VERSION 5.8 ;
BUSBITCHARS "[]" ;
DIVIDERCHAR "/" ;
UNITS
    DATABASE MICRONS 1000 ;
END UNITS

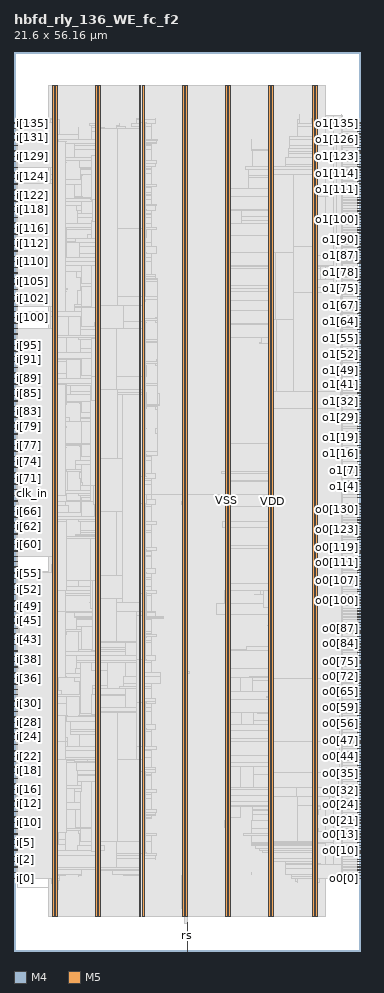
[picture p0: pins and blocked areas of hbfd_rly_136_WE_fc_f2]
MACRO hbfd_rly_136_WE_fc_f2
  FOREIGN hbfd_rly_136_WE_fc_f2 0 0 ;
  CLASS BLOCK ;
  SIZE 21.6 BY 56.16 ;
  PIN clk_in
    DIRECTION INPUT ;
    USE SIGNAL ;
    PORT
      LAYER M4 ;
        RECT  0 28.08 0.192 28.104 ;
    END
  END clk_in
  PIN clk_out0
    DIRECTION OUTPUT ;
    USE SIGNAL ;
    PORT
      LAYER M4 ;
        RECT  21.408 16.224 21.6 16.248 ;
    END
  END clk_out0
  PIN clk_out1
    DIRECTION OUTPUT ;
    USE SIGNAL ;
    PORT
      LAYER M4 ;
        RECT  21.408 39.984 21.6 40.008 ;
    END
  END clk_out1
  PIN i[0]
    DIRECTION INPUT ;
    USE SIGNAL ;
    PORT
      LAYER M4 ;
        RECT  0 4.512 0.192 4.536 ;
    END
  END i[0]
  PIN i[100]
    DIRECTION INPUT ;
    USE SIGNAL ;
    PORT
      LAYER M4 ;
        RECT  0 39.504 0.192 39.528 ;
    END
  END i[100]
  PIN i[101]
    DIRECTION INPUT ;
    USE SIGNAL ;
    PORT
      LAYER M4 ;
        RECT  0 39.888 0.192 39.912 ;
    END
  END i[101]
  PIN i[102]
    DIRECTION INPUT ;
    USE SIGNAL ;
    PORT
      LAYER M4 ;
        RECT  0 40.224 0.192 40.248 ;
    END
  END i[102]
  PIN i[103]
    DIRECTION INPUT ;
    USE SIGNAL ;
    PORT
      LAYER M4 ;
        RECT  0 40.56 0.192 40.584 ;
    END
  END i[103]
  PIN i[104]
    DIRECTION INPUT ;
    USE SIGNAL ;
    PORT
      LAYER M4 ;
        RECT  0 40.896 0.192 40.92 ;
    END
  END i[104]
  PIN i[105]
    DIRECTION INPUT ;
    USE SIGNAL ;
    PORT
      LAYER M4 ;
        RECT  0 41.28 0.192 41.304 ;
    END
  END i[105]
  PIN i[106]
    DIRECTION INPUT ;
    USE SIGNAL ;
    PORT
      LAYER M4 ;
        RECT  0 41.616 0.192 41.64 ;
    END
  END i[106]
  PIN i[107]
    DIRECTION INPUT ;
    USE SIGNAL ;
    PORT
      LAYER M4 ;
        RECT  0 41.952 0.192 41.976 ;
    END
  END i[107]
  PIN i[108]
    DIRECTION INPUT ;
    USE SIGNAL ;
    PORT
      LAYER M4 ;
        RECT  0 42.288 0.192 42.312 ;
    END
  END i[108]
  PIN i[109]
    DIRECTION INPUT ;
    USE SIGNAL ;
    PORT
      LAYER M4 ;
        RECT  0 42.624 0.192 42.648 ;
    END
  END i[109]
  PIN i[10]
    DIRECTION INPUT ;
    USE SIGNAL ;
    PORT
      LAYER M4 ;
        RECT  0 8.016 0.192 8.04 ;
    END
  END i[10]
  PIN i[110]
    DIRECTION INPUT ;
    USE SIGNAL ;
    PORT
      LAYER M4 ;
        RECT  0 43.008 0.192 43.032 ;
    END
  END i[110]
  PIN i[111]
    DIRECTION INPUT ;
    USE SIGNAL ;
    PORT
      LAYER M4 ;
        RECT  0 43.344 0.192 43.368 ;
    END
  END i[111]
  PIN i[112]
    DIRECTION INPUT ;
    USE SIGNAL ;
    PORT
      LAYER M4 ;
        RECT  0 43.68 0.192 43.704 ;
    END
  END i[112]
  PIN i[113]
    DIRECTION INPUT ;
    USE SIGNAL ;
    PORT
      LAYER M4 ;
        RECT  0 44.016 0.192 44.04 ;
    END
  END i[113]
  PIN i[114]
    DIRECTION INPUT ;
    USE SIGNAL ;
    PORT
      LAYER M4 ;
        RECT  0 44.4 0.192 44.424 ;
    END
  END i[114]
  PIN i[115]
    DIRECTION INPUT ;
    USE SIGNAL ;
    PORT
      LAYER M4 ;
        RECT  0 44.736 0.192 44.76 ;
    END
  END i[115]
  PIN i[116]
    DIRECTION INPUT ;
    USE SIGNAL ;
    PORT
      LAYER M4 ;
        RECT  0 45.072 0.192 45.096 ;
    END
  END i[116]
  PIN i[117]
    DIRECTION INPUT ;
    USE SIGNAL ;
    PORT
      LAYER M4 ;
        RECT  0 45.408 0.192 45.432 ;
    END
  END i[117]
  PIN i[118]
    DIRECTION INPUT ;
    USE SIGNAL ;
    PORT
      LAYER M4 ;
        RECT  0 45.744 0.192 45.768 ;
    END
  END i[118]
  PIN i[119]
    DIRECTION INPUT ;
    USE SIGNAL ;
    PORT
      LAYER M4 ;
        RECT  0 46.128 0.192 46.152 ;
    END
  END i[119]
  PIN i[11]
    DIRECTION INPUT ;
    USE SIGNAL ;
    PORT
      LAYER M4 ;
        RECT  0 8.352 0.192 8.376 ;
    END
  END i[11]
  PIN i[120]
    DIRECTION INPUT ;
    USE SIGNAL ;
    PORT
      LAYER M4 ;
        RECT  0 46.464 0.192 46.488 ;
    END
  END i[120]
  PIN i[121]
    DIRECTION INPUT ;
    USE SIGNAL ;
    PORT
      LAYER M4 ;
        RECT  0 46.8 0.192 46.824 ;
    END
  END i[121]
  PIN i[122]
    DIRECTION INPUT ;
    USE SIGNAL ;
    PORT
      LAYER M4 ;
        RECT  0 47.136 0.192 47.16 ;
    END
  END i[122]
  PIN i[123]
    DIRECTION INPUT ;
    USE SIGNAL ;
    PORT
      LAYER M4 ;
        RECT  0 47.472 0.192 47.496 ;
    END
  END i[123]
  PIN i[124]
    DIRECTION INPUT ;
    USE SIGNAL ;
    PORT
      LAYER M4 ;
        RECT  0 47.856 0.192 47.88 ;
    END
  END i[124]
  PIN i[125]
    DIRECTION INPUT ;
    USE SIGNAL ;
    PORT
      LAYER M4 ;
        RECT  0 48.192 0.192 48.216 ;
    END
  END i[125]
  PIN i[126]
    DIRECTION INPUT ;
    USE SIGNAL ;
    PORT
      LAYER M4 ;
        RECT  0 48.528 0.192 48.552 ;
    END
  END i[126]
  PIN i[127]
    DIRECTION INPUT ;
    USE SIGNAL ;
    PORT
      LAYER M4 ;
        RECT  0 48.864 0.192 48.888 ;
    END
  END i[127]
  PIN i[128]
    DIRECTION INPUT ;
    USE SIGNAL ;
    PORT
      LAYER M4 ;
        RECT  0 49.248 0.192 49.272 ;
    END
  END i[128]
  PIN i[129]
    DIRECTION INPUT ;
    USE SIGNAL ;
    PORT
      LAYER M4 ;
        RECT  0 49.584 0.192 49.608 ;
    END
  END i[129]
  PIN i[12]
    DIRECTION INPUT ;
    USE SIGNAL ;
    PORT
      LAYER M4 ;
        RECT  0 8.688 0.192 8.712 ;
    END
  END i[12]
  PIN i[130]
    DIRECTION INPUT ;
    USE SIGNAL ;
    PORT
      LAYER M4 ;
        RECT  0 49.92 0.192 49.944 ;
    END
  END i[130]
  PIN i[131]
    DIRECTION INPUT ;
    USE SIGNAL ;
    PORT
      LAYER M4 ;
        RECT  0 50.256 0.192 50.28 ;
    END
  END i[131]
  PIN i[132]
    DIRECTION INPUT ;
    USE SIGNAL ;
    PORT
      LAYER M4 ;
        RECT  0 50.592 0.192 50.616 ;
    END
  END i[132]
  PIN i[133]
    DIRECTION INPUT ;
    USE SIGNAL ;
    PORT
      LAYER M4 ;
        RECT  0 50.976 0.192 51 ;
    END
  END i[133]
  PIN i[134]
    DIRECTION INPUT ;
    USE SIGNAL ;
    PORT
      LAYER M4 ;
        RECT  0 51.312 0.192 51.336 ;
    END
  END i[134]
  PIN i[135]
    DIRECTION INPUT ;
    USE SIGNAL ;
    PORT
      LAYER M4 ;
        RECT  0 51.648 0.192 51.672 ;
    END
  END i[135]
  PIN i[13]
    DIRECTION INPUT ;
    USE SIGNAL ;
    PORT
      LAYER M4 ;
        RECT  0 9.024 0.192 9.048 ;
    END
  END i[13]
  PIN i[14]
    DIRECTION INPUT ;
    USE SIGNAL ;
    PORT
      LAYER M4 ;
        RECT  0 9.36 0.192 9.384 ;
    END
  END i[14]
  PIN i[15]
    DIRECTION INPUT ;
    USE SIGNAL ;
    PORT
      LAYER M4 ;
        RECT  0 9.744 0.192 9.768 ;
    END
  END i[15]
  PIN i[16]
    DIRECTION INPUT ;
    USE SIGNAL ;
    PORT
      LAYER M4 ;
        RECT  0 10.08 0.192 10.104 ;
    END
  END i[16]
  PIN i[17]
    DIRECTION INPUT ;
    USE SIGNAL ;
    PORT
      LAYER M4 ;
        RECT  0 10.416 0.192 10.44 ;
    END
  END i[17]
  PIN i[18]
    DIRECTION INPUT ;
    USE SIGNAL ;
    PORT
      LAYER M4 ;
        RECT  0 10.752 0.192 10.776 ;
    END
  END i[18]
  PIN i[19]
    DIRECTION INPUT ;
    USE SIGNAL ;
    PORT
      LAYER M4 ;
        RECT  0 11.136 0.192 11.16 ;
    END
  END i[19]
  PIN i[1]
    DIRECTION INPUT ;
    USE SIGNAL ;
    PORT
      LAYER M4 ;
        RECT  0 4.896 0.192 4.92 ;
    END
  END i[1]
  PIN i[20]
    DIRECTION INPUT ;
    USE SIGNAL ;
    PORT
      LAYER M4 ;
        RECT  0 11.472 0.192 11.496 ;
    END
  END i[20]
  PIN i[21]
    DIRECTION INPUT ;
    USE SIGNAL ;
    PORT
      LAYER M4 ;
        RECT  0 11.808 0.192 11.832 ;
    END
  END i[21]
  PIN i[22]
    DIRECTION INPUT ;
    USE SIGNAL ;
    PORT
      LAYER M4 ;
        RECT  0 12.144 0.192 12.168 ;
    END
  END i[22]
  PIN i[23]
    DIRECTION INPUT ;
    USE SIGNAL ;
    PORT
      LAYER M4 ;
        RECT  0 12.48 0.192 12.504 ;
    END
  END i[23]
  PIN i[24]
    DIRECTION INPUT ;
    USE SIGNAL ;
    PORT
      LAYER M4 ;
        RECT  0 12.864 0.192 12.888 ;
    END
  END i[24]
  PIN i[25]
    DIRECTION INPUT ;
    USE SIGNAL ;
    PORT
      LAYER M4 ;
        RECT  0 13.2 0.192 13.224 ;
    END
  END i[25]
  PIN i[26]
    DIRECTION INPUT ;
    USE SIGNAL ;
    PORT
      LAYER M4 ;
        RECT  0 13.536 0.192 13.56 ;
    END
  END i[26]
  PIN i[27]
    DIRECTION INPUT ;
    USE SIGNAL ;
    PORT
      LAYER M4 ;
        RECT  0 13.872 0.192 13.896 ;
    END
  END i[27]
  PIN i[28]
    DIRECTION INPUT ;
    USE SIGNAL ;
    PORT
      LAYER M4 ;
        RECT  0 14.256 0.192 14.28 ;
    END
  END i[28]
  PIN i[29]
    DIRECTION INPUT ;
    USE SIGNAL ;
    PORT
      LAYER M4 ;
        RECT  0 14.592 0.192 14.616 ;
    END
  END i[29]
  PIN i[2]
    DIRECTION INPUT ;
    USE SIGNAL ;
    PORT
      LAYER M4 ;
        RECT  0 5.232 0.192 5.256 ;
    END
  END i[2]
  PIN i[30]
    DIRECTION INPUT ;
    USE SIGNAL ;
    PORT
      LAYER M4 ;
        RECT  0 14.928 0.192 14.952 ;
    END
  END i[30]
  PIN i[31]
    DIRECTION INPUT ;
    USE SIGNAL ;
    PORT
      LAYER M4 ;
        RECT  0 15.264 0.192 15.288 ;
    END
  END i[31]
  PIN i[32]
    DIRECTION INPUT ;
    USE SIGNAL ;
    PORT
      LAYER M4 ;
        RECT  0 15.6 0.192 15.624 ;
    END
  END i[32]
  PIN i[33]
    DIRECTION INPUT ;
    USE SIGNAL ;
    PORT
      LAYER M4 ;
        RECT  0 15.984 0.192 16.008 ;
    END
  END i[33]
  PIN i[34]
    DIRECTION INPUT ;
    USE SIGNAL ;
    PORT
      LAYER M4 ;
        RECT  0 16.32 0.192 16.344 ;
    END
  END i[34]
  PIN i[35]
    DIRECTION INPUT ;
    USE SIGNAL ;
    PORT
      LAYER M4 ;
        RECT  0 16.656 0.192 16.68 ;
    END
  END i[35]
  PIN i[36]
    DIRECTION INPUT ;
    USE SIGNAL ;
    PORT
      LAYER M4 ;
        RECT  0 16.992 0.192 17.016 ;
    END
  END i[36]
  PIN i[37]
    DIRECTION INPUT ;
    USE SIGNAL ;
    PORT
      LAYER M4 ;
        RECT  0 17.328 0.192 17.352 ;
    END
  END i[37]
  PIN i[38]
    DIRECTION INPUT ;
    USE SIGNAL ;
    PORT
      LAYER M4 ;
        RECT  0 17.712 0.192 17.736 ;
    END
  END i[38]
  PIN i[39]
    DIRECTION INPUT ;
    USE SIGNAL ;
    PORT
      LAYER M4 ;
        RECT  0 18.048 0.192 18.072 ;
    END
  END i[39]
  PIN i[3]
    DIRECTION INPUT ;
    USE SIGNAL ;
    PORT
      LAYER M4 ;
        RECT  0 5.568 0.192 5.592 ;
    END
  END i[3]
  PIN i[40]
    DIRECTION INPUT ;
    USE SIGNAL ;
    PORT
      LAYER M4 ;
        RECT  0 18.384 0.192 18.408 ;
    END
  END i[40]
  PIN i[41]
    DIRECTION INPUT ;
    USE SIGNAL ;
    PORT
      LAYER M4 ;
        RECT  0 18.72 0.192 18.744 ;
    END
  END i[41]
  PIN i[42]
    DIRECTION INPUT ;
    USE SIGNAL ;
    PORT
      LAYER M4 ;
        RECT  0 19.104 0.192 19.128 ;
    END
  END i[42]
  PIN i[43]
    DIRECTION INPUT ;
    USE SIGNAL ;
    PORT
      LAYER M4 ;
        RECT  0 19.44 0.192 19.464 ;
    END
  END i[43]
  PIN i[44]
    DIRECTION INPUT ;
    USE SIGNAL ;
    PORT
      LAYER M4 ;
        RECT  0 19.776 0.192 19.8 ;
    END
  END i[44]
  PIN i[45]
    DIRECTION INPUT ;
    USE SIGNAL ;
    PORT
      LAYER M4 ;
        RECT  0 20.112 0.192 20.136 ;
    END
  END i[45]
  PIN i[46]
    DIRECTION INPUT ;
    USE SIGNAL ;
    PORT
      LAYER M4 ;
        RECT  0 20.448 0.192 20.472 ;
    END
  END i[46]
  PIN i[47]
    DIRECTION INPUT ;
    USE SIGNAL ;
    PORT
      LAYER M4 ;
        RECT  0 20.832 0.192 20.856 ;
    END
  END i[47]
  PIN i[48]
    DIRECTION INPUT ;
    USE SIGNAL ;
    PORT
      LAYER M4 ;
        RECT  0 21.168 0.192 21.192 ;
    END
  END i[48]
  PIN i[49]
    DIRECTION INPUT ;
    USE SIGNAL ;
    PORT
      LAYER M4 ;
        RECT  0 21.504 0.192 21.528 ;
    END
  END i[49]
  PIN i[4]
    DIRECTION INPUT ;
    USE SIGNAL ;
    PORT
      LAYER M4 ;
        RECT  0 5.904 0.192 5.928 ;
    END
  END i[4]
  PIN i[50]
    DIRECTION INPUT ;
    USE SIGNAL ;
    PORT
      LAYER M4 ;
        RECT  0 21.84 0.192 21.864 ;
    END
  END i[50]
  PIN i[51]
    DIRECTION INPUT ;
    USE SIGNAL ;
    PORT
      LAYER M4 ;
        RECT  0 22.224 0.192 22.248 ;
    END
  END i[51]
  PIN i[52]
    DIRECTION INPUT ;
    USE SIGNAL ;
    PORT
      LAYER M4 ;
        RECT  0 22.56 0.192 22.584 ;
    END
  END i[52]
  PIN i[53]
    DIRECTION INPUT ;
    USE SIGNAL ;
    PORT
      LAYER M4 ;
        RECT  0 22.896 0.192 22.92 ;
    END
  END i[53]
  PIN i[54]
    DIRECTION INPUT ;
    USE SIGNAL ;
    PORT
      LAYER M4 ;
        RECT  0 23.232 0.192 23.256 ;
    END
  END i[54]
  PIN i[55]
    DIRECTION INPUT ;
    USE SIGNAL ;
    PORT
      LAYER M4 ;
        RECT  0 23.568 0.192 23.592 ;
    END
  END i[55]
  PIN i[56]
    DIRECTION INPUT ;
    USE SIGNAL ;
    PORT
      LAYER M4 ;
        RECT  0 23.952 0.192 23.976 ;
    END
  END i[56]
  PIN i[57]
    DIRECTION INPUT ;
    USE SIGNAL ;
    PORT
      LAYER M4 ;
        RECT  0 24.288 0.192 24.312 ;
    END
  END i[57]
  PIN i[58]
    DIRECTION INPUT ;
    USE SIGNAL ;
    PORT
      LAYER M4 ;
        RECT  0 24.624 0.192 24.648 ;
    END
  END i[58]
  PIN i[59]
    DIRECTION INPUT ;
    USE SIGNAL ;
    PORT
      LAYER M4 ;
        RECT  0 24.96 0.192 24.984 ;
    END
  END i[59]
  PIN i[5]
    DIRECTION INPUT ;
    USE SIGNAL ;
    PORT
      LAYER M4 ;
        RECT  0 6.288 0.192 6.312 ;
    END
  END i[5]
  PIN i[60]
    DIRECTION INPUT ;
    USE SIGNAL ;
    PORT
      LAYER M4 ;
        RECT  0 25.344 0.192 25.368 ;
    END
  END i[60]
  PIN i[61]
    DIRECTION INPUT ;
    USE SIGNAL ;
    PORT
      LAYER M4 ;
        RECT  0 25.68 0.192 25.704 ;
    END
  END i[61]
  PIN i[62]
    DIRECTION INPUT ;
    USE SIGNAL ;
    PORT
      LAYER M4 ;
        RECT  0 26.016 0.192 26.04 ;
    END
  END i[62]
  PIN i[63]
    DIRECTION INPUT ;
    USE SIGNAL ;
    PORT
      LAYER M4 ;
        RECT  0 26.352 0.192 26.376 ;
    END
  END i[63]
  PIN i[64]
    DIRECTION INPUT ;
    USE SIGNAL ;
    PORT
      LAYER M4 ;
        RECT  0 26.688 0.192 26.712 ;
    END
  END i[64]
  PIN i[65]
    DIRECTION INPUT ;
    USE SIGNAL ;
    PORT
      LAYER M4 ;
        RECT  0 27.072 0.192 27.096 ;
    END
  END i[65]
  PIN i[66]
    DIRECTION INPUT ;
    USE SIGNAL ;
    PORT
      LAYER M4 ;
        RECT  0 27.408 0.192 27.432 ;
    END
  END i[66]
  PIN i[67]
    DIRECTION INPUT ;
    USE SIGNAL ;
    PORT
      LAYER M4 ;
        RECT  0 27.744 0.192 27.768 ;
    END
  END i[67]
  PIN i[68]
    DIRECTION INPUT ;
    USE SIGNAL ;
    PORT
      LAYER M4 ;
        RECT  0 28.416 0.192 28.44 ;
    END
  END i[68]
  PIN i[69]
    DIRECTION INPUT ;
    USE SIGNAL ;
    PORT
      LAYER M4 ;
        RECT  0 28.8 0.192 28.824 ;
    END
  END i[69]
  PIN i[6]
    DIRECTION INPUT ;
    USE SIGNAL ;
    PORT
      LAYER M4 ;
        RECT  0 6.624 0.192 6.648 ;
    END
  END i[6]
  PIN i[70]
    DIRECTION INPUT ;
    USE SIGNAL ;
    PORT
      LAYER M4 ;
        RECT  0 29.136 0.192 29.16 ;
    END
  END i[70]
  PIN i[71]
    DIRECTION INPUT ;
    USE SIGNAL ;
    PORT
      LAYER M4 ;
        RECT  0 29.472 0.192 29.496 ;
    END
  END i[71]
  PIN i[72]
    DIRECTION INPUT ;
    USE SIGNAL ;
    PORT
      LAYER M4 ;
        RECT  0 29.808 0.192 29.832 ;
    END
  END i[72]
  PIN i[73]
    DIRECTION INPUT ;
    USE SIGNAL ;
    PORT
      LAYER M4 ;
        RECT  0 30.192 0.192 30.216 ;
    END
  END i[73]
  PIN i[74]
    DIRECTION INPUT ;
    USE SIGNAL ;
    PORT
      LAYER M4 ;
        RECT  0 30.528 0.192 30.552 ;
    END
  END i[74]
  PIN i[75]
    DIRECTION INPUT ;
    USE SIGNAL ;
    PORT
      LAYER M4 ;
        RECT  0 30.864 0.192 30.888 ;
    END
  END i[75]
  PIN i[76]
    DIRECTION INPUT ;
    USE SIGNAL ;
    PORT
      LAYER M4 ;
        RECT  0 31.2 0.192 31.224 ;
    END
  END i[76]
  PIN i[77]
    DIRECTION INPUT ;
    USE SIGNAL ;
    PORT
      LAYER M4 ;
        RECT  0 31.536 0.192 31.56 ;
    END
  END i[77]
  PIN i[78]
    DIRECTION INPUT ;
    USE SIGNAL ;
    PORT
      LAYER M4 ;
        RECT  0 31.92 0.192 31.944 ;
    END
  END i[78]
  PIN i[79]
    DIRECTION INPUT ;
    USE SIGNAL ;
    PORT
      LAYER M4 ;
        RECT  0 32.256 0.192 32.28 ;
    END
  END i[79]
  PIN i[7]
    DIRECTION INPUT ;
    USE SIGNAL ;
    PORT
      LAYER M4 ;
        RECT  0 6.96 0.192 6.984 ;
    END
  END i[7]
  PIN i[80]
    DIRECTION INPUT ;
    USE SIGNAL ;
    PORT
      LAYER M4 ;
        RECT  0 32.592 0.192 32.616 ;
    END
  END i[80]
  PIN i[81]
    DIRECTION INPUT ;
    USE SIGNAL ;
    PORT
      LAYER M4 ;
        RECT  0 32.928 0.192 32.952 ;
    END
  END i[81]
  PIN i[82]
    DIRECTION INPUT ;
    USE SIGNAL ;
    PORT
      LAYER M4 ;
        RECT  0 33.312 0.192 33.336 ;
    END
  END i[82]
  PIN i[83]
    DIRECTION INPUT ;
    USE SIGNAL ;
    PORT
      LAYER M4 ;
        RECT  0 33.648 0.192 33.672 ;
    END
  END i[83]
  PIN i[84]
    DIRECTION INPUT ;
    USE SIGNAL ;
    PORT
      LAYER M4 ;
        RECT  0 33.984 0.192 34.008 ;
    END
  END i[84]
  PIN i[85]
    DIRECTION INPUT ;
    USE SIGNAL ;
    PORT
      LAYER M4 ;
        RECT  0 34.32 0.192 34.344 ;
    END
  END i[85]
  PIN i[86]
    DIRECTION INPUT ;
    USE SIGNAL ;
    PORT
      LAYER M4 ;
        RECT  0 34.656 0.192 34.68 ;
    END
  END i[86]
  PIN i[87]
    DIRECTION INPUT ;
    USE SIGNAL ;
    PORT
      LAYER M4 ;
        RECT  0 35.04 0.192 35.064 ;
    END
  END i[87]
  PIN i[88]
    DIRECTION INPUT ;
    USE SIGNAL ;
    PORT
      LAYER M4 ;
        RECT  0 35.376 0.192 35.4 ;
    END
  END i[88]
  PIN i[89]
    DIRECTION INPUT ;
    USE SIGNAL ;
    PORT
      LAYER M4 ;
        RECT  0 35.712 0.192 35.736 ;
    END
  END i[89]
  PIN i[8]
    DIRECTION INPUT ;
    USE SIGNAL ;
    PORT
      LAYER M4 ;
        RECT  0 7.296 0.192 7.32 ;
    END
  END i[8]
  PIN i[90]
    DIRECTION INPUT ;
    USE SIGNAL ;
    PORT
      LAYER M4 ;
        RECT  0 36.048 0.192 36.072 ;
    END
  END i[90]
  PIN i[91]
    DIRECTION INPUT ;
    USE SIGNAL ;
    PORT
      LAYER M4 ;
        RECT  0 36.384 0.192 36.408 ;
    END
  END i[91]
  PIN i[92]
    DIRECTION INPUT ;
    USE SIGNAL ;
    PORT
      LAYER M4 ;
        RECT  0 36.768 0.192 36.792 ;
    END
  END i[92]
  PIN i[93]
    DIRECTION INPUT ;
    USE SIGNAL ;
    PORT
      LAYER M4 ;
        RECT  0 37.104 0.192 37.128 ;
    END
  END i[93]
  PIN i[94]
    DIRECTION INPUT ;
    USE SIGNAL ;
    PORT
      LAYER M4 ;
        RECT  0 37.44 0.192 37.464 ;
    END
  END i[94]
  PIN i[95]
    DIRECTION INPUT ;
    USE SIGNAL ;
    PORT
      LAYER M4 ;
        RECT  0 37.776 0.192 37.8 ;
    END
  END i[95]
  PIN i[96]
    DIRECTION INPUT ;
    USE SIGNAL ;
    PORT
      LAYER M4 ;
        RECT  0 38.16 0.192 38.184 ;
    END
  END i[96]
  PIN i[97]
    DIRECTION INPUT ;
    USE SIGNAL ;
    PORT
      LAYER M4 ;
        RECT  0 38.496 0.192 38.52 ;
    END
  END i[97]
  PIN i[98]
    DIRECTION INPUT ;
    USE SIGNAL ;
    PORT
      LAYER M4 ;
        RECT  0 38.832 0.192 38.856 ;
    END
  END i[98]
  PIN i[99]
    DIRECTION INPUT ;
    USE SIGNAL ;
    PORT
      LAYER M4 ;
        RECT  0 39.168 0.192 39.192 ;
    END
  END i[99]
  PIN i[9]
    DIRECTION INPUT ;
    USE SIGNAL ;
    PORT
      LAYER M4 ;
        RECT  0 7.632 0.192 7.656 ;
    END
  END i[9]
  PIN o0[0]
    DIRECTION OUTPUT ;
    USE SIGNAL ;
    PORT
      LAYER M4 ;
        RECT  21.408 4.512 21.6 4.536 ;
    END
  END o0[0]
  PIN o0[100]
    DIRECTION OUTPUT ;
    USE SIGNAL ;
    PORT
      LAYER M4 ;
        RECT  21.408 21.888 21.6 21.912 ;
    END
  END o0[100]
  PIN o0[101]
    DIRECTION OUTPUT ;
    USE SIGNAL ;
    PORT
      LAYER M4 ;
        RECT  21.408 22.032 21.6 22.056 ;
    END
  END o0[101]
  PIN o0[102]
    DIRECTION OUTPUT ;
    USE SIGNAL ;
    PORT
      LAYER M4 ;
        RECT  21.408 22.224 21.6 22.248 ;
    END
  END o0[102]
  PIN o0[103]
    DIRECTION OUTPUT ;
    USE SIGNAL ;
    PORT
      LAYER M4 ;
        RECT  21.408 22.416 21.6 22.44 ;
    END
  END o0[103]
  PIN o0[104]
    DIRECTION OUTPUT ;
    USE SIGNAL ;
    PORT
      LAYER M4 ;
        RECT  21.408 22.56 21.6 22.584 ;
    END
  END o0[104]
  PIN o0[105]
    DIRECTION OUTPUT ;
    USE SIGNAL ;
    PORT
      LAYER M4 ;
        RECT  21.408 22.752 21.6 22.776 ;
    END
  END o0[105]
  PIN o0[106]
    DIRECTION OUTPUT ;
    USE SIGNAL ;
    PORT
      LAYER M4 ;
        RECT  21.408 22.896 21.6 22.92 ;
    END
  END o0[106]
  PIN o0[107]
    DIRECTION OUTPUT ;
    USE SIGNAL ;
    PORT
      LAYER M4 ;
        RECT  21.408 23.088 21.6 23.112 ;
    END
  END o0[107]
  PIN o0[108]
    DIRECTION OUTPUT ;
    USE SIGNAL ;
    PORT
      LAYER M4 ;
        RECT  21.408 23.232 21.6 23.256 ;
    END
  END o0[108]
  PIN o0[109]
    DIRECTION OUTPUT ;
    USE SIGNAL ;
    PORT
      LAYER M4 ;
        RECT  21.408 23.424 21.6 23.448 ;
    END
  END o0[109]
  PIN o0[10]
    DIRECTION OUTPUT ;
    USE SIGNAL ;
    PORT
      LAYER M4 ;
        RECT  21.408 6.24 21.6 6.264 ;
    END
  END o0[10]
  PIN o0[110]
    DIRECTION OUTPUT ;
    USE SIGNAL ;
    PORT
      LAYER M4 ;
        RECT  21.408 23.616 21.6 23.64 ;
    END
  END o0[110]
  PIN o0[111]
    DIRECTION OUTPUT ;
    USE SIGNAL ;
    PORT
      LAYER M4 ;
        RECT  21.408 23.76 21.6 23.784 ;
    END
  END o0[111]
  PIN o0[112]
    DIRECTION OUTPUT ;
    USE SIGNAL ;
    PORT
      LAYER M4 ;
        RECT  21.408 23.952 21.6 23.976 ;
    END
  END o0[112]
  PIN o0[113]
    DIRECTION OUTPUT ;
    USE SIGNAL ;
    PORT
      LAYER M4 ;
        RECT  21.408 24.096 21.6 24.12 ;
    END
  END o0[113]
  PIN o0[114]
    DIRECTION OUTPUT ;
    USE SIGNAL ;
    PORT
      LAYER M4 ;
        RECT  21.408 24.288 21.6 24.312 ;
    END
  END o0[114]
  PIN o0[115]
    DIRECTION OUTPUT ;
    USE SIGNAL ;
    PORT
      LAYER M4 ;
        RECT  21.408 24.48 21.6 24.504 ;
    END
  END o0[115]
  PIN o0[116]
    DIRECTION OUTPUT ;
    USE SIGNAL ;
    PORT
      LAYER M4 ;
        RECT  21.408 24.624 21.6 24.648 ;
    END
  END o0[116]
  PIN o0[117]
    DIRECTION OUTPUT ;
    USE SIGNAL ;
    PORT
      LAYER M4 ;
        RECT  21.408 24.816 21.6 24.84 ;
    END
  END o0[117]
  PIN o0[118]
    DIRECTION OUTPUT ;
    USE SIGNAL ;
    PORT
      LAYER M4 ;
        RECT  21.408 24.96 21.6 24.984 ;
    END
  END o0[118]
  PIN o0[119]
    DIRECTION OUTPUT ;
    USE SIGNAL ;
    PORT
      LAYER M4 ;
        RECT  21.408 25.152 21.6 25.176 ;
    END
  END o0[119]
  PIN o0[11]
    DIRECTION OUTPUT ;
    USE SIGNAL ;
    PORT
      LAYER M4 ;
        RECT  21.408 6.432 21.6 6.456 ;
    END
  END o0[11]
  PIN o0[120]
    DIRECTION OUTPUT ;
    USE SIGNAL ;
    PORT
      LAYER M4 ;
        RECT  21.408 25.296 21.6 25.32 ;
    END
  END o0[120]
  PIN o0[121]
    DIRECTION OUTPUT ;
    USE SIGNAL ;
    PORT
      LAYER M4 ;
        RECT  21.408 25.488 21.6 25.512 ;
    END
  END o0[121]
  PIN o0[122]
    DIRECTION OUTPUT ;
    USE SIGNAL ;
    PORT
      LAYER M4 ;
        RECT  21.408 25.68 21.6 25.704 ;
    END
  END o0[122]
  PIN o0[123]
    DIRECTION OUTPUT ;
    USE SIGNAL ;
    PORT
      LAYER M4 ;
        RECT  21.408 25.824 21.6 25.848 ;
    END
  END o0[123]
  PIN o0[124]
    DIRECTION OUTPUT ;
    USE SIGNAL ;
    PORT
      LAYER M4 ;
        RECT  21.408 26.016 21.6 26.04 ;
    END
  END o0[124]
  PIN o0[125]
    DIRECTION OUTPUT ;
    USE SIGNAL ;
    PORT
      LAYER M4 ;
        RECT  21.408 26.16 21.6 26.184 ;
    END
  END o0[125]
  PIN o0[126]
    DIRECTION OUTPUT ;
    USE SIGNAL ;
    PORT
      LAYER M4 ;
        RECT  21.408 26.352 21.6 26.376 ;
    END
  END o0[126]
  PIN o0[127]
    DIRECTION OUTPUT ;
    USE SIGNAL ;
    PORT
      LAYER M4 ;
        RECT  21.408 26.496 21.6 26.52 ;
    END
  END o0[127]
  PIN o0[128]
    DIRECTION OUTPUT ;
    USE SIGNAL ;
    PORT
      LAYER M4 ;
        RECT  21.408 26.688 21.6 26.712 ;
    END
  END o0[128]
  PIN o0[129]
    DIRECTION OUTPUT ;
    USE SIGNAL ;
    PORT
      LAYER M4 ;
        RECT  21.408 26.88 21.6 26.904 ;
    END
  END o0[129]
  PIN o0[12]
    DIRECTION OUTPUT ;
    USE SIGNAL ;
    PORT
      LAYER M4 ;
        RECT  21.408 6.576 21.6 6.6 ;
    END
  END o0[12]
  PIN o0[130]
    DIRECTION OUTPUT ;
    USE SIGNAL ;
    PORT
      LAYER M4 ;
        RECT  21.408 27.024 21.6 27.048 ;
    END
  END o0[130]
  PIN o0[131]
    DIRECTION OUTPUT ;
    USE SIGNAL ;
    PORT
      LAYER M4 ;
        RECT  21.408 27.216 21.6 27.24 ;
    END
  END o0[131]
  PIN o0[132]
    DIRECTION OUTPUT ;
    USE SIGNAL ;
    PORT
      LAYER M4 ;
        RECT  21.408 27.36 21.6 27.384 ;
    END
  END o0[132]
  PIN o0[133]
    DIRECTION OUTPUT ;
    USE SIGNAL ;
    PORT
      LAYER M4 ;
        RECT  21.408 27.552 21.6 27.576 ;
    END
  END o0[133]
  PIN o0[134]
    DIRECTION OUTPUT ;
    USE SIGNAL ;
    PORT
      LAYER M4 ;
        RECT  21.408 27.744 21.6 27.768 ;
    END
  END o0[134]
  PIN o0[135]
    DIRECTION OUTPUT ;
    USE SIGNAL ;
    PORT
      LAYER M4 ;
        RECT  21.408 27.888 21.6 27.912 ;
    END
  END o0[135]
  PIN o0[13]
    DIRECTION OUTPUT ;
    USE SIGNAL ;
    PORT
      LAYER M4 ;
        RECT  21.408 6.768 21.6 6.792 ;
    END
  END o0[13]
  PIN o0[14]
    DIRECTION OUTPUT ;
    USE SIGNAL ;
    PORT
      LAYER M4 ;
        RECT  21.408 6.96 21.6 6.984 ;
    END
  END o0[14]
  PIN o0[15]
    DIRECTION OUTPUT ;
    USE SIGNAL ;
    PORT
      LAYER M4 ;
        RECT  21.408 7.104 21.6 7.128 ;
    END
  END o0[15]
  PIN o0[16]
    DIRECTION OUTPUT ;
    USE SIGNAL ;
    PORT
      LAYER M4 ;
        RECT  21.408 7.296 21.6 7.32 ;
    END
  END o0[16]
  PIN o0[17]
    DIRECTION OUTPUT ;
    USE SIGNAL ;
    PORT
      LAYER M4 ;
        RECT  21.408 7.44 21.6 7.464 ;
    END
  END o0[17]
  PIN o0[18]
    DIRECTION OUTPUT ;
    USE SIGNAL ;
    PORT
      LAYER M4 ;
        RECT  21.408 7.632 21.6 7.656 ;
    END
  END o0[18]
  PIN o0[19]
    DIRECTION OUTPUT ;
    USE SIGNAL ;
    PORT
      LAYER M4 ;
        RECT  21.408 7.776 21.6 7.8 ;
    END
  END o0[19]
  PIN o0[1]
    DIRECTION OUTPUT ;
    USE SIGNAL ;
    PORT
      LAYER M4 ;
        RECT  21.408 4.704 21.6 4.728 ;
    END
  END o0[1]
  PIN o0[20]
    DIRECTION OUTPUT ;
    USE SIGNAL ;
    PORT
      LAYER M4 ;
        RECT  21.408 7.968 21.6 7.992 ;
    END
  END o0[20]
  PIN o0[21]
    DIRECTION OUTPUT ;
    USE SIGNAL ;
    PORT
      LAYER M4 ;
        RECT  21.408 8.16 21.6 8.184 ;
    END
  END o0[21]
  PIN o0[22]
    DIRECTION OUTPUT ;
    USE SIGNAL ;
    PORT
      LAYER M4 ;
        RECT  21.408 8.304 21.6 8.328 ;
    END
  END o0[22]
  PIN o0[23]
    DIRECTION OUTPUT ;
    USE SIGNAL ;
    PORT
      LAYER M4 ;
        RECT  21.408 8.496 21.6 8.52 ;
    END
  END o0[23]
  PIN o0[24]
    DIRECTION OUTPUT ;
    USE SIGNAL ;
    PORT
      LAYER M4 ;
        RECT  21.408 8.64 21.6 8.664 ;
    END
  END o0[24]
  PIN o0[25]
    DIRECTION OUTPUT ;
    USE SIGNAL ;
    PORT
      LAYER M4 ;
        RECT  21.408 8.832 21.6 8.856 ;
    END
  END o0[25]
  PIN o0[26]
    DIRECTION OUTPUT ;
    USE SIGNAL ;
    PORT
      LAYER M4 ;
        RECT  21.408 8.976 21.6 9 ;
    END
  END o0[26]
  PIN o0[27]
    DIRECTION OUTPUT ;
    USE SIGNAL ;
    PORT
      LAYER M4 ;
        RECT  21.408 9.168 21.6 9.192 ;
    END
  END o0[27]
  PIN o0[28]
    DIRECTION OUTPUT ;
    USE SIGNAL ;
    PORT
      LAYER M4 ;
        RECT  21.408 9.36 21.6 9.384 ;
    END
  END o0[28]
  PIN o0[29]
    DIRECTION OUTPUT ;
    USE SIGNAL ;
    PORT
      LAYER M4 ;
        RECT  21.408 9.504 21.6 9.528 ;
    END
  END o0[29]
  PIN o0[2]
    DIRECTION OUTPUT ;
    USE SIGNAL ;
    PORT
      LAYER M4 ;
        RECT  21.408 4.896 21.6 4.92 ;
    END
  END o0[2]
  PIN o0[30]
    DIRECTION OUTPUT ;
    USE SIGNAL ;
    PORT
      LAYER M4 ;
        RECT  21.408 9.696 21.6 9.72 ;
    END
  END o0[30]
  PIN o0[31]
    DIRECTION OUTPUT ;
    USE SIGNAL ;
    PORT
      LAYER M4 ;
        RECT  21.408 9.84 21.6 9.864 ;
    END
  END o0[31]
  PIN o0[32]
    DIRECTION OUTPUT ;
    USE SIGNAL ;
    PORT
      LAYER M4 ;
        RECT  21.408 10.032 21.6 10.056 ;
    END
  END o0[32]
  PIN o0[33]
    DIRECTION OUTPUT ;
    USE SIGNAL ;
    PORT
      LAYER M4 ;
        RECT  21.408 10.224 21.6 10.248 ;
    END
  END o0[33]
  PIN o0[34]
    DIRECTION OUTPUT ;
    USE SIGNAL ;
    PORT
      LAYER M4 ;
        RECT  21.408 10.368 21.6 10.392 ;
    END
  END o0[34]
  PIN o0[35]
    DIRECTION OUTPUT ;
    USE SIGNAL ;
    PORT
      LAYER M4 ;
        RECT  21.408 10.56 21.6 10.584 ;
    END
  END o0[35]
  PIN o0[36]
    DIRECTION OUTPUT ;
    USE SIGNAL ;
    PORT
      LAYER M4 ;
        RECT  21.408 10.704 21.6 10.728 ;
    END
  END o0[36]
  PIN o0[37]
    DIRECTION OUTPUT ;
    USE SIGNAL ;
    PORT
      LAYER M4 ;
        RECT  21.408 10.896 21.6 10.92 ;
    END
  END o0[37]
  PIN o0[38]
    DIRECTION OUTPUT ;
    USE SIGNAL ;
    PORT
      LAYER M4 ;
        RECT  21.408 11.04 21.6 11.064 ;
    END
  END o0[38]
  PIN o0[39]
    DIRECTION OUTPUT ;
    USE SIGNAL ;
    PORT
      LAYER M4 ;
        RECT  21.408 11.232 21.6 11.256 ;
    END
  END o0[39]
  PIN o0[3]
    DIRECTION OUTPUT ;
    USE SIGNAL ;
    PORT
      LAYER M4 ;
        RECT  21.408 5.04 21.6 5.064 ;
    END
  END o0[3]
  PIN o0[40]
    DIRECTION OUTPUT ;
    USE SIGNAL ;
    PORT
      LAYER M4 ;
        RECT  21.408 11.424 21.6 11.448 ;
    END
  END o0[40]
  PIN o0[41]
    DIRECTION OUTPUT ;
    USE SIGNAL ;
    PORT
      LAYER M4 ;
        RECT  21.408 11.568 21.6 11.592 ;
    END
  END o0[41]
  PIN o0[42]
    DIRECTION OUTPUT ;
    USE SIGNAL ;
    PORT
      LAYER M4 ;
        RECT  21.408 11.76 21.6 11.784 ;
    END
  END o0[42]
  PIN o0[43]
    DIRECTION OUTPUT ;
    USE SIGNAL ;
    PORT
      LAYER M4 ;
        RECT  21.408 11.904 21.6 11.928 ;
    END
  END o0[43]
  PIN o0[44]
    DIRECTION OUTPUT ;
    USE SIGNAL ;
    PORT
      LAYER M4 ;
        RECT  21.408 12.096 21.6 12.12 ;
    END
  END o0[44]
  PIN o0[45]
    DIRECTION OUTPUT ;
    USE SIGNAL ;
    PORT
      LAYER M4 ;
        RECT  21.408 12.24 21.6 12.264 ;
    END
  END o0[45]
  PIN o0[46]
    DIRECTION OUTPUT ;
    USE SIGNAL ;
    PORT
      LAYER M4 ;
        RECT  21.408 12.432 21.6 12.456 ;
    END
  END o0[46]
  PIN o0[47]
    DIRECTION OUTPUT ;
    USE SIGNAL ;
    PORT
      LAYER M4 ;
        RECT  21.408 12.624 21.6 12.648 ;
    END
  END o0[47]
  PIN o0[48]
    DIRECTION OUTPUT ;
    USE SIGNAL ;
    PORT
      LAYER M4 ;
        RECT  21.408 12.768 21.6 12.792 ;
    END
  END o0[48]
  PIN o0[49]
    DIRECTION OUTPUT ;
    USE SIGNAL ;
    PORT
      LAYER M4 ;
        RECT  21.408 12.96 21.6 12.984 ;
    END
  END o0[49]
  PIN o0[4]
    DIRECTION OUTPUT ;
    USE SIGNAL ;
    PORT
      LAYER M4 ;
        RECT  21.408 5.232 21.6 5.256 ;
    END
  END o0[4]
  PIN o0[50]
    DIRECTION OUTPUT ;
    USE SIGNAL ;
    PORT
      LAYER M4 ;
        RECT  21.408 13.104 21.6 13.128 ;
    END
  END o0[50]
  PIN o0[51]
    DIRECTION OUTPUT ;
    USE SIGNAL ;
    PORT
      LAYER M4 ;
        RECT  21.408 13.296 21.6 13.32 ;
    END
  END o0[51]
  PIN o0[52]
    DIRECTION OUTPUT ;
    USE SIGNAL ;
    PORT
      LAYER M4 ;
        RECT  21.408 13.44 21.6 13.464 ;
    END
  END o0[52]
  PIN o0[53]
    DIRECTION OUTPUT ;
    USE SIGNAL ;
    PORT
      LAYER M4 ;
        RECT  21.408 13.632 21.6 13.656 ;
    END
  END o0[53]
  PIN o0[54]
    DIRECTION OUTPUT ;
    USE SIGNAL ;
    PORT
      LAYER M4 ;
        RECT  21.408 13.824 21.6 13.848 ;
    END
  END o0[54]
  PIN o0[55]
    DIRECTION OUTPUT ;
    USE SIGNAL ;
    PORT
      LAYER M4 ;
        RECT  21.408 13.968 21.6 13.992 ;
    END
  END o0[55]
  PIN o0[56]
    DIRECTION OUTPUT ;
    USE SIGNAL ;
    PORT
      LAYER M4 ;
        RECT  21.408 14.16 21.6 14.184 ;
    END
  END o0[56]
  PIN o0[57]
    DIRECTION OUTPUT ;
    USE SIGNAL ;
    PORT
      LAYER M4 ;
        RECT  21.408 14.304 21.6 14.328 ;
    END
  END o0[57]
  PIN o0[58]
    DIRECTION OUTPUT ;
    USE SIGNAL ;
    PORT
      LAYER M4 ;
        RECT  21.408 14.496 21.6 14.52 ;
    END
  END o0[58]
  PIN o0[59]
    DIRECTION OUTPUT ;
    USE SIGNAL ;
    PORT
      LAYER M4 ;
        RECT  21.408 14.688 21.6 14.712 ;
    END
  END o0[59]
  PIN o0[5]
    DIRECTION OUTPUT ;
    USE SIGNAL ;
    PORT
      LAYER M4 ;
        RECT  21.408 5.376 21.6 5.4 ;
    END
  END o0[5]
  PIN o0[60]
    DIRECTION OUTPUT ;
    USE SIGNAL ;
    PORT
      LAYER M4 ;
        RECT  21.408 14.832 21.6 14.856 ;
    END
  END o0[60]
  PIN o0[61]
    DIRECTION OUTPUT ;
    USE SIGNAL ;
    PORT
      LAYER M4 ;
        RECT  21.408 15.024 21.6 15.048 ;
    END
  END o0[61]
  PIN o0[62]
    DIRECTION OUTPUT ;
    USE SIGNAL ;
    PORT
      LAYER M4 ;
        RECT  21.408 15.168 21.6 15.192 ;
    END
  END o0[62]
  PIN o0[63]
    DIRECTION OUTPUT ;
    USE SIGNAL ;
    PORT
      LAYER M4 ;
        RECT  21.408 15.36 21.6 15.384 ;
    END
  END o0[63]
  PIN o0[64]
    DIRECTION OUTPUT ;
    USE SIGNAL ;
    PORT
      LAYER M4 ;
        RECT  21.408 15.504 21.6 15.528 ;
    END
  END o0[64]
  PIN o0[65]
    DIRECTION OUTPUT ;
    USE SIGNAL ;
    PORT
      LAYER M4 ;
        RECT  21.408 15.696 21.6 15.72 ;
    END
  END o0[65]
  PIN o0[66]
    DIRECTION OUTPUT ;
    USE SIGNAL ;
    PORT
      LAYER M4 ;
        RECT  21.408 15.888 21.6 15.912 ;
    END
  END o0[66]
  PIN o0[67]
    DIRECTION OUTPUT ;
    USE SIGNAL ;
    PORT
      LAYER M4 ;
        RECT  21.408 16.032 21.6 16.056 ;
    END
  END o0[67]
  PIN o0[68]
    DIRECTION OUTPUT ;
    USE SIGNAL ;
    PORT
      LAYER M4 ;
        RECT  21.408 16.368 21.6 16.392 ;
    END
  END o0[68]
  PIN o0[69]
    DIRECTION OUTPUT ;
    USE SIGNAL ;
    PORT
      LAYER M4 ;
        RECT  21.408 16.56 21.6 16.584 ;
    END
  END o0[69]
  PIN o0[6]
    DIRECTION OUTPUT ;
    USE SIGNAL ;
    PORT
      LAYER M4 ;
        RECT  21.408 5.568 21.6 5.592 ;
    END
  END o0[6]
  PIN o0[70]
    DIRECTION OUTPUT ;
    USE SIGNAL ;
    PORT
      LAYER M4 ;
        RECT  21.408 16.704 21.6 16.728 ;
    END
  END o0[70]
  PIN o0[71]
    DIRECTION OUTPUT ;
    USE SIGNAL ;
    PORT
      LAYER M4 ;
        RECT  21.408 16.896 21.6 16.92 ;
    END
  END o0[71]
  PIN o0[72]
    DIRECTION OUTPUT ;
    USE SIGNAL ;
    PORT
      LAYER M4 ;
        RECT  21.408 17.088 21.6 17.112 ;
    END
  END o0[72]
  PIN o0[73]
    DIRECTION OUTPUT ;
    USE SIGNAL ;
    PORT
      LAYER M4 ;
        RECT  21.408 17.232 21.6 17.256 ;
    END
  END o0[73]
  PIN o0[74]
    DIRECTION OUTPUT ;
    USE SIGNAL ;
    PORT
      LAYER M4 ;
        RECT  21.408 17.424 21.6 17.448 ;
    END
  END o0[74]
  PIN o0[75]
    DIRECTION OUTPUT ;
    USE SIGNAL ;
    PORT
      LAYER M4 ;
        RECT  21.408 17.568 21.6 17.592 ;
    END
  END o0[75]
  PIN o0[76]
    DIRECTION OUTPUT ;
    USE SIGNAL ;
    PORT
      LAYER M4 ;
        RECT  21.408 17.76 21.6 17.784 ;
    END
  END o0[76]
  PIN o0[77]
    DIRECTION OUTPUT ;
    USE SIGNAL ;
    PORT
      LAYER M4 ;
        RECT  21.408 17.952 21.6 17.976 ;
    END
  END o0[77]
  PIN o0[78]
    DIRECTION OUTPUT ;
    USE SIGNAL ;
    PORT
      LAYER M4 ;
        RECT  21.408 18.096 21.6 18.12 ;
    END
  END o0[78]
  PIN o0[79]
    DIRECTION OUTPUT ;
    USE SIGNAL ;
    PORT
      LAYER M4 ;
        RECT  21.408 18.288 21.6 18.312 ;
    END
  END o0[79]
  PIN o0[7]
    DIRECTION OUTPUT ;
    USE SIGNAL ;
    PORT
      LAYER M4 ;
        RECT  21.408 5.712 21.6 5.736 ;
    END
  END o0[7]
  PIN o0[80]
    DIRECTION OUTPUT ;
    USE SIGNAL ;
    PORT
      LAYER M4 ;
        RECT  21.408 18.432 21.6 18.456 ;
    END
  END o0[80]
  PIN o0[81]
    DIRECTION OUTPUT ;
    USE SIGNAL ;
    PORT
      LAYER M4 ;
        RECT  21.408 18.624 21.6 18.648 ;
    END
  END o0[81]
  PIN o0[82]
    DIRECTION OUTPUT ;
    USE SIGNAL ;
    PORT
      LAYER M4 ;
        RECT  21.408 18.768 21.6 18.792 ;
    END
  END o0[82]
  PIN o0[83]
    DIRECTION OUTPUT ;
    USE SIGNAL ;
    PORT
      LAYER M4 ;
        RECT  21.408 18.96 21.6 18.984 ;
    END
  END o0[83]
  PIN o0[84]
    DIRECTION OUTPUT ;
    USE SIGNAL ;
    PORT
      LAYER M4 ;
        RECT  21.408 19.152 21.6 19.176 ;
    END
  END o0[84]
  PIN o0[85]
    DIRECTION OUTPUT ;
    USE SIGNAL ;
    PORT
      LAYER M4 ;
        RECT  21.408 19.296 21.6 19.32 ;
    END
  END o0[85]
  PIN o0[86]
    DIRECTION OUTPUT ;
    USE SIGNAL ;
    PORT
      LAYER M4 ;
        RECT  21.408 19.488 21.6 19.512 ;
    END
  END o0[86]
  PIN o0[87]
    DIRECTION OUTPUT ;
    USE SIGNAL ;
    PORT
      LAYER M4 ;
        RECT  21.408 19.632 21.6 19.656 ;
    END
  END o0[87]
  PIN o0[88]
    DIRECTION OUTPUT ;
    USE SIGNAL ;
    PORT
      LAYER M4 ;
        RECT  21.408 19.824 21.6 19.848 ;
    END
  END o0[88]
  PIN o0[89]
    DIRECTION OUTPUT ;
    USE SIGNAL ;
    PORT
      LAYER M4 ;
        RECT  21.408 19.968 21.6 19.992 ;
    END
  END o0[89]
  PIN o0[8]
    DIRECTION OUTPUT ;
    USE SIGNAL ;
    PORT
      LAYER M4 ;
        RECT  21.408 5.904 21.6 5.928 ;
    END
  END o0[8]
  PIN o0[90]
    DIRECTION OUTPUT ;
    USE SIGNAL ;
    PORT
      LAYER M4 ;
        RECT  21.408 20.16 21.6 20.184 ;
    END
  END o0[90]
  PIN o0[91]
    DIRECTION OUTPUT ;
    USE SIGNAL ;
    PORT
      LAYER M4 ;
        RECT  21.408 20.352 21.6 20.376 ;
    END
  END o0[91]
  PIN o0[92]
    DIRECTION OUTPUT ;
    USE SIGNAL ;
    PORT
      LAYER M4 ;
        RECT  21.408 20.496 21.6 20.52 ;
    END
  END o0[92]
  PIN o0[93]
    DIRECTION OUTPUT ;
    USE SIGNAL ;
    PORT
      LAYER M4 ;
        RECT  21.408 20.688 21.6 20.712 ;
    END
  END o0[93]
  PIN o0[94]
    DIRECTION OUTPUT ;
    USE SIGNAL ;
    PORT
      LAYER M4 ;
        RECT  21.408 20.832 21.6 20.856 ;
    END
  END o0[94]
  PIN o0[95]
    DIRECTION OUTPUT ;
    USE SIGNAL ;
    PORT
      LAYER M4 ;
        RECT  21.408 21.024 21.6 21.048 ;
    END
  END o0[95]
  PIN o0[96]
    DIRECTION OUTPUT ;
    USE SIGNAL ;
    PORT
      LAYER M4 ;
        RECT  21.408 21.216 21.6 21.24 ;
    END
  END o0[96]
  PIN o0[97]
    DIRECTION OUTPUT ;
    USE SIGNAL ;
    PORT
      LAYER M4 ;
        RECT  21.408 21.36 21.6 21.384 ;
    END
  END o0[97]
  PIN o0[98]
    DIRECTION OUTPUT ;
    USE SIGNAL ;
    PORT
      LAYER M4 ;
        RECT  21.408 21.552 21.6 21.576 ;
    END
  END o0[98]
  PIN o0[99]
    DIRECTION OUTPUT ;
    USE SIGNAL ;
    PORT
      LAYER M4 ;
        RECT  21.408 21.696 21.6 21.72 ;
    END
  END o0[99]
  PIN o0[9]
    DIRECTION OUTPUT ;
    USE SIGNAL ;
    PORT
      LAYER M4 ;
        RECT  21.408 6.096 21.6 6.12 ;
    END
  END o0[9]
  PIN o1[0]
    DIRECTION OUTPUT ;
    USE SIGNAL ;
    PORT
      LAYER M4 ;
        RECT  21.408 28.272 21.6 28.296 ;
    END
  END o1[0]
  PIN o1[100]
    DIRECTION OUTPUT ;
    USE SIGNAL ;
    PORT
      LAYER M4 ;
        RECT  21.408 45.648 21.6 45.672 ;
    END
  END o1[100]
  PIN o1[101]
    DIRECTION OUTPUT ;
    USE SIGNAL ;
    PORT
      LAYER M4 ;
        RECT  21.408 45.792 21.6 45.816 ;
    END
  END o1[101]
  PIN o1[102]
    DIRECTION OUTPUT ;
    USE SIGNAL ;
    PORT
      LAYER M4 ;
        RECT  21.408 45.984 21.6 46.008 ;
    END
  END o1[102]
  PIN o1[103]
    DIRECTION OUTPUT ;
    USE SIGNAL ;
    PORT
      LAYER M4 ;
        RECT  21.408 46.176 21.6 46.2 ;
    END
  END o1[103]
  PIN o1[104]
    DIRECTION OUTPUT ;
    USE SIGNAL ;
    PORT
      LAYER M4 ;
        RECT  21.408 46.32 21.6 46.344 ;
    END
  END o1[104]
  PIN o1[105]
    DIRECTION OUTPUT ;
    USE SIGNAL ;
    PORT
      LAYER M4 ;
        RECT  21.408 46.512 21.6 46.536 ;
    END
  END o1[105]
  PIN o1[106]
    DIRECTION OUTPUT ;
    USE SIGNAL ;
    PORT
      LAYER M4 ;
        RECT  21.408 46.656 21.6 46.68 ;
    END
  END o1[106]
  PIN o1[107]
    DIRECTION OUTPUT ;
    USE SIGNAL ;
    PORT
      LAYER M4 ;
        RECT  21.408 46.848 21.6 46.872 ;
    END
  END o1[107]
  PIN o1[108]
    DIRECTION OUTPUT ;
    USE SIGNAL ;
    PORT
      LAYER M4 ;
        RECT  21.408 46.992 21.6 47.016 ;
    END
  END o1[108]
  PIN o1[109]
    DIRECTION OUTPUT ;
    USE SIGNAL ;
    PORT
      LAYER M4 ;
        RECT  21.408 47.184 21.6 47.208 ;
    END
  END o1[109]
  PIN o1[10]
    DIRECTION OUTPUT ;
    USE SIGNAL ;
    PORT
      LAYER M4 ;
        RECT  21.408 30 21.6 30.024 ;
    END
  END o1[10]
  PIN o1[110]
    DIRECTION OUTPUT ;
    USE SIGNAL ;
    PORT
      LAYER M4 ;
        RECT  21.408 47.376 21.6 47.4 ;
    END
  END o1[110]
  PIN o1[111]
    DIRECTION OUTPUT ;
    USE SIGNAL ;
    PORT
      LAYER M4 ;
        RECT  21.408 47.52 21.6 47.544 ;
    END
  END o1[111]
  PIN o1[112]
    DIRECTION OUTPUT ;
    USE SIGNAL ;
    PORT
      LAYER M4 ;
        RECT  21.408 47.712 21.6 47.736 ;
    END
  END o1[112]
  PIN o1[113]
    DIRECTION OUTPUT ;
    USE SIGNAL ;
    PORT
      LAYER M4 ;
        RECT  21.408 47.856 21.6 47.88 ;
    END
  END o1[113]
  PIN o1[114]
    DIRECTION OUTPUT ;
    USE SIGNAL ;
    PORT
      LAYER M4 ;
        RECT  21.408 48.048 21.6 48.072 ;
    END
  END o1[114]
  PIN o1[115]
    DIRECTION OUTPUT ;
    USE SIGNAL ;
    PORT
      LAYER M4 ;
        RECT  21.408 48.24 21.6 48.264 ;
    END
  END o1[115]
  PIN o1[116]
    DIRECTION OUTPUT ;
    USE SIGNAL ;
    PORT
      LAYER M4 ;
        RECT  21.408 48.384 21.6 48.408 ;
    END
  END o1[116]
  PIN o1[117]
    DIRECTION OUTPUT ;
    USE SIGNAL ;
    PORT
      LAYER M4 ;
        RECT  21.408 48.576 21.6 48.6 ;
    END
  END o1[117]
  PIN o1[118]
    DIRECTION OUTPUT ;
    USE SIGNAL ;
    PORT
      LAYER M4 ;
        RECT  21.408 48.72 21.6 48.744 ;
    END
  END o1[118]
  PIN o1[119]
    DIRECTION OUTPUT ;
    USE SIGNAL ;
    PORT
      LAYER M4 ;
        RECT  21.408 48.912 21.6 48.936 ;
    END
  END o1[119]
  PIN o1[11]
    DIRECTION OUTPUT ;
    USE SIGNAL ;
    PORT
      LAYER M4 ;
        RECT  21.408 30.192 21.6 30.216 ;
    END
  END o1[11]
  PIN o1[120]
    DIRECTION OUTPUT ;
    USE SIGNAL ;
    PORT
      LAYER M4 ;
        RECT  21.408 49.056 21.6 49.08 ;
    END
  END o1[120]
  PIN o1[121]
    DIRECTION OUTPUT ;
    USE SIGNAL ;
    PORT
      LAYER M4 ;
        RECT  21.408 49.248 21.6 49.272 ;
    END
  END o1[121]
  PIN o1[122]
    DIRECTION OUTPUT ;
    USE SIGNAL ;
    PORT
      LAYER M4 ;
        RECT  21.408 49.44 21.6 49.464 ;
    END
  END o1[122]
  PIN o1[123]
    DIRECTION OUTPUT ;
    USE SIGNAL ;
    PORT
      LAYER M4 ;
        RECT  21.408 49.584 21.6 49.608 ;
    END
  END o1[123]
  PIN o1[124]
    DIRECTION OUTPUT ;
    USE SIGNAL ;
    PORT
      LAYER M4 ;
        RECT  21.408 49.776 21.6 49.8 ;
    END
  END o1[124]
  PIN o1[125]
    DIRECTION OUTPUT ;
    USE SIGNAL ;
    PORT
      LAYER M4 ;
        RECT  21.408 49.92 21.6 49.944 ;
    END
  END o1[125]
  PIN o1[126]
    DIRECTION OUTPUT ;
    USE SIGNAL ;
    PORT
      LAYER M4 ;
        RECT  21.408 50.112 21.6 50.136 ;
    END
  END o1[126]
  PIN o1[127]
    DIRECTION OUTPUT ;
    USE SIGNAL ;
    PORT
      LAYER M4 ;
        RECT  21.408 50.256 21.6 50.28 ;
    END
  END o1[127]
  PIN o1[128]
    DIRECTION OUTPUT ;
    USE SIGNAL ;
    PORT
      LAYER M4 ;
        RECT  21.408 50.448 21.6 50.472 ;
    END
  END o1[128]
  PIN o1[129]
    DIRECTION OUTPUT ;
    USE SIGNAL ;
    PORT
      LAYER M4 ;
        RECT  21.408 50.64 21.6 50.664 ;
    END
  END o1[129]
  PIN o1[12]
    DIRECTION OUTPUT ;
    USE SIGNAL ;
    PORT
      LAYER M4 ;
        RECT  21.408 30.336 21.6 30.36 ;
    END
  END o1[12]
  PIN o1[130]
    DIRECTION OUTPUT ;
    USE SIGNAL ;
    PORT
      LAYER M4 ;
        RECT  21.408 50.784 21.6 50.808 ;
    END
  END o1[130]
  PIN o1[131]
    DIRECTION OUTPUT ;
    USE SIGNAL ;
    PORT
      LAYER M4 ;
        RECT  21.408 50.976 21.6 51 ;
    END
  END o1[131]
  PIN o1[132]
    DIRECTION OUTPUT ;
    USE SIGNAL ;
    PORT
      LAYER M4 ;
        RECT  21.408 51.12 21.6 51.144 ;
    END
  END o1[132]
  PIN o1[133]
    DIRECTION OUTPUT ;
    USE SIGNAL ;
    PORT
      LAYER M4 ;
        RECT  21.408 51.312 21.6 51.336 ;
    END
  END o1[133]
  PIN o1[134]
    DIRECTION OUTPUT ;
    USE SIGNAL ;
    PORT
      LAYER M4 ;
        RECT  21.408 51.504 21.6 51.528 ;
    END
  END o1[134]
  PIN o1[135]
    DIRECTION OUTPUT ;
    USE SIGNAL ;
    PORT
      LAYER M4 ;
        RECT  21.408 51.648 21.6 51.672 ;
    END
  END o1[135]
  PIN o1[13]
    DIRECTION OUTPUT ;
    USE SIGNAL ;
    PORT
      LAYER M4 ;
        RECT  21.408 30.528 21.6 30.552 ;
    END
  END o1[13]
  PIN o1[14]
    DIRECTION OUTPUT ;
    USE SIGNAL ;
    PORT
      LAYER M4 ;
        RECT  21.408 30.72 21.6 30.744 ;
    END
  END o1[14]
  PIN o1[15]
    DIRECTION OUTPUT ;
    USE SIGNAL ;
    PORT
      LAYER M4 ;
        RECT  21.408 30.864 21.6 30.888 ;
    END
  END o1[15]
  PIN o1[16]
    DIRECTION OUTPUT ;
    USE SIGNAL ;
    PORT
      LAYER M4 ;
        RECT  21.408 31.056 21.6 31.08 ;
    END
  END o1[16]
  PIN o1[17]
    DIRECTION OUTPUT ;
    USE SIGNAL ;
    PORT
      LAYER M4 ;
        RECT  21.408 31.2 21.6 31.224 ;
    END
  END o1[17]
  PIN o1[18]
    DIRECTION OUTPUT ;
    USE SIGNAL ;
    PORT
      LAYER M4 ;
        RECT  21.408 31.392 21.6 31.416 ;
    END
  END o1[18]
  PIN o1[19]
    DIRECTION OUTPUT ;
    USE SIGNAL ;
    PORT
      LAYER M4 ;
        RECT  21.408 31.536 21.6 31.56 ;
    END
  END o1[19]
  PIN o1[1]
    DIRECTION OUTPUT ;
    USE SIGNAL ;
    PORT
      LAYER M4 ;
        RECT  21.408 28.464 21.6 28.488 ;
    END
  END o1[1]
  PIN o1[20]
    DIRECTION OUTPUT ;
    USE SIGNAL ;
    PORT
      LAYER M4 ;
        RECT  21.408 31.728 21.6 31.752 ;
    END
  END o1[20]
  PIN o1[21]
    DIRECTION OUTPUT ;
    USE SIGNAL ;
    PORT
      LAYER M4 ;
        RECT  21.408 31.92 21.6 31.944 ;
    END
  END o1[21]
  PIN o1[22]
    DIRECTION OUTPUT ;
    USE SIGNAL ;
    PORT
      LAYER M4 ;
        RECT  21.408 32.064 21.6 32.088 ;
    END
  END o1[22]
  PIN o1[23]
    DIRECTION OUTPUT ;
    USE SIGNAL ;
    PORT
      LAYER M4 ;
        RECT  21.408 32.256 21.6 32.28 ;
    END
  END o1[23]
  PIN o1[24]
    DIRECTION OUTPUT ;
    USE SIGNAL ;
    PORT
      LAYER M4 ;
        RECT  21.408 32.4 21.6 32.424 ;
    END
  END o1[24]
  PIN o1[25]
    DIRECTION OUTPUT ;
    USE SIGNAL ;
    PORT
      LAYER M4 ;
        RECT  21.408 32.592 21.6 32.616 ;
    END
  END o1[25]
  PIN o1[26]
    DIRECTION OUTPUT ;
    USE SIGNAL ;
    PORT
      LAYER M4 ;
        RECT  21.408 32.736 21.6 32.76 ;
    END
  END o1[26]
  PIN o1[27]
    DIRECTION OUTPUT ;
    USE SIGNAL ;
    PORT
      LAYER M4 ;
        RECT  21.408 32.928 21.6 32.952 ;
    END
  END o1[27]
  PIN o1[28]
    DIRECTION OUTPUT ;
    USE SIGNAL ;
    PORT
      LAYER M4 ;
        RECT  21.408 33.12 21.6 33.144 ;
    END
  END o1[28]
  PIN o1[29]
    DIRECTION OUTPUT ;
    USE SIGNAL ;
    PORT
      LAYER M4 ;
        RECT  21.408 33.264 21.6 33.288 ;
    END
  END o1[29]
  PIN o1[2]
    DIRECTION OUTPUT ;
    USE SIGNAL ;
    PORT
      LAYER M4 ;
        RECT  21.408 28.656 21.6 28.68 ;
    END
  END o1[2]
  PIN o1[30]
    DIRECTION OUTPUT ;
    USE SIGNAL ;
    PORT
      LAYER M4 ;
        RECT  21.408 33.456 21.6 33.48 ;
    END
  END o1[30]
  PIN o1[31]
    DIRECTION OUTPUT ;
    USE SIGNAL ;
    PORT
      LAYER M4 ;
        RECT  21.408 33.6 21.6 33.624 ;
    END
  END o1[31]
  PIN o1[32]
    DIRECTION OUTPUT ;
    USE SIGNAL ;
    PORT
      LAYER M4 ;
        RECT  21.408 33.792 21.6 33.816 ;
    END
  END o1[32]
  PIN o1[33]
    DIRECTION OUTPUT ;
    USE SIGNAL ;
    PORT
      LAYER M4 ;
        RECT  21.408 33.984 21.6 34.008 ;
    END
  END o1[33]
  PIN o1[34]
    DIRECTION OUTPUT ;
    USE SIGNAL ;
    PORT
      LAYER M4 ;
        RECT  21.408 34.128 21.6 34.152 ;
    END
  END o1[34]
  PIN o1[35]
    DIRECTION OUTPUT ;
    USE SIGNAL ;
    PORT
      LAYER M4 ;
        RECT  21.408 34.32 21.6 34.344 ;
    END
  END o1[35]
  PIN o1[36]
    DIRECTION OUTPUT ;
    USE SIGNAL ;
    PORT
      LAYER M4 ;
        RECT  21.408 34.464 21.6 34.488 ;
    END
  END o1[36]
  PIN o1[37]
    DIRECTION OUTPUT ;
    USE SIGNAL ;
    PORT
      LAYER M4 ;
        RECT  21.408 34.656 21.6 34.68 ;
    END
  END o1[37]
  PIN o1[38]
    DIRECTION OUTPUT ;
    USE SIGNAL ;
    PORT
      LAYER M4 ;
        RECT  21.408 34.8 21.6 34.824 ;
    END
  END o1[38]
  PIN o1[39]
    DIRECTION OUTPUT ;
    USE SIGNAL ;
    PORT
      LAYER M4 ;
        RECT  21.408 34.992 21.6 35.016 ;
    END
  END o1[39]
  PIN o1[3]
    DIRECTION OUTPUT ;
    USE SIGNAL ;
    PORT
      LAYER M4 ;
        RECT  21.408 28.8 21.6 28.824 ;
    END
  END o1[3]
  PIN o1[40]
    DIRECTION OUTPUT ;
    USE SIGNAL ;
    PORT
      LAYER M4 ;
        RECT  21.408 35.184 21.6 35.208 ;
    END
  END o1[40]
  PIN o1[41]
    DIRECTION OUTPUT ;
    USE SIGNAL ;
    PORT
      LAYER M4 ;
        RECT  21.408 35.328 21.6 35.352 ;
    END
  END o1[41]
  PIN o1[42]
    DIRECTION OUTPUT ;
    USE SIGNAL ;
    PORT
      LAYER M4 ;
        RECT  21.408 35.52 21.6 35.544 ;
    END
  END o1[42]
  PIN o1[43]
    DIRECTION OUTPUT ;
    USE SIGNAL ;
    PORT
      LAYER M4 ;
        RECT  21.408 35.664 21.6 35.688 ;
    END
  END o1[43]
  PIN o1[44]
    DIRECTION OUTPUT ;
    USE SIGNAL ;
    PORT
      LAYER M4 ;
        RECT  21.408 35.856 21.6 35.88 ;
    END
  END o1[44]
  PIN o1[45]
    DIRECTION OUTPUT ;
    USE SIGNAL ;
    PORT
      LAYER M4 ;
        RECT  21.408 36 21.6 36.024 ;
    END
  END o1[45]
  PIN o1[46]
    DIRECTION OUTPUT ;
    USE SIGNAL ;
    PORT
      LAYER M4 ;
        RECT  21.408 36.192 21.6 36.216 ;
    END
  END o1[46]
  PIN o1[47]
    DIRECTION OUTPUT ;
    USE SIGNAL ;
    PORT
      LAYER M4 ;
        RECT  21.408 36.384 21.6 36.408 ;
    END
  END o1[47]
  PIN o1[48]
    DIRECTION OUTPUT ;
    USE SIGNAL ;
    PORT
      LAYER M4 ;
        RECT  21.408 36.528 21.6 36.552 ;
    END
  END o1[48]
  PIN o1[49]
    DIRECTION OUTPUT ;
    USE SIGNAL ;
    PORT
      LAYER M4 ;
        RECT  21.408 36.72 21.6 36.744 ;
    END
  END o1[49]
  PIN o1[4]
    DIRECTION OUTPUT ;
    USE SIGNAL ;
    PORT
      LAYER M4 ;
        RECT  21.408 28.992 21.6 29.016 ;
    END
  END o1[4]
  PIN o1[50]
    DIRECTION OUTPUT ;
    USE SIGNAL ;
    PORT
      LAYER M4 ;
        RECT  21.408 36.864 21.6 36.888 ;
    END
  END o1[50]
  PIN o1[51]
    DIRECTION OUTPUT ;
    USE SIGNAL ;
    PORT
      LAYER M4 ;
        RECT  21.408 37.056 21.6 37.08 ;
    END
  END o1[51]
  PIN o1[52]
    DIRECTION OUTPUT ;
    USE SIGNAL ;
    PORT
      LAYER M4 ;
        RECT  21.408 37.2 21.6 37.224 ;
    END
  END o1[52]
  PIN o1[53]
    DIRECTION OUTPUT ;
    USE SIGNAL ;
    PORT
      LAYER M4 ;
        RECT  21.408 37.392 21.6 37.416 ;
    END
  END o1[53]
  PIN o1[54]
    DIRECTION OUTPUT ;
    USE SIGNAL ;
    PORT
      LAYER M4 ;
        RECT  21.408 37.584 21.6 37.608 ;
    END
  END o1[54]
  PIN o1[55]
    DIRECTION OUTPUT ;
    USE SIGNAL ;
    PORT
      LAYER M4 ;
        RECT  21.408 37.728 21.6 37.752 ;
    END
  END o1[55]
  PIN o1[56]
    DIRECTION OUTPUT ;
    USE SIGNAL ;
    PORT
      LAYER M4 ;
        RECT  21.408 37.92 21.6 37.944 ;
    END
  END o1[56]
  PIN o1[57]
    DIRECTION OUTPUT ;
    USE SIGNAL ;
    PORT
      LAYER M4 ;
        RECT  21.408 38.064 21.6 38.088 ;
    END
  END o1[57]
  PIN o1[58]
    DIRECTION OUTPUT ;
    USE SIGNAL ;
    PORT
      LAYER M4 ;
        RECT  21.408 38.256 21.6 38.28 ;
    END
  END o1[58]
  PIN o1[59]
    DIRECTION OUTPUT ;
    USE SIGNAL ;
    PORT
      LAYER M4 ;
        RECT  21.408 38.448 21.6 38.472 ;
    END
  END o1[59]
  PIN o1[5]
    DIRECTION OUTPUT ;
    USE SIGNAL ;
    PORT
      LAYER M4 ;
        RECT  21.408 29.136 21.6 29.16 ;
    END
  END o1[5]
  PIN o1[60]
    DIRECTION OUTPUT ;
    USE SIGNAL ;
    PORT
      LAYER M4 ;
        RECT  21.408 38.592 21.6 38.616 ;
    END
  END o1[60]
  PIN o1[61]
    DIRECTION OUTPUT ;
    USE SIGNAL ;
    PORT
      LAYER M4 ;
        RECT  21.408 38.784 21.6 38.808 ;
    END
  END o1[61]
  PIN o1[62]
    DIRECTION OUTPUT ;
    USE SIGNAL ;
    PORT
      LAYER M4 ;
        RECT  21.408 38.928 21.6 38.952 ;
    END
  END o1[62]
  PIN o1[63]
    DIRECTION OUTPUT ;
    USE SIGNAL ;
    PORT
      LAYER M4 ;
        RECT  21.408 39.12 21.6 39.144 ;
    END
  END o1[63]
  PIN o1[64]
    DIRECTION OUTPUT ;
    USE SIGNAL ;
    PORT
      LAYER M4 ;
        RECT  21.408 39.264 21.6 39.288 ;
    END
  END o1[64]
  PIN o1[65]
    DIRECTION OUTPUT ;
    USE SIGNAL ;
    PORT
      LAYER M4 ;
        RECT  21.408 39.456 21.6 39.48 ;
    END
  END o1[65]
  PIN o1[66]
    DIRECTION OUTPUT ;
    USE SIGNAL ;
    PORT
      LAYER M4 ;
        RECT  21.408 39.648 21.6 39.672 ;
    END
  END o1[66]
  PIN o1[67]
    DIRECTION OUTPUT ;
    USE SIGNAL ;
    PORT
      LAYER M4 ;
        RECT  21.408 39.792 21.6 39.816 ;
    END
  END o1[67]
  PIN o1[68]
    DIRECTION OUTPUT ;
    USE SIGNAL ;
    PORT
      LAYER M4 ;
        RECT  21.408 40.128 21.6 40.152 ;
    END
  END o1[68]
  PIN o1[69]
    DIRECTION OUTPUT ;
    USE SIGNAL ;
    PORT
      LAYER M4 ;
        RECT  21.408 40.32 21.6 40.344 ;
    END
  END o1[69]
  PIN o1[6]
    DIRECTION OUTPUT ;
    USE SIGNAL ;
    PORT
      LAYER M4 ;
        RECT  21.408 29.328 21.6 29.352 ;
    END
  END o1[6]
  PIN o1[70]
    DIRECTION OUTPUT ;
    USE SIGNAL ;
    PORT
      LAYER M4 ;
        RECT  21.408 40.464 21.6 40.488 ;
    END
  END o1[70]
  PIN o1[71]
    DIRECTION OUTPUT ;
    USE SIGNAL ;
    PORT
      LAYER M4 ;
        RECT  21.408 40.656 21.6 40.68 ;
    END
  END o1[71]
  PIN o1[72]
    DIRECTION OUTPUT ;
    USE SIGNAL ;
    PORT
      LAYER M4 ;
        RECT  21.408 40.848 21.6 40.872 ;
    END
  END o1[72]
  PIN o1[73]
    DIRECTION OUTPUT ;
    USE SIGNAL ;
    PORT
      LAYER M4 ;
        RECT  21.408 40.992 21.6 41.016 ;
    END
  END o1[73]
  PIN o1[74]
    DIRECTION OUTPUT ;
    USE SIGNAL ;
    PORT
      LAYER M4 ;
        RECT  21.408 41.184 21.6 41.208 ;
    END
  END o1[74]
  PIN o1[75]
    DIRECTION OUTPUT ;
    USE SIGNAL ;
    PORT
      LAYER M4 ;
        RECT  21.408 41.328 21.6 41.352 ;
    END
  END o1[75]
  PIN o1[76]
    DIRECTION OUTPUT ;
    USE SIGNAL ;
    PORT
      LAYER M4 ;
        RECT  21.408 41.52 21.6 41.544 ;
    END
  END o1[76]
  PIN o1[77]
    DIRECTION OUTPUT ;
    USE SIGNAL ;
    PORT
      LAYER M4 ;
        RECT  21.408 41.712 21.6 41.736 ;
    END
  END o1[77]
  PIN o1[78]
    DIRECTION OUTPUT ;
    USE SIGNAL ;
    PORT
      LAYER M4 ;
        RECT  21.408 41.856 21.6 41.88 ;
    END
  END o1[78]
  PIN o1[79]
    DIRECTION OUTPUT ;
    USE SIGNAL ;
    PORT
      LAYER M4 ;
        RECT  21.408 42.048 21.6 42.072 ;
    END
  END o1[79]
  PIN o1[7]
    DIRECTION OUTPUT ;
    USE SIGNAL ;
    PORT
      LAYER M4 ;
        RECT  21.408 29.472 21.6 29.496 ;
    END
  END o1[7]
  PIN o1[80]
    DIRECTION OUTPUT ;
    USE SIGNAL ;
    PORT
      LAYER M4 ;
        RECT  21.408 42.192 21.6 42.216 ;
    END
  END o1[80]
  PIN o1[81]
    DIRECTION OUTPUT ;
    USE SIGNAL ;
    PORT
      LAYER M4 ;
        RECT  21.408 42.384 21.6 42.408 ;
    END
  END o1[81]
  PIN o1[82]
    DIRECTION OUTPUT ;
    USE SIGNAL ;
    PORT
      LAYER M4 ;
        RECT  21.408 42.528 21.6 42.552 ;
    END
  END o1[82]
  PIN o1[83]
    DIRECTION OUTPUT ;
    USE SIGNAL ;
    PORT
      LAYER M4 ;
        RECT  21.408 42.72 21.6 42.744 ;
    END
  END o1[83]
  PIN o1[84]
    DIRECTION OUTPUT ;
    USE SIGNAL ;
    PORT
      LAYER M4 ;
        RECT  21.408 42.912 21.6 42.936 ;
    END
  END o1[84]
  PIN o1[85]
    DIRECTION OUTPUT ;
    USE SIGNAL ;
    PORT
      LAYER M4 ;
        RECT  21.408 43.056 21.6 43.08 ;
    END
  END o1[85]
  PIN o1[86]
    DIRECTION OUTPUT ;
    USE SIGNAL ;
    PORT
      LAYER M4 ;
        RECT  21.408 43.248 21.6 43.272 ;
    END
  END o1[86]
  PIN o1[87]
    DIRECTION OUTPUT ;
    USE SIGNAL ;
    PORT
      LAYER M4 ;
        RECT  21.408 43.392 21.6 43.416 ;
    END
  END o1[87]
  PIN o1[88]
    DIRECTION OUTPUT ;
    USE SIGNAL ;
    PORT
      LAYER M4 ;
        RECT  21.408 43.584 21.6 43.608 ;
    END
  END o1[88]
  PIN o1[89]
    DIRECTION OUTPUT ;
    USE SIGNAL ;
    PORT
      LAYER M4 ;
        RECT  21.408 43.728 21.6 43.752 ;
    END
  END o1[89]
  PIN o1[8]
    DIRECTION OUTPUT ;
    USE SIGNAL ;
    PORT
      LAYER M4 ;
        RECT  21.408 29.664 21.6 29.688 ;
    END
  END o1[8]
  PIN o1[90]
    DIRECTION OUTPUT ;
    USE SIGNAL ;
    PORT
      LAYER M4 ;
        RECT  21.408 43.92 21.6 43.944 ;
    END
  END o1[90]
  PIN o1[91]
    DIRECTION OUTPUT ;
    USE SIGNAL ;
    PORT
      LAYER M4 ;
        RECT  21.408 44.112 21.6 44.136 ;
    END
  END o1[91]
  PIN o1[92]
    DIRECTION OUTPUT ;
    USE SIGNAL ;
    PORT
      LAYER M4 ;
        RECT  21.408 44.256 21.6 44.28 ;
    END
  END o1[92]
  PIN o1[93]
    DIRECTION OUTPUT ;
    USE SIGNAL ;
    PORT
      LAYER M4 ;
        RECT  21.408 44.448 21.6 44.472 ;
    END
  END o1[93]
  PIN o1[94]
    DIRECTION OUTPUT ;
    USE SIGNAL ;
    PORT
      LAYER M4 ;
        RECT  21.408 44.592 21.6 44.616 ;
    END
  END o1[94]
  PIN o1[95]
    DIRECTION OUTPUT ;
    USE SIGNAL ;
    PORT
      LAYER M4 ;
        RECT  21.408 44.784 21.6 44.808 ;
    END
  END o1[95]
  PIN o1[96]
    DIRECTION OUTPUT ;
    USE SIGNAL ;
    PORT
      LAYER M4 ;
        RECT  21.408 44.976 21.6 45 ;
    END
  END o1[96]
  PIN o1[97]
    DIRECTION OUTPUT ;
    USE SIGNAL ;
    PORT
      LAYER M4 ;
        RECT  21.408 45.12 21.6 45.144 ;
    END
  END o1[97]
  PIN o1[98]
    DIRECTION OUTPUT ;
    USE SIGNAL ;
    PORT
      LAYER M4 ;
        RECT  21.408 45.312 21.6 45.336 ;
    END
  END o1[98]
  PIN o1[99]
    DIRECTION OUTPUT ;
    USE SIGNAL ;
    PORT
      LAYER M4 ;
        RECT  21.408 45.456 21.6 45.48 ;
    END
  END o1[99]
  PIN o1[9]
    DIRECTION OUTPUT ;
    USE SIGNAL ;
    PORT
      LAYER M4 ;
        RECT  21.408 29.856 21.6 29.88 ;
    END
  END o1[9]
  PIN rs
    DIRECTION INPUT ;
    USE SIGNAL ;
    PORT
      LAYER M5 ;
        RECT  10.8 0 10.824 0.192 ;
    END
    PORT
      LAYER M5 ;
        RECT  10.8 0.144 10.824 1.763 ;
    END
  END rs
  PIN VDD
    DIRECTION INOUT ;
    USE POWER ;
    PORT
      LAYER M5 ;
        RECT  18.792 2.151 18.912 54.009 ;
        RECT  16.092 2.151 16.212 54.009 ;
        RECT  13.392 2.151 13.512 54.009 ;
        RECT  10.692 2.151 10.812 54.009 ;
        RECT  7.992 2.151 8.112 54.009 ;
        RECT  5.292 2.151 5.412 54.009 ;
        RECT  2.592 2.151 2.712 54.009 ;
    END
  END VDD
  PIN VSS
    DIRECTION INOUT ;
    USE GROUND ;
    PORT
      LAYER M5 ;
        RECT  18.6 2.137 18.72 54.023 ;
        RECT  15.9 2.137 16.02 54.023 ;
        RECT  13.2 2.137 13.32 54.023 ;
        RECT  10.5 2.137 10.62 54.023 ;
        RECT  7.8 2.137 7.92 54.023 ;
        RECT  5.1 2.137 5.22 54.023 ;
        RECT  2.4 2.137 2.52 54.023 ;
    END
  END VSS
  # OT_OBS_CLOSED layer=M5 d_um=1.536 added=28
  OBS
    LAYER RVTN ;
     RECT  2.16 2.16 19.44 2.295 ;
     RECT  2.16 2.565 19.44 2.835 ;
     RECT  2.16 3.105 19.44 3.375 ;
     RECT  2.16 3.645 19.44 3.915 ;
     RECT  2.16 4.185 19.44 4.455 ;
     RECT  2.16 4.725 19.44 4.995 ;
     RECT  2.16 5.265 19.44 5.535 ;
     RECT  2.16 5.805 19.44 6.075 ;
     RECT  2.16 6.345 19.44 6.615 ;
     RECT  2.16 6.885 19.44 7.155 ;
     RECT  2.16 7.425 19.44 7.695 ;
     RECT  2.16 7.965 19.44 8.235 ;
     RECT  2.16 8.505 19.44 8.775 ;
     RECT  2.16 9.045 19.44 9.315 ;
     RECT  2.16 9.585 19.44 9.855 ;
     RECT  2.16 10.125 19.44 10.395 ;
     RECT  2.16 10.665 19.44 10.935 ;
     RECT  2.16 11.205 19.44 11.475 ;
     RECT  2.16 11.745 19.44 12.015 ;
     RECT  2.16 12.285 19.44 12.555 ;
     RECT  2.16 12.825 19.44 13.095 ;
     RECT  2.16 13.365 19.44 13.635 ;
     RECT  2.16 13.905 19.44 14.175 ;
     RECT  2.16 14.445 19.44 14.715 ;
     RECT  2.16 14.985 19.44 15.255 ;
     RECT  2.16 15.525 19.44 15.795 ;
     RECT  2.16 16.065 19.44 16.335 ;
     RECT  2.16 16.605 19.44 16.875 ;
     RECT  2.16 17.145 19.44 17.415 ;
     RECT  2.16 17.685 19.44 17.955 ;
     RECT  2.16 18.225 19.44 18.495 ;
     RECT  2.16 18.765 19.44 19.035 ;
     RECT  2.16 19.305 19.44 19.575 ;
     RECT  2.16 19.845 19.44 20.115 ;
     RECT  2.16 20.385 19.44 20.655 ;
     RECT  2.16 20.925 19.44 21.195 ;
     RECT  2.16 21.465 19.44 21.735 ;
     RECT  2.16 22.005 19.44 22.275 ;
     RECT  2.16 22.545 19.44 22.815 ;
     RECT  2.16 23.085 19.44 23.355 ;
     RECT  2.16 23.625 19.44 23.895 ;
     RECT  2.16 24.165 19.44 24.435 ;
     RECT  2.16 24.705 19.44 24.975 ;
     RECT  2.16 25.245 19.44 25.515 ;
     RECT  2.16 25.785 19.44 26.055 ;
     RECT  2.16 26.325 19.44 26.595 ;
     RECT  2.16 26.865 19.44 27.135 ;
     RECT  2.16 27.405 19.44 27.675 ;
     RECT  2.16 27.945 19.44 28.215 ;
     RECT  2.16 28.485 19.44 28.755 ;
     RECT  2.16 29.025 19.44 29.295 ;
     RECT  2.16 29.565 19.44 29.835 ;
     RECT  2.16 30.105 19.44 30.375 ;
     RECT  2.16 30.645 19.44 30.915 ;
     RECT  2.16 31.185 19.44 31.455 ;
     RECT  2.16 31.725 19.44 31.995 ;
     RECT  2.16 32.265 19.44 32.535 ;
     RECT  2.16 32.805 19.44 33.075 ;
     RECT  2.16 33.345 19.44 33.615 ;
     RECT  2.16 33.885 19.44 34.155 ;
     RECT  2.16 34.425 19.44 34.695 ;
     RECT  2.16 34.965 19.44 35.235 ;
     RECT  2.16 35.505 19.44 35.775 ;
     RECT  2.16 36.045 19.44 36.315 ;
     RECT  2.16 36.585 19.44 36.855 ;
     RECT  2.16 37.125 19.44 37.395 ;
     RECT  2.16 37.665 19.44 37.935 ;
     RECT  2.16 38.205 19.44 38.475 ;
     RECT  2.16 38.745 19.44 39.015 ;
     RECT  2.16 39.285 19.44 39.555 ;
     RECT  2.16 39.825 19.44 40.095 ;
     RECT  2.16 40.365 19.44 40.635 ;
     RECT  2.16 40.905 19.44 41.175 ;
     RECT  2.16 41.445 19.44 41.715 ;
     RECT  2.16 41.985 19.44 42.255 ;
     RECT  2.16 42.525 19.44 42.795 ;
     RECT  2.16 43.065 19.44 43.335 ;
     RECT  2.16 43.605 19.44 43.875 ;
     RECT  2.16 44.145 19.44 44.415 ;
     RECT  2.16 44.685 19.44 44.955 ;
     RECT  2.16 45.225 19.44 45.495 ;
     RECT  2.16 45.765 19.44 46.035 ;
     RECT  2.16 46.305 19.44 46.575 ;
     RECT  2.16 46.845 19.44 47.115 ;
     RECT  2.16 47.385 19.44 47.655 ;
     RECT  2.16 47.925 19.44 48.195 ;
     RECT  2.16 48.465 19.44 48.735 ;
     RECT  2.16 49.005 19.44 49.275 ;
     RECT  2.16 49.545 19.44 49.815 ;
     RECT  2.16 50.085 19.44 50.355 ;
     RECT  2.16 50.625 19.44 50.895 ;
     RECT  2.16 51.165 19.44 51.435 ;
     RECT  2.16 51.705 19.44 51.975 ;
     RECT  2.16 52.245 19.44 52.515 ;
     RECT  2.16 52.785 19.44 53.055 ;
     RECT  2.16 53.325 19.44 53.595 ;
     RECT  2.16 53.865 19.44 54 ;
    LAYER RVTP ;
     RECT  2.16 2.295 19.44 2.565 ;
     RECT  2.16 2.835 19.44 3.105 ;
     RECT  2.16 3.375 19.44 3.645 ;
     RECT  2.16 3.915 19.44 4.185 ;
     RECT  2.16 4.455 19.44 4.725 ;
     RECT  2.16 4.995 19.44 5.265 ;
     RECT  2.16 5.535 19.44 5.805 ;
     RECT  2.16 6.075 19.44 6.345 ;
     RECT  2.16 6.615 19.44 6.885 ;
     RECT  2.16 7.155 19.44 7.425 ;
     RECT  2.16 7.695 19.44 7.965 ;
     RECT  2.16 8.235 19.44 8.505 ;
     RECT  2.16 8.775 19.44 9.045 ;
     RECT  2.16 9.315 19.44 9.585 ;
     RECT  2.16 9.855 19.44 10.125 ;
     RECT  2.16 10.395 19.44 10.665 ;
     RECT  2.16 10.935 19.44 11.205 ;
     RECT  2.16 11.475 19.44 11.745 ;
     RECT  2.16 12.015 19.44 12.285 ;
     RECT  2.16 12.555 19.44 12.825 ;
     RECT  2.16 13.095 19.44 13.365 ;
     RECT  2.16 13.635 19.44 13.905 ;
     RECT  2.16 14.175 19.44 14.445 ;
     RECT  2.16 14.715 19.44 14.985 ;
     RECT  2.16 15.255 19.44 15.525 ;
     RECT  2.16 15.795 19.44 16.065 ;
     RECT  2.16 16.335 19.44 16.605 ;
     RECT  2.16 16.875 19.44 17.145 ;
     RECT  2.16 17.415 19.44 17.685 ;
     RECT  2.16 17.955 19.44 18.225 ;
     RECT  2.16 18.495 19.44 18.765 ;
     RECT  2.16 19.035 19.44 19.305 ;
     RECT  2.16 19.575 19.44 19.845 ;
     RECT  2.16 20.115 19.44 20.385 ;
     RECT  2.16 20.655 19.44 20.925 ;
     RECT  2.16 21.195 19.44 21.465 ;
     RECT  2.16 21.735 19.44 22.005 ;
     RECT  2.16 22.275 19.44 22.545 ;
     RECT  2.16 22.815 19.44 23.085 ;
     RECT  2.16 23.355 19.44 23.625 ;
     RECT  2.16 23.895 19.44 24.165 ;
     RECT  2.16 24.435 19.44 24.705 ;
     RECT  2.16 24.975 19.44 25.245 ;
     RECT  2.16 25.515 19.44 25.785 ;
     RECT  2.16 26.055 19.44 26.325 ;
     RECT  2.16 26.595 19.44 26.865 ;
     RECT  2.16 27.135 19.44 27.405 ;
     RECT  2.16 27.675 19.44 27.945 ;
     RECT  2.16 28.215 19.44 28.485 ;
     RECT  2.16 28.755 19.44 29.025 ;
     RECT  2.16 29.295 19.44 29.565 ;
     RECT  2.16 29.835 19.44 30.105 ;
     RECT  2.16 30.375 19.44 30.645 ;
     RECT  2.16 30.915 19.44 31.185 ;
     RECT  2.16 31.455 19.44 31.725 ;
     RECT  2.16 31.995 19.44 32.265 ;
     RECT  2.16 32.535 19.44 32.805 ;
     RECT  2.16 33.075 19.44 33.345 ;
     RECT  2.16 33.615 19.44 33.885 ;
     RECT  2.16 34.155 19.44 34.425 ;
     RECT  2.16 34.695 19.44 34.965 ;
     RECT  2.16 35.235 19.44 35.505 ;
     RECT  2.16 35.775 19.44 36.045 ;
     RECT  2.16 36.315 19.44 36.585 ;
     RECT  2.16 36.855 19.44 37.125 ;
     RECT  2.16 37.395 19.44 37.665 ;
     RECT  2.16 37.935 19.44 38.205 ;
     RECT  2.16 38.475 19.44 38.745 ;
     RECT  2.16 39.015 19.44 39.285 ;
     RECT  2.16 39.555 19.44 39.825 ;
     RECT  2.16 40.095 19.44 40.365 ;
     RECT  2.16 40.635 19.44 40.905 ;
     RECT  2.16 41.175 19.44 41.445 ;
     RECT  2.16 41.715 19.44 41.985 ;
     RECT  2.16 42.255 19.44 42.525 ;
     RECT  2.16 42.795 19.44 43.065 ;
     RECT  2.16 43.335 19.44 43.605 ;
     RECT  2.16 43.875 19.44 44.145 ;
     RECT  2.16 44.415 19.44 44.685 ;
     RECT  2.16 44.955 19.44 45.225 ;
     RECT  2.16 45.495 19.44 45.765 ;
     RECT  2.16 46.035 19.44 46.305 ;
     RECT  2.16 46.575 19.44 46.845 ;
     RECT  2.16 47.115 19.44 47.385 ;
     RECT  2.16 47.655 19.44 47.925 ;
     RECT  2.16 48.195 19.44 48.465 ;
     RECT  2.16 48.735 19.44 49.005 ;
     RECT  2.16 49.275 19.44 49.545 ;
     RECT  2.16 49.815 19.44 50.085 ;
     RECT  2.16 50.355 19.44 50.625 ;
     RECT  2.16 50.895 19.44 51.165 ;
     RECT  2.16 51.435 19.44 51.705 ;
     RECT  2.16 51.975 19.44 52.245 ;
     RECT  2.16 52.515 19.44 52.785 ;
     RECT  2.16 53.055 19.44 53.325 ;
     RECT  2.16 53.595 19.44 53.865 ;
    LAYER M1 ;
     RECT  2.16 2.151 19.44 54.009 ;
    LAYER M2 ;
     RECT  0.211 3.96 2.16 3.978 ;
     RECT  0.211 23.67 2.16 23.688 ;
     RECT  0.211 39.294 2.16 39.888 ;
     RECT  0.211 47.862 2.16 48.456 ;
     RECT  0.211 49.554 2.16 49.572 ;
     RECT  0.211 50.4 2.16 50.418 ;
     RECT  2.16 2.151 19.44 54.009 ;
     RECT  19.44 39.186 19.463 52.164 ;
     RECT  19.44 37.602 19.607 38.394 ;
     RECT  19.44 17.586 19.643 18.216 ;
     RECT  19.44 29.34 19.715 34.074 ;
     RECT  19.44 20.466 19.751 21.654 ;
     RECT  19.44 24.372 19.751 27.864 ;
     RECT  19.44 19.656 19.823 19.674 ;
     RECT  19.44 35.136 19.895 35.424 ;
     RECT  19.751 21.276 19.931 21.654 ;
     RECT  19.44 4.536 19.967 11.736 ;
     RECT  19.44 12.492 19.967 16.434 ;
     RECT  19.715 29.34 19.967 30.834 ;
     RECT  19.463 39.186 19.967 39.474 ;
     RECT  19.463 40.536 19.967 52.164 ;
     RECT  19.967 12.762 20.003 16.434 ;
     RECT  19.967 41.994 20.003 44.442 ;
     RECT  19.751 25.101 20.147 27.864 ;
     RECT  19.715 31.662 20.147 34.074 ;
     RECT  19.967 29.34 20.183 30.474 ;
     RECT  19.607 38.376 20.219 38.394 ;
     RECT  19.967 40.536 20.255 41.238 ;
     RECT  19.967 39.186 20.291 39.204 ;
     RECT  20.003 13.266 20.327 16.434 ;
     RECT  20.147 31.662 20.327 32.292 ;
     RECT  20.147 33.588 20.363 34.074 ;
     RECT  19.895 35.136 20.399 35.154 ;
     RECT  19.931 21.276 20.435 21.294 ;
     RECT  19.751 20.466 20.471 20.484 ;
     RECT  20.363 33.588 20.471 33.606 ;
     RECT  19.967 50.634 20.471 52.164 ;
     RECT  19.967 4.536 20.507 10.584 ;
     RECT  20.327 13.266 20.507 15.624 ;
     RECT  19.643 17.586 20.507 17.604 ;
     RECT  20.407 18.774 20.507 18.792 ;
     RECT  20.407 22.896 20.507 22.914 ;
     RECT  20.327 31.662 20.507 31.68 ;
     RECT  20.471 50.634 20.507 51.894 ;
     RECT  20.507 4.536 20.543 4.554 ;
     RECT  20.507 6.156 20.543 6.174 ;
     RECT  20.507 6.966 20.543 6.984 ;
     RECT  20.507 7.776 20.543 10.044 ;
     RECT  19.967 11.448 20.543 11.736 ;
     RECT  20.507 13.338 20.543 15.624 ;
     RECT  20.147 25.326 20.543 27.864 ;
     RECT  20.183 29.34 20.543 29.898 ;
     RECT  20.255 40.608 20.543 41.238 ;
     RECT  20.003 41.994 20.543 42.984 ;
     RECT  20.003 43.956 20.543 44.442 ;
     RECT  19.967 45.576 20.543 49.572 ;
     RECT  20.507 50.634 20.543 50.652 ;
     RECT  20.543 8.316 20.579 8.334 ;
     RECT  20.543 9.666 20.579 9.684 ;
     RECT  20.543 14.796 20.579 15.516 ;
     RECT  20.543 25.326 20.579 26.694 ;
     RECT  20.543 41.148 20.579 41.166 ;
     RECT  20.543 42.066 20.579 42.984 ;
     RECT  20.543 44.226 20.579 44.244 ;
     RECT  20.543 46.584 20.579 46.872 ;
     RECT  20.543 47.664 20.579 48.024 ;
     RECT  20.327 16.416 20.615 16.434 ;
     RECT  20.543 29.376 20.615 29.754 ;
     RECT  20.579 42.066 20.615 42.174 ;
     RECT  20.579 42.966 20.615 42.984 ;
     RECT  20.579 46.854 20.615 46.872 ;
     RECT  20.579 48.006 20.615 48.024 ;
     RECT  20.615 42.156 20.651 42.174 ;
     RECT  20.615 29.574 21.263 29.754 ;
     RECT  19.44 36.828 21.263 36.846 ;
     RECT  20.543 27.756 21.299 27.864 ;
     RECT  21.235 34.128 21.307 34.146 ;
     RECT  20.579 25.686 21.335 26.694 ;
     RECT  21.307 34.056 21.335 34.146 ;
     RECT  21.263 29.736 21.371 29.754 ;
     RECT  21.271 31.806 21.371 31.824 ;
     RECT  21.335 34.056 21.379 34.074 ;
     RECT  21.335 25.686 21.407 26.514 ;
     RECT  21.299 27.846 21.407 27.864 ;
     RECT  21.379 32.931 21.407 34.074 ;
     RECT  20.543 13.338 21.443 13.356 ;
     RECT  19.607 37.602 21.443 37.62 ;
     RECT  21.379 19.971 21.479 21.024 ;
     RECT  21.379 22.446 21.479 22.464 ;
     RECT  21.379 23.796 21.479 23.814 ;
     RECT  21.407 32.931 21.479 33.984 ;
    LAYER M3 ;
     RECT  10.656 1.723 10.674 2.143 ;
     RECT  10.515 2.143 10.674 2.371 ;
     RECT  2.415 2.143 2.505 2.413 ;
     RECT  5.115 2.143 5.205 2.413 ;
     RECT  7.815 2.143 7.905 2.413 ;
     RECT  13.215 2.143 13.305 2.413 ;
     RECT  15.915 2.143 16.005 2.413 ;
     RECT  18.615 2.143 18.705 2.413 ;
     RECT  10.515 2.371 10.854 2.525 ;
     RECT  10.515 2.525 10.797 2.641 ;
     RECT  2.415 2.413 2.697 3.811 ;
     RECT  2.415 3.811 2.754 4.225 ;
     RECT  18.615 2.413 18.897 4.261 ;
     RECT  17.676 4.261 17.694 4.351 ;
     RECT  2.34 4.225 2.754 4.387 ;
     RECT  17.568 4.351 17.694 4.495 ;
     RECT  2.34 4.387 2.826 4.507 ;
     RECT  17.316 4.495 17.694 4.531 ;
     RECT  18.615 4.261 19.062 4.531 ;
     RECT  17.316 4.531 19.062 4.621 ;
     RECT  10.476 2.641 10.797 4.685 ;
     RECT  4.032 4.657 4.05 4.693 ;
     RECT  2.304 4.507 2.826 4.729 ;
     RECT  7.815 2.413 8.097 4.729 ;
     RECT  20.52 4.531 20.538 4.733 ;
     RECT  2.304 4.729 3.222 4.801 ;
     RECT  4.032 4.693 4.194 4.801 ;
     RECT  6.84 4.729 8.097 4.801 ;
     RECT  17.316 4.621 19.098 4.801 ;
     RECT  14.832 4.801 14.85 4.919 ;
     RECT  0.216 3.955 0.234 4.925 ;
     RECT  5.115 2.413 5.397 5.035 ;
     RECT  6.12 4.801 8.097 5.035 ;
     RECT  19.944 4.801 20.502 5.069 ;
     RECT  2.304 4.801 4.194 5.071 ;
     RECT  5.115 5.035 8.097 5.071 ;
     RECT  16.956 4.801 19.098 5.161 ;
     RECT  2.304 5.071 8.097 5.189 ;
     RECT  16.956 5.161 19.422 5.405 ;
     RECT  16.956 5.405 19.098 5.459 ;
     RECT  15.915 2.413 16.197 5.611 ;
     RECT  16.956 5.459 18.954 5.611 ;
     RECT  15.915 5.611 18.954 5.765 ;
     RECT  6.408 5.189 8.097 5.773 ;
     RECT  8.82 5.737 8.838 5.773 ;
     RECT  20.448 5.069 20.502 5.899 ;
     RECT  2.304 5.189 5.397 5.933 ;
     RECT  6.408 5.773 8.838 5.971 ;
     RECT  6.408 5.971 8.91 6.107 ;
     RECT  15.915 5.765 18.897 6.151 ;
     RECT  20.448 5.899 20.538 6.179 ;
     RECT  15.516 6.151 18.897 6.241 ;
     RECT  2.415 5.933 5.397 6.269 ;
     RECT  3.96 6.269 5.397 6.277 ;
     RECT  15.3 6.241 18.897 6.385 ;
     RECT  20.448 6.179 20.502 6.421 ;
     RECT  10.515 4.685 10.797 6.511 ;
     RECT  3.96 6.277 5.67 6.575 ;
     RECT  15.048 6.385 18.897 6.583 ;
     RECT  19.944 6.421 20.502 6.605 ;
     RECT  2.415 6.269 3.222 6.655 ;
     RECT  14.832 6.583 18.897 6.655 ;
     RECT  14.832 6.655 18.954 6.691 ;
     RECT  14.832 6.691 19.422 6.797 ;
     RECT  6.408 6.107 8.586 6.809 ;
     RECT  4.104 6.575 5.397 6.845 ;
     RECT  6.408 6.809 6.426 6.845 ;
     RECT  2.412 6.655 3.222 6.955 ;
     RECT  20.484 6.605 20.502 6.955 ;
     RECT  20.484 6.955 20.538 6.995 ;
     RECT  10.515 6.511 10.818 7.087 ;
     RECT  10.515 7.087 10.854 7.187 ;
     RECT  7.164 6.809 8.586 7.195 ;
     RECT  14.832 6.797 19.134 7.231 ;
     RECT  7.164 7.195 8.874 7.349 ;
     RECT  14.328 7.231 19.134 7.349 ;
     RECT  4.104 6.845 4.122 7.357 ;
     RECT  2.304 6.955 3.222 7.501 ;
     RECT  4.032 7.357 4.122 7.501 ;
     RECT  2.304 7.501 4.122 7.619 ;
     RECT  14.832 7.349 18.99 7.619 ;
     RECT  3.852 7.619 4.122 7.627 ;
     RECT  5.115 6.845 5.397 7.627 ;
     RECT  2.304 7.619 3.114 7.655 ;
     RECT  3.852 7.627 5.397 7.691 ;
     RECT  5.004 7.691 5.397 7.699 ;
     RECT  13.215 2.413 13.497 7.735 ;
     RECT  20.484 6.995 20.502 7.765 ;
     RECT  5.004 7.699 5.742 7.889 ;
     RECT  2.304 7.655 3.042 7.925 ;
     RECT  13.104 7.735 13.497 8.159 ;
     RECT  14.832 7.619 18.954 8.159 ;
     RECT  7.164 7.349 8.097 8.239 ;
     RECT  5.04 7.889 5.742 8.251 ;
     RECT  6.948 8.239 8.097 8.251 ;
     RECT  5.04 8.251 8.097 8.275 ;
     RECT  20.484 7.765 20.538 8.299 ;
     RECT  5.04 8.275 8.586 8.303 ;
     RECT  13.215 8.159 13.497 8.311 ;
     RECT  20.448 8.299 20.538 8.311 ;
     RECT  6.84 8.303 8.586 8.437 ;
     RECT  14.868 8.159 18.954 8.509 ;
     RECT  20.448 8.311 20.574 8.525 ;
     RECT  6.84 8.437 8.838 8.537 ;
     RECT  7.815 8.537 8.838 8.671 ;
     RECT  2.304 7.925 2.862 8.779 ;
     RECT  14.868 8.509 18.99 8.779 ;
     RECT  7.815 8.671 8.91 8.807 ;
     RECT  2.304 8.779 2.898 8.851 ;
     RECT  3.852 7.691 4.122 8.851 ;
     RECT  14.868 8.779 19.026 8.851 ;
     RECT  5.04 8.303 5.742 8.923 ;
     RECT  4.86 8.923 5.742 8.969 ;
     RECT  20.448 8.525 20.538 8.971 ;
     RECT  13.215 8.311 14.13 9.013 ;
     RECT  14.868 8.851 19.098 9.013 ;
     RECT  13.215 9.013 19.098 9.067 ;
     RECT  19.908 8.971 20.538 9.067 ;
     RECT  5.004 8.969 5.742 9.239 ;
     RECT  2.304 8.851 4.122 9.275 ;
     RECT  13.215 9.067 20.538 9.355 ;
     RECT  5.115 9.239 5.742 9.499 ;
     RECT  6.84 8.537 6.966 9.499 ;
     RECT  5.115 9.499 6.966 9.517 ;
     RECT  7.815 8.807 8.586 9.517 ;
     RECT  13.215 9.355 20.574 9.689 ;
     RECT  5.115 9.517 8.586 9.779 ;
     RECT  2.304 9.275 2.754 9.815 ;
     RECT  6.948 9.779 8.586 9.895 ;
     RECT  3.744 9.275 4.122 9.931 ;
     RECT  6.948 9.895 8.874 10.049 ;
     RECT  13.215 9.689 20.538 10.049 ;
     RECT  6.948 10.049 8.586 10.085 ;
     RECT  2.415 9.815 2.754 10.129 ;
     RECT  3.744 9.931 4.194 10.129 ;
     RECT  13.215 10.049 20.502 10.193 ;
     RECT  2.415 10.129 4.194 10.319 ;
     RECT  2.415 10.319 3.114 10.355 ;
     RECT  3.96 10.319 4.194 10.555 ;
     RECT  5.115 9.779 5.814 10.555 ;
     RECT  2.415 10.355 2.697 10.747 ;
     RECT  10.515 7.187 10.797 10.867 ;
     RECT  10.515 10.867 10.854 10.967 ;
     RECT  3.96 10.555 5.814 10.975 ;
     RECT  6.948 10.085 6.966 10.975 ;
     RECT  7.815 10.085 8.586 10.975 ;
     RECT  3.96 10.975 8.586 11.021 ;
     RECT  14.94 10.193 20.502 11.035 ;
     RECT  6.552 11.021 8.586 11.129 ;
     RECT  7.704 11.129 8.586 11.137 ;
     RECT  3.96 11.021 5.814 11.245 ;
     RECT  7.704 11.137 8.838 11.309 ;
     RECT  7.776 11.309 8.838 11.435 ;
     RECT  13.215 10.193 14.13 11.515 ;
     RECT  14.94 11.035 20.538 11.515 ;
     RECT  2.304 10.747 2.697 11.749 ;
     RECT  3.924 11.245 5.814 11.749 ;
     RECT  2.304 11.749 5.814 11.785 ;
     RECT  13.215 11.515 20.538 11.789 ;
     RECT  2.304 11.785 6.138 11.941 ;
     RECT  6.912 11.129 6.966 11.941 ;
     RECT  2.304 11.941 6.966 12.091 ;
     RECT  7.776 11.435 8.586 12.091 ;
     RECT  13.215 11.789 20.502 12.209 ;
     RECT  2.304 12.091 8.586 12.515 ;
     RECT  7.815 12.515 8.586 12.595 ;
     RECT  2.304 12.515 6.966 12.749 ;
     RECT  7.815 12.595 8.874 12.749 ;
     RECT  2.304 12.749 5.814 12.785 ;
     RECT  13.215 12.209 19.098 13.051 ;
     RECT  19.908 12.209 20.502 13.051 ;
     RECT  13.215 13.051 20.502 13.288 ;
     RECT  2.304 12.785 3.33 13.325 ;
     RECT  2.304 13.325 2.697 13.531 ;
     RECT  4.068 12.785 5.814 13.531 ;
     RECT  6.948 12.749 6.966 13.531 ;
     RECT  3.528 13.531 6.966 13.675 ;
     RECT  7.815 12.749 8.586 13.675 ;
     RECT  13.215 13.288 20.538 13.739 ;
     RECT  3.528 13.675 8.586 13.829 ;
     RECT  19.908 13.739 20.538 13.829 ;
     RECT  6.948 13.829 8.586 13.837 ;
     RECT  2.268 13.531 2.697 13.865 ;
     RECT  6.948 13.837 8.838 14.135 ;
     RECT  13.215 13.739 19.098 14.135 ;
     RECT  2.304 13.865 2.697 14.299 ;
     RECT  3.528 13.829 6.138 14.299 ;
     RECT  14.94 14.135 19.098 14.369 ;
     RECT  2.304 14.299 6.138 14.639 ;
     RECT  4.032 14.639 6.138 14.675 ;
     RECT  19.944 13.829 20.538 14.683 ;
     RECT  4.104 14.675 6.138 14.813 ;
     RECT  4.104 14.813 4.194 14.819 ;
     RECT  5.004 14.813 6.138 14.827 ;
     RECT  6.948 14.135 6.966 14.827 ;
     RECT  13.215 14.135 14.202 14.881 ;
     RECT  14.94 14.369 18.99 14.881 ;
     RECT  5.004 14.827 6.966 14.909 ;
     RECT  5.115 14.909 6.966 14.917 ;
     RECT  7.815 14.135 8.586 14.917 ;
     RECT  5.115 14.917 8.586 15.215 ;
     RECT  7.704 15.215 8.586 15.457 ;
     RECT  19.944 14.683 20.574 15.499 ;
     RECT  7.704 15.457 8.838 15.593 ;
     RECT  19.944 15.499 20.61 15.593 ;
     RECT  13.215 14.881 18.99 15.691 ;
     RECT  7.776 15.593 8.838 15.755 ;
     RECT  4.104 14.819 4.122 15.835 ;
     RECT  2.304 14.639 3.258 15.871 ;
     RECT  4.068 15.835 4.122 15.871 ;
     RECT  5.115 15.215 6.966 15.961 ;
     RECT  2.304 15.871 4.122 15.989 ;
     RECT  4.86 15.961 6.966 16.013 ;
     RECT  2.304 15.989 3.222 16.025 ;
     RECT  13.215 15.691 19.206 16.169 ;
     RECT  14.904 16.169 19.206 16.219 ;
     RECT  2.304 16.025 2.934 16.259 ;
     RECT  4.896 16.013 6.966 16.375 ;
     RECT  7.776 15.755 8.586 16.375 ;
     RECT  4.896 16.375 8.586 16.403 ;
     RECT  20.304 15.593 20.61 16.439 ;
     RECT  6.552 16.403 8.586 16.529 ;
     RECT  4.896 16.403 5.814 16.565 ;
     RECT  6.84 16.529 8.586 16.681 ;
     RECT  4.068 15.989 4.122 16.807 ;
     RECT  14.904 16.219 19.314 16.891 ;
     RECT  20.304 16.439 20.502 16.891 ;
     RECT  2.304 16.259 2.79 17.077 ;
     RECT  3.78 16.807 4.122 17.077 ;
     RECT  13.215 16.169 14.13 17.083 ;
     RECT  14.904 16.891 20.502 17.083 ;
     RECT  6.84 16.681 9.162 17.105 ;
     RECT  2.304 17.077 4.122 17.323 ;
     RECT  2.268 17.323 4.122 17.339 ;
     RECT  10.515 10.967 10.797 17.347 ;
     RECT  2.268 17.339 2.97 17.375 ;
     RECT  7.815 17.105 9.162 17.375 ;
     RECT  10.515 17.347 10.926 17.447 ;
     RECT  5.115 16.565 5.814 17.491 ;
     RECT  13.215 17.083 20.502 17.609 ;
     RECT  3.852 17.339 4.122 17.645 ;
     RECT  4.86 17.491 5.814 17.995 ;
     RECT  6.948 17.105 6.966 17.995 ;
     RECT  7.815 17.375 8.586 17.995 ;
     RECT  3.888 17.645 4.122 18.031 ;
     RECT  4.86 17.995 8.586 18.031 ;
     RECT  3.888 18.031 8.586 18.157 ;
     RECT  2.304 17.375 2.862 18.427 ;
     RECT  3.888 18.157 8.838 18.427 ;
     RECT  2.304 18.427 8.838 18.455 ;
     RECT  2.304 18.455 6.966 18.689 ;
     RECT  2.304 18.689 3.114 18.725 ;
     RECT  13.215 17.609 20.43 18.769 ;
     RECT  3.996 18.689 6.966 18.797 ;
     RECT  5.004 18.797 6.966 18.959 ;
     RECT  5.115 18.959 6.966 19.237 ;
     RECT  7.815 18.455 8.586 19.237 ;
     RECT  5.115 19.237 8.586 19.373 ;
     RECT  10.515 17.447 10.797 19.507 ;
     RECT  2.304 18.725 2.697 19.615 ;
     RECT  6.948 19.373 8.586 19.615 ;
     RECT  2.304 19.615 2.754 19.723 ;
     RECT  6.948 19.615 8.874 19.769 ;
     RECT  6.948 19.769 8.586 19.805 ;
     RECT  7.704 19.805 8.586 19.913 ;
     RECT  2.304 19.723 3.258 19.921 ;
     RECT  3.996 18.797 4.194 19.921 ;
     RECT  21.42 13.333 21.438 19.96 ;
     RECT  21.384 19.96 21.438 19.966 ;
     RECT  2.304 19.921 4.194 20.039 ;
     RECT  2.304 20.039 3.114 20.075 ;
     RECT  3.888 20.039 4.194 20.251 ;
     RECT  5.115 19.373 5.814 20.251 ;
     RECT  10.515 19.507 10.854 20.417 ;
     RECT  3.888 20.251 5.814 20.683 ;
     RECT  6.948 19.805 6.966 20.683 ;
     RECT  3.888 20.683 6.966 20.695 ;
     RECT  7.815 19.913 8.586 20.695 ;
     RECT  3.888 20.695 8.586 20.731 ;
     RECT  3.888 20.731 9.306 20.821 ;
     RECT  2.415 20.075 2.79 20.827 ;
     RECT  3.744 20.821 9.306 20.849 ;
     RECT  13.215 18.769 20.502 21.001 ;
     RECT  21.384 19.966 21.474 21.029 ;
     RECT  21.384 21.029 21.438 21.053 ;
     RECT  2.304 20.827 2.79 21.115 ;
     RECT  3.744 20.849 8.838 21.115 ;
     RECT  2.304 21.115 8.838 21.155 ;
     RECT  12.636 21.001 20.502 21.659 ;
     RECT  2.304 21.155 6.966 22.207 ;
     RECT  7.704 21.155 8.586 22.207 ;
     RECT  2.304 22.207 8.586 22.315 ;
     RECT  21.42 21.053 21.438 22.411 ;
     RECT  21.384 22.411 21.438 22.441 ;
     RECT  2.304 22.315 8.874 22.469 ;
     RECT  13.104 21.659 20.502 22.469 ;
     RECT  21.384 22.441 21.474 22.469 ;
     RECT  21.42 22.469 21.474 22.493 ;
     RECT  2.304 22.469 8.586 22.739 ;
     RECT  13.215 22.469 20.502 22.919 ;
     RECT  10.515 20.417 10.797 23.017 ;
     RECT  10.515 23.017 10.854 23.117 ;
     RECT  4.032 22.739 8.586 23.165 ;
     RECT  2.304 22.739 3.294 23.189 ;
     RECT  5.004 23.165 8.586 23.279 ;
     RECT  4.032 23.165 4.266 23.315 ;
     RECT  2.304 23.189 2.718 23.351 ;
     RECT  5.115 23.279 8.586 23.549 ;
     RECT  6.948 23.549 8.586 23.557 ;
     RECT  21.42 22.493 21.438 23.755 ;
     RECT  21.384 23.755 21.438 23.791 ;
     RECT  21.384 23.791 21.474 23.819 ;
     RECT  21.42 23.819 21.474 23.837 ;
     RECT  6.948 23.557 8.838 23.855 ;
     RECT  0.216 23.665 0.234 23.981 ;
     RECT  2.34 23.351 2.718 24.043 ;
     RECT  2.34 24.043 3.258 24.125 ;
     RECT  2.376 24.125 3.258 24.241 ;
     RECT  4.032 23.315 4.194 24.241 ;
     RECT  2.376 24.241 4.194 24.331 ;
     RECT  5.115 23.549 5.814 24.331 ;
     RECT  2.376 24.331 5.814 24.637 ;
     RECT  6.948 23.855 6.966 24.637 ;
     RECT  7.815 23.855 8.586 24.637 ;
     RECT  2.376 24.637 8.586 24.701 ;
     RECT  6.552 24.701 8.586 24.899 ;
     RECT  6.948 24.899 8.586 25.015 ;
     RECT  13.215 22.919 20.466 25.147 ;
     RECT  6.948 25.015 8.874 25.169 ;
     RECT  6.948 25.169 8.586 25.205 ;
     RECT  13.215 25.147 20.502 25.321 ;
     RECT  2.376 24.701 5.814 25.339 ;
     RECT  2.304 25.339 5.814 25.475 ;
     RECT  21.42 23.837 21.438 25.672 ;
     RECT  2.412 25.475 5.814 25.889 ;
     RECT  3.852 25.889 5.814 25.951 ;
     RECT  6.948 25.205 6.966 25.951 ;
     RECT  10.515 23.117 10.797 25.987 ;
     RECT  3.852 25.951 6.966 26.015 ;
     RECT  10.515 25.987 10.854 26.087 ;
     RECT  4.176 26.015 6.966 26.095 ;
     RECT  7.815 25.205 8.586 26.095 ;
     RECT  2.412 25.889 3.114 26.203 ;
     RECT  4.176 26.095 8.586 26.249 ;
     RECT  13.215 25.321 20.574 26.401 ;
     RECT  6.948 26.249 8.586 26.635 ;
     RECT  21.384 25.672 21.438 26.671 ;
     RECT  2.304 26.203 3.114 26.731 ;
     RECT  6.948 26.635 8.874 26.789 ;
     RECT  13.032 26.401 20.574 26.789 ;
     RECT  4.176 26.249 6.138 26.797 ;
     RECT  6.948 26.789 8.586 26.825 ;
     RECT  2.304 26.731 3.258 26.941 ;
     RECT  4.032 26.797 6.138 26.941 ;
     RECT  2.304 26.941 6.138 27.131 ;
     RECT  5.004 27.131 6.138 27.355 ;
     RECT  6.948 26.825 6.966 27.355 ;
     RECT  2.304 27.131 4.194 27.365 ;
     RECT  5.004 27.355 6.966 27.715 ;
     RECT  7.815 26.825 8.586 27.715 ;
     RECT  5.004 27.715 8.586 27.743 ;
     RECT  13.215 26.789 20.574 27.751 ;
     RECT  21.312 26.671 21.438 27.751 ;
     RECT  2.304 27.365 3.402 27.779 ;
     RECT  6.552 27.743 8.586 27.869 ;
     RECT  5.004 27.743 5.814 27.877 ;
     RECT  6.768 27.869 8.586 27.877 ;
     RECT  10.515 26.087 10.797 27.877 ;
     RECT  10.476 27.877 10.797 28.049 ;
     RECT  6.768 27.877 8.838 28.175 ;
     RECT  0.216 28.075 0.234 28.205 ;
     RECT  4.176 27.365 4.194 28.291 ;
     RECT  4.968 27.877 5.814 28.291 ;
     RECT  4.176 28.291 5.814 28.417 ;
     RECT  6.768 28.175 6.966 28.481 ;
     RECT  13.215 27.751 21.438 28.493 ;
     RECT  2.304 27.779 3.222 28.561 ;
     RECT  4.032 28.417 5.814 28.561 ;
     RECT  2.304 28.561 5.814 28.715 ;
     RECT  4.176 28.715 5.814 29.069 ;
     RECT  6.948 28.481 6.966 29.101 ;
     RECT  7.815 28.175 8.586 29.101 ;
     RECT  5.004 29.069 5.814 29.219 ;
     RECT  4.176 29.069 4.266 29.255 ;
     RECT  13.215 28.493 20.502 29.323 ;
     RECT  5.115 29.219 5.814 29.335 ;
     RECT  6.948 29.101 8.586 29.335 ;
     RECT  13.215 29.323 20.538 29.371 ;
     RECT  21.276 28.493 21.438 29.371 ;
     RECT  4.176 29.255 4.194 29.461 ;
     RECT  5.115 29.335 8.586 29.489 ;
     RECT  7.815 29.489 8.586 29.497 ;
     RECT  13.215 29.371 21.438 29.767 ;
     RECT  7.815 29.497 8.838 29.795 ;
     RECT  4.104 29.461 4.194 29.875 ;
     RECT  12.96 29.767 21.438 29.903 ;
     RECT  2.304 28.715 3.33 29.911 ;
     RECT  4.068 29.875 4.194 29.911 ;
     RECT  12.96 29.903 20.466 29.939 ;
     RECT  2.304 29.911 4.194 30.029 ;
     RECT  10.515 28.049 10.797 30.307 ;
     RECT  3.816 30.029 4.194 30.331 ;
     RECT  5.115 29.489 6.966 30.331 ;
     RECT  10.515 30.307 10.854 30.407 ;
     RECT  3.816 30.331 6.966 30.577 ;
     RECT  7.815 29.795 8.586 30.577 ;
     RECT  3.816 30.577 8.586 30.605 ;
     RECT  4.176 30.605 8.586 30.875 ;
     RECT  7.815 30.875 8.586 30.919 ;
     RECT  5.115 30.875 6.966 31.019 ;
     RECT  6.588 31.019 6.966 31.145 ;
     RECT  7.815 30.919 8.982 31.181 ;
     RECT  2.304 30.029 3.006 31.387 ;
     RECT  4.176 30.875 4.194 31.495 ;
     RECT  2.304 31.387 3.222 31.531 ;
     RECT  4.068 31.495 4.194 31.531 ;
     RECT  2.304 31.531 4.194 31.627 ;
     RECT  5.115 31.019 5.814 31.627 ;
     RECT  13.215 29.939 20.466 31.657 ;
     RECT  21.24 29.903 21.438 31.661 ;
     RECT  2.304 31.627 5.814 31.685 ;
     RECT  6.948 31.145 6.966 31.801 ;
     RECT  7.815 31.181 8.097 31.801 ;
     RECT  5.004 31.685 5.814 31.891 ;
     RECT  6.948 31.801 8.097 31.891 ;
     RECT  5.004 31.891 8.097 31.919 ;
     RECT  5.115 31.919 8.097 32.189 ;
     RECT  8.964 31.181 8.982 32.305 ;
     RECT  8.82 32.305 8.982 32.603 ;
     RECT  6.948 32.189 8.097 32.611 ;
     RECT  6.948 32.611 8.19 32.729 ;
     RECT  21.24 31.661 21.366 32.875 ;
     RECT  2.304 31.685 4.194 33.019 ;
     RECT  5.115 32.189 5.814 33.019 ;
     RECT  2.304 33.019 5.814 33.035 ;
     RECT  4.176 33.035 5.814 33.259 ;
     RECT  6.948 32.729 8.097 33.259 ;
     RECT  2.304 33.035 3.438 33.305 ;
     RECT  4.176 33.259 8.097 33.305 ;
     RECT  4.176 33.305 5.814 33.575 ;
     RECT  6.552 33.305 8.097 33.575 ;
     RECT  8.964 32.603 8.982 33.817 ;
     RECT  7.815 33.575 8.097 33.961 ;
     RECT  8.82 33.817 8.982 33.961 ;
     RECT  21.24 32.875 21.474 33.989 ;
     RECT  7.815 33.961 8.982 34.051 ;
     RECT  2.304 33.305 2.898 34.075 ;
     RECT  7.815 34.051 9.054 34.115 ;
     RECT  21.24 33.989 21.402 34.151 ;
     RECT  4.176 33.575 4.194 34.195 ;
     RECT  2.304 34.075 3.222 34.231 ;
     RECT  4.068 34.195 4.194 34.231 ;
     RECT  5.115 33.575 5.814 34.231 ;
     RECT  6.552 33.575 6.966 34.231 ;
     RECT  2.304 34.231 4.194 34.315 ;
     RECT  5.115 34.231 6.966 34.315 ;
     RECT  2.304 34.315 6.966 34.735 ;
     RECT  7.815 34.115 8.19 34.735 ;
     RECT  8.964 34.115 9.054 34.799 ;
     RECT  2.304 34.735 8.19 34.889 ;
     RECT  10.515 30.407 10.797 35.167 ;
     RECT  7.815 34.889 8.19 35.275 ;
     RECT  8.964 34.799 8.982 35.275 ;
     RECT  10.515 35.167 10.854 35.339 ;
     RECT  2.304 34.889 6.966 35.429 ;
     RECT  7.815 35.275 8.982 35.429 ;
     RECT  2.304 35.429 5.814 35.699 ;
     RECT  7.815 35.429 8.226 35.707 ;
     RECT  4.032 35.699 5.814 35.735 ;
     RECT  4.176 35.735 5.814 35.885 ;
     RECT  7.74 35.707 8.226 35.888 ;
     RECT  2.304 35.699 3.258 36.005 ;
     RECT  6.948 35.429 6.966 36.121 ;
     RECT  7.74 35.888 8.097 36.121 ;
     RECT  4.932 35.885 5.814 36.211 ;
     RECT  6.948 36.121 8.097 36.211 ;
     RECT  8.964 35.429 8.982 36.517 ;
     RECT  10.515 35.339 10.797 36.517 ;
     RECT  10.515 36.517 10.854 36.617 ;
     RECT  4.932 36.211 8.097 36.661 ;
     RECT  8.82 36.517 8.982 36.661 ;
     RECT  2.34 36.005 3.258 36.763 ;
     RECT  4.932 36.661 8.982 36.779 ;
     RECT  4.932 36.779 8.097 36.815 ;
     RECT  8.82 36.779 8.982 36.815 ;
     RECT  21.312 34.151 21.402 36.823 ;
     RECT  8.892 36.815 8.982 36.887 ;
     RECT  4.176 35.885 4.194 36.895 ;
     RECT  2.304 36.763 3.258 36.931 ;
     RECT  4.068 36.895 4.194 36.931 ;
     RECT  2.304 36.931 4.194 37.003 ;
     RECT  4.932 36.815 6.966 37.003 ;
     RECT  2.304 37.003 6.966 37.355 ;
     RECT  10.515 36.617 10.797 37.471 ;
     RECT  10.515 37.471 10.854 37.589 ;
     RECT  4.176 37.355 6.966 37.597 ;
     RECT  7.815 36.815 8.097 37.597 ;
     RECT  21.24 36.823 21.402 37.597 ;
     RECT  4.176 37.597 8.097 37.625 ;
     RECT  6.948 37.625 8.097 37.831 ;
     RECT  6.948 37.831 8.19 37.895 ;
     RECT  7.704 37.895 8.19 37.975 ;
     RECT  8.964 36.887 8.982 37.975 ;
     RECT  7.704 37.975 8.982 38.039 ;
     RECT  7.815 38.039 8.982 38.129 ;
     RECT  4.176 37.625 5.814 38.137 ;
     RECT  7.815 38.129 8.154 38.189 ;
     RECT  2.304 37.355 3.258 38.281 ;
     RECT  4.032 38.137 5.814 38.281 ;
     RECT  13.215 31.657 20.502 38.309 ;
     RECT  20.196 38.309 20.502 38.399 ;
     RECT  2.304 38.281 5.814 38.435 ;
     RECT  20.232 38.399 20.502 38.477 ;
     RECT  4.176 38.435 5.814 38.779 ;
     RECT  6.948 37.895 6.966 38.779 ;
     RECT  4.176 38.779 6.966 38.975 ;
     RECT  5.004 38.975 6.966 39.055 ;
     RECT  7.815 38.189 8.097 39.055 ;
     RECT  5.004 39.055 8.097 39.083 ;
     RECT  13.215 38.309 19.17 39.091 ;
     RECT  13.215 39.091 19.422 39.149 ;
     RECT  6.552 39.083 8.097 39.209 ;
     RECT  8.964 38.129 8.982 39.217 ;
     RECT  5.004 39.083 5.814 39.245 ;
     RECT  6.948 39.209 8.097 39.361 ;
     RECT  8.82 39.217 8.982 39.361 ;
     RECT  20.232 38.477 20.466 39.451 ;
     RECT  6.948 39.361 8.982 39.479 ;
     RECT  19.944 39.451 20.466 39.485 ;
     RECT  6.948 39.479 8.097 39.515 ;
     RECT  8.82 39.479 8.982 39.515 ;
     RECT  2.304 38.435 3.402 39.595 ;
     RECT  4.176 38.975 4.194 39.595 ;
     RECT  0.216 39.289 0.234 39.917 ;
     RECT  2.304 39.595 4.194 39.917 ;
     RECT  13.215 39.149 19.17 39.979 ;
     RECT  19.944 39.485 20.25 39.979 ;
     RECT  3.78 39.917 4.194 40.165 ;
     RECT  5.115 39.245 5.814 40.165 ;
     RECT  3.78 40.165 5.814 40.205 ;
     RECT  4.932 40.205 5.814 40.297 ;
     RECT  6.948 39.515 6.966 40.297 ;
     RECT  7.815 39.515 8.097 40.297 ;
     RECT  3.78 40.205 4.194 40.325 ;
     RECT  21.24 37.597 21.438 40.349 ;
     RECT  4.932 40.297 8.097 40.531 ;
     RECT  4.932 40.531 8.19 40.559 ;
     RECT  21.348 40.349 21.438 40.589 ;
     RECT  4.932 40.559 5.814 40.595 ;
     RECT  13.215 39.979 20.25 40.603 ;
     RECT  6.948 40.559 8.19 40.675 ;
     RECT  8.964 39.515 8.982 40.675 ;
     RECT  21.348 40.589 21.366 40.685 ;
     RECT  6.948 40.675 8.982 40.829 ;
     RECT  6.948 40.829 8.154 40.865 ;
     RECT  7.815 40.865 8.154 40.877 ;
     RECT  2.304 39.917 2.754 41.131 ;
     RECT  13.215 40.603 20.538 41.143 ;
     RECT  3.96 40.325 4.194 41.243 ;
     RECT  2.304 41.131 3.222 41.251 ;
     RECT  2.304 41.251 3.33 41.369 ;
     RECT  13.215 41.143 20.574 41.369 ;
     RECT  4.176 41.243 4.194 41.449 ;
     RECT  5.115 40.595 5.814 41.449 ;
     RECT  13.215 41.369 19.17 41.549 ;
     RECT  2.304 41.369 2.934 41.611 ;
     RECT  4.176 41.449 5.814 41.675 ;
     RECT  4.932 41.675 5.814 41.749 ;
     RECT  6.948 40.865 6.966 41.749 ;
     RECT  4.932 41.749 6.966 41.755 ;
     RECT  7.815 40.877 8.097 41.755 ;
     RECT  4.932 41.755 8.097 41.789 ;
     RECT  6.552 41.789 8.097 41.791 ;
     RECT  8.964 40.829 8.982 41.791 ;
     RECT  6.552 41.791 8.982 41.909 ;
     RECT  2.268 41.611 2.934 41.945 ;
     RECT  4.932 41.789 5.814 41.945 ;
     RECT  7.704 41.909 8.982 41.981 ;
     RECT  4.176 41.675 4.194 42.025 ;
     RECT  19.944 41.369 20.574 42.061 ;
     RECT  7.704 41.981 8.838 42.089 ;
     RECT  19.944 42.061 20.61 42.151 ;
     RECT  7.815 42.089 8.838 42.215 ;
     RECT  2.304 41.945 2.934 42.379 ;
     RECT  3.924 42.025 4.194 42.379 ;
     RECT  13.215 41.549 19.098 42.601 ;
     RECT  13.215 42.601 19.134 42.727 ;
     RECT  19.944 42.151 20.646 42.727 ;
     RECT  13.215 42.727 20.646 42.749 ;
     RECT  2.304 42.379 4.194 42.763 ;
     RECT  5.115 41.945 5.814 42.763 ;
     RECT  2.304 42.763 5.814 42.997 ;
     RECT  6.948 41.909 6.966 42.997 ;
     RECT  7.815 42.215 8.586 42.997 ;
     RECT  2.304 42.997 8.586 43.295 ;
     RECT  4.068 43.295 8.586 43.537 ;
     RECT  10.515 37.589 10.797 43.537 ;
     RECT  13.215 42.749 20.61 43.613 ;
     RECT  20.52 43.613 20.61 43.757 ;
     RECT  4.068 43.537 8.874 43.979 ;
     RECT  2.304 43.295 3.258 44.221 ;
     RECT  4.068 43.979 8.586 44.221 ;
     RECT  20.52 43.757 20.574 44.477 ;
     RECT  20.52 44.477 20.538 44.621 ;
     RECT  13.215 43.613 19.422 44.653 ;
     RECT  2.304 44.221 8.586 44.995 ;
     RECT  2.304 44.995 8.874 45.149 ;
     RECT  2.304 45.149 8.586 45.403 ;
     RECT  2.268 45.403 8.586 45.419 ;
     RECT  13.215 44.653 19.962 45.419 ;
     RECT  2.268 45.419 3.006 45.455 ;
     RECT  14.22 45.419 19.962 45.571 ;
     RECT  2.268 45.455 2.862 45.725 ;
     RECT  3.96 45.419 8.586 45.773 ;
     RECT  14.22 45.571 20.538 45.821 ;
     RECT  10.515 43.537 10.854 45.869 ;
     RECT  6.552 45.773 8.586 45.959 ;
     RECT  3.96 45.773 5.814 45.995 ;
     RECT  6.84 45.959 8.586 45.995 ;
     RECT  3.96 45.995 4.194 46.237 ;
     RECT  7.776 45.995 8.586 46.237 ;
     RECT  13.215 45.419 13.497 46.237 ;
     RECT  14.22 45.821 18.954 46.237 ;
     RECT  13.215 46.237 18.954 46.265 ;
     RECT  2.304 45.725 2.862 46.507 ;
     RECT  3.924 46.237 4.194 46.507 ;
     RECT  7.776 46.237 8.838 46.507 ;
     RECT  19.944 45.821 20.538 46.579 ;
     RECT  7.776 46.507 8.91 46.607 ;
     RECT  2.304 46.507 4.194 46.747 ;
     RECT  5.115 45.995 5.814 46.747 ;
     RECT  19.944 46.579 20.574 46.849 ;
     RECT  6.84 45.995 6.966 46.921 ;
     RECT  7.776 46.607 8.586 46.921 ;
     RECT  2.304 46.747 5.814 46.949 ;
     RECT  3.744 46.949 5.814 47.039 ;
     RECT  3.744 47.039 4.302 47.075 ;
     RECT  13.215 46.265 18.897 47.083 ;
     RECT  19.944 46.849 20.61 47.083 ;
     RECT  5.115 47.039 5.814 47.155 ;
     RECT  6.84 46.921 8.586 47.155 ;
     RECT  5.115 47.155 8.586 47.213 ;
     RECT  6.552 47.213 8.586 47.309 ;
     RECT  13.215 47.083 20.61 47.549 ;
     RECT  13.215 47.549 18.954 47.579 ;
     RECT  10.515 45.869 10.797 47.587 ;
     RECT  6.948 47.309 8.586 47.651 ;
     RECT  10.515 47.587 10.854 47.687 ;
     RECT  7.815 47.651 8.586 47.695 ;
     RECT  2.304 46.949 2.862 47.803 ;
     RECT  3.744 47.075 4.194 47.803 ;
     RECT  7.815 47.695 8.874 47.849 ;
     RECT  2.304 47.803 4.194 48.119 ;
     RECT  2.304 48.119 3.114 48.155 ;
     RECT  4.032 48.119 4.194 48.155 ;
     RECT  14.652 47.579 18.954 48.271 ;
     RECT  19.944 47.549 20.61 48.271 ;
     RECT  4.176 48.155 4.194 48.361 ;
     RECT  14.652 48.271 20.61 48.413 ;
     RECT  4.176 48.361 4.302 48.427 ;
     RECT  5.115 47.213 5.814 48.427 ;
     RECT  2.304 48.155 2.934 48.461 ;
     RECT  6.948 47.651 6.966 48.541 ;
     RECT  7.815 47.849 8.586 48.541 ;
     RECT  0.216 47.857 0.234 48.557 ;
     RECT  14.652 48.413 20.538 48.739 ;
     RECT  4.176 48.427 5.814 48.775 ;
     RECT  6.948 48.541 8.586 48.775 ;
     RECT  4.176 48.775 8.586 48.845 ;
     RECT  4.176 48.845 5.814 48.901 ;
     RECT  6.552 48.845 8.586 48.929 ;
     RECT  14.472 48.739 20.538 48.929 ;
     RECT  7.815 48.929 8.586 48.937 ;
     RECT  2.304 48.461 2.697 48.965 ;
     RECT  14.868 48.929 16.197 48.965 ;
     RECT  16.956 48.929 20.538 49.085 ;
     RECT  7.815 48.937 8.838 49.171 ;
     RECT  2.415 48.965 2.697 49.195 ;
     RECT  7.815 49.171 8.91 49.307 ;
     RECT  4.104 48.901 5.814 49.315 ;
     RECT  2.415 49.195 3.222 49.351 ;
     RECT  4.068 49.315 5.814 49.351 ;
     RECT  2.415 49.351 5.814 49.505 ;
     RECT  16.956 49.085 19.242 49.541 ;
     RECT  0.216 49.549 0.234 49.613 ;
     RECT  19.98 49.085 20.538 49.613 ;
     RECT  17.1 49.541 19.242 49.739 ;
     RECT  17.136 49.739 19.242 49.891 ;
     RECT  2.415 49.505 2.718 49.915 ;
     RECT  14.904 48.965 16.197 49.981 ;
     RECT  14.832 49.981 16.197 50.009 ;
     RECT  3.78 49.505 5.814 50.017 ;
     RECT  6.84 48.929 6.966 50.017 ;
     RECT  7.815 49.307 8.586 50.017 ;
     RECT  17.136 49.891 19.962 50.045 ;
     RECT  2.376 49.915 2.718 50.251 ;
     RECT  3.78 50.017 8.586 50.279 ;
     RECT  17.172 50.045 19.962 50.285 ;
     RECT  6.84 50.279 8.586 50.315 ;
     RECT  2.304 50.251 2.718 50.395 ;
     RECT  3.78 50.279 5.814 50.395 ;
     RECT  7.704 50.315 8.586 50.395 ;
     RECT  7.704 50.395 8.874 50.459 ;
     RECT  7.815 50.459 8.874 50.557 ;
     RECT  2.304 50.395 5.814 50.621 ;
     RECT  17.172 50.285 19.098 50.621 ;
     RECT  19.944 50.285 19.962 50.629 ;
     RECT  7.815 50.557 8.946 50.657 ;
     RECT  14.832 50.009 14.85 50.657 ;
     RECT  19.944 50.629 20.538 50.813 ;
     RECT  17.172 50.621 18.897 50.819 ;
     RECT  2.304 50.621 4.05 50.927 ;
     RECT  0.216 50.395 0.234 51.005 ;
     RECT  19.944 50.813 20.502 51.005 ;
     RECT  4.86 50.621 5.814 51.161 ;
     RECT  6.84 50.315 6.966 51.307 ;
     RECT  3.996 50.927 4.05 51.359 ;
     RECT  4.86 51.161 5.67 51.395 ;
     RECT  6.408 51.307 6.966 51.467 ;
     RECT  7.815 50.657 8.586 51.475 ;
     RECT  17.676 50.819 18.897 51.475 ;
     RECT  6.408 51.467 6.57 51.503 ;
     RECT  4.86 51.395 5.397 51.511 ;
     RECT  6.552 51.503 6.57 51.629 ;
     RECT  7.308 51.475 8.586 51.629 ;
     RECT  17.676 51.475 18.954 51.629 ;
     RECT  7.632 51.629 8.586 51.637 ;
     RECT  4.68 51.511 5.397 51.665 ;
     RECT  2.304 50.927 2.862 51.899 ;
     RECT  7.632 51.637 8.838 51.899 ;
     RECT  17.676 51.629 17.802 51.899 ;
     RECT  20.448 51.005 20.502 51.899 ;
     RECT  2.304 51.899 2.697 51.935 ;
     RECT  7.632 51.899 8.097 51.935 ;
     RECT  8.82 51.899 8.838 51.935 ;
     RECT  18.576 51.629 18.897 51.971 ;
     RECT  17.784 51.899 17.802 52.169 ;
     RECT  20.448 51.899 20.466 52.169 ;
     RECT  2.376 51.935 2.697 52.205 ;
     RECT  2.415 52.205 2.697 53.747 ;
     RECT  5.115 51.665 5.397 53.747 ;
     RECT  7.815 51.935 8.097 53.747 ;
     RECT  10.515 47.687 10.797 53.747 ;
     RECT  13.215 47.579 13.497 53.747 ;
     RECT  15.915 50.009 16.197 53.747 ;
     RECT  18.615 51.971 18.897 53.747 ;
     RECT  2.415 53.747 2.505 54.017 ;
     RECT  5.115 53.747 5.205 54.017 ;
     RECT  7.815 53.747 7.905 54.017 ;
     RECT  10.515 53.747 10.605 54.017 ;
     RECT  13.215 53.747 13.305 54.017 ;
     RECT  15.915 53.747 16.005 54.017 ;
     RECT  18.615 53.747 18.705 54.017 ;
    LAYER M4 ;
     RECT  0.192 4.512 0.245 4.536 ;
     RECT  0.156 4.536 0.245 4.896 ;
     RECT  0.192 4.896 0.245 4.92 ;
     RECT  0.156 4.92 0.245 5.232 ;
     RECT  0.192 5.232 0.245 5.256 ;
     RECT  0.156 5.256 0.245 5.568 ;
     RECT  0.192 5.568 0.245 5.592 ;
     RECT  0.156 5.592 0.245 5.904 ;
     RECT  0.192 5.904 0.245 5.928 ;
     RECT  0.156 5.928 0.245 6.288 ;
     RECT  0.192 6.288 0.245 6.312 ;
     RECT  0.156 6.312 0.245 6.624 ;
     RECT  0.192 6.624 0.245 6.648 ;
     RECT  0.156 6.648 0.245 6.96 ;
     RECT  0.192 6.96 0.245 6.984 ;
     RECT  0.156 6.984 0.245 7.296 ;
     RECT  0.192 7.296 0.245 7.32 ;
     RECT  0.156 7.32 0.245 7.632 ;
     RECT  0.192 7.632 0.245 7.656 ;
     RECT  0.156 7.656 0.245 8.016 ;
     RECT  0.192 8.016 0.245 8.04 ;
     RECT  0.156 8.04 0.245 8.352 ;
     RECT  0.192 8.352 0.245 8.376 ;
     RECT  0.156 8.376 0.245 8.688 ;
     RECT  0.192 8.688 0.245 8.712 ;
     RECT  0.156 8.712 0.245 9.024 ;
     RECT  0.192 9.024 0.245 9.048 ;
     RECT  0.156 9.048 0.245 9.36 ;
     RECT  0.192 9.36 0.245 9.384 ;
     RECT  0.156 9.384 0.245 9.744 ;
     RECT  0.192 9.744 0.245 9.768 ;
     RECT  0.156 9.768 0.245 10.08 ;
     RECT  0.192 10.08 0.245 10.104 ;
     RECT  0.156 10.104 0.245 10.416 ;
     RECT  0.192 10.416 0.245 10.44 ;
     RECT  0.156 10.44 0.245 10.752 ;
     RECT  0.192 10.752 0.245 10.776 ;
     RECT  0.156 10.776 0.245 11.136 ;
     RECT  0.192 11.136 0.245 11.16 ;
     RECT  0.156 11.16 0.245 11.472 ;
     RECT  0.192 11.472 0.245 11.496 ;
     RECT  0.156 11.496 0.245 11.808 ;
     RECT  0.192 11.808 0.245 11.832 ;
     RECT  0.156 11.832 0.245 12.144 ;
     RECT  0.192 12.144 0.245 12.168 ;
     RECT  0.156 12.168 0.245 12.48 ;
     RECT  0.192 12.48 0.245 12.504 ;
     RECT  0.156 12.504 0.245 12.864 ;
     RECT  0.192 12.864 0.245 12.888 ;
     RECT  0.156 12.888 0.245 13.2 ;
     RECT  0.192 13.2 0.245 13.224 ;
     RECT  0.156 13.224 0.245 13.536 ;
     RECT  0.192 13.536 0.245 13.56 ;
     RECT  0.156 13.56 0.245 13.872 ;
     RECT  0.192 13.872 0.245 13.896 ;
     RECT  0.156 13.896 0.245 14.256 ;
     RECT  0.192 14.256 0.245 14.28 ;
     RECT  0.156 14.28 0.245 14.592 ;
     RECT  0.192 14.592 0.245 14.616 ;
     RECT  0.156 14.616 0.245 14.928 ;
     RECT  0.192 14.928 0.245 14.952 ;
     RECT  0.156 14.952 0.245 15.264 ;
     RECT  0.192 15.264 0.245 15.288 ;
     RECT  0.156 15.288 0.245 15.6 ;
     RECT  0.192 15.6 0.245 15.624 ;
     RECT  0.156 15.624 0.245 15.984 ;
     RECT  0.192 15.984 0.245 16.008 ;
     RECT  0.156 16.008 0.245 16.32 ;
     RECT  0.192 16.32 0.245 16.344 ;
     RECT  0.156 16.344 0.245 16.656 ;
     RECT  0.192 16.656 0.245 16.68 ;
     RECT  0.156 16.68 0.245 16.992 ;
     RECT  0.192 16.992 0.245 17.016 ;
     RECT  0.156 17.016 0.245 17.328 ;
     RECT  0.192 17.328 0.245 17.352 ;
     RECT  0.156 17.352 0.245 17.712 ;
     RECT  0.192 17.712 0.245 17.736 ;
     RECT  0.156 17.736 0.245 18.048 ;
     RECT  0.192 18.048 0.245 18.072 ;
     RECT  0.156 18.072 0.245 18.384 ;
     RECT  0.192 18.384 0.245 18.408 ;
     RECT  0.156 18.408 0.245 18.72 ;
     RECT  0.192 18.72 0.245 18.744 ;
     RECT  0.156 18.744 0.245 19.104 ;
     RECT  0.192 19.104 0.245 19.128 ;
     RECT  0.156 19.128 0.245 19.44 ;
     RECT  0.192 19.44 0.245 19.464 ;
     RECT  0.156 19.464 0.245 19.776 ;
     RECT  0.192 19.776 0.245 19.8 ;
     RECT  0.156 19.8 0.245 20.112 ;
     RECT  0.192 20.112 0.245 20.136 ;
     RECT  0.156 20.136 0.245 20.448 ;
     RECT  0.192 20.448 0.245 20.472 ;
     RECT  0.156 20.472 0.245 20.832 ;
     RECT  0.192 20.832 0.245 20.856 ;
     RECT  0.156 20.856 0.245 21.168 ;
     RECT  0.192 21.168 0.245 21.192 ;
     RECT  0.156 21.192 0.245 21.504 ;
     RECT  0.192 21.504 0.245 21.528 ;
     RECT  0.156 21.528 0.245 21.84 ;
     RECT  0.192 21.84 0.245 21.864 ;
     RECT  0.156 21.864 0.245 22.224 ;
     RECT  0.192 22.224 0.245 22.248 ;
     RECT  0.156 22.248 0.245 22.56 ;
     RECT  0.192 22.56 0.245 22.584 ;
     RECT  0.156 22.584 0.245 22.896 ;
     RECT  0.192 22.896 0.245 22.92 ;
     RECT  0.156 22.92 0.245 23.232 ;
     RECT  0.192 23.232 0.245 23.256 ;
     RECT  0.156 23.256 0.245 23.568 ;
     RECT  0.192 23.568 0.245 23.592 ;
     RECT  0.156 23.592 0.245 23.952 ;
     RECT  0.192 23.952 0.245 23.976 ;
     RECT  0.156 23.976 0.245 24.288 ;
     RECT  0.192 24.288 0.245 24.312 ;
     RECT  0.156 24.312 0.245 24.624 ;
     RECT  0.192 24.624 0.245 24.648 ;
     RECT  0.156 24.648 0.245 24.96 ;
     RECT  0.192 24.96 0.245 24.984 ;
     RECT  0.156 24.984 0.245 25.344 ;
     RECT  0.192 25.344 0.245 25.368 ;
     RECT  0.156 25.368 0.245 25.68 ;
     RECT  0.192 25.68 0.245 25.704 ;
     RECT  0.156 25.704 0.245 26.016 ;
     RECT  0.192 26.016 0.245 26.04 ;
     RECT  0.156 26.04 0.245 26.352 ;
     RECT  0.192 26.352 0.245 26.376 ;
     RECT  0.156 26.376 0.245 26.688 ;
     RECT  0.192 26.688 0.245 26.712 ;
     RECT  0.156 26.712 0.245 27.072 ;
     RECT  0.192 27.072 0.245 27.096 ;
     RECT  0.156 27.096 0.245 27.408 ;
     RECT  0.192 27.408 0.245 27.432 ;
     RECT  0.156 27.432 0.245 27.744 ;
     RECT  0.192 27.744 0.245 27.768 ;
     RECT  0.156 27.768 0.245 28.08 ;
     RECT  0.192 28.08 0.245 28.104 ;
     RECT  0.156 28.104 0.245 28.416 ;
     RECT  0.192 28.416 0.245 28.44 ;
     RECT  0.156 28.44 0.245 28.8 ;
     RECT  0.192 28.8 0.245 28.824 ;
     RECT  0.156 28.824 0.245 29.136 ;
     RECT  0.192 29.136 0.245 29.16 ;
     RECT  0.156 29.16 0.245 29.472 ;
     RECT  0.192 29.472 0.245 29.496 ;
     RECT  0.156 29.496 0.245 29.808 ;
     RECT  0.192 29.808 0.245 29.832 ;
     RECT  0.156 29.832 0.245 30.192 ;
     RECT  0.192 30.192 0.245 30.216 ;
     RECT  0.156 30.216 0.245 30.528 ;
     RECT  0.192 30.528 0.245 30.552 ;
     RECT  0.156 30.552 0.245 30.864 ;
     RECT  0.192 30.864 0.245 30.888 ;
     RECT  0.156 30.888 0.245 31.2 ;
     RECT  0.192 31.2 0.245 31.224 ;
     RECT  0.156 31.224 0.245 31.536 ;
     RECT  0.192 31.536 0.245 31.56 ;
     RECT  0.156 31.56 0.245 31.92 ;
     RECT  0.192 31.92 0.245 31.944 ;
     RECT  0.156 31.944 0.245 32.256 ;
     RECT  0.192 32.256 0.245 32.28 ;
     RECT  0.156 32.28 0.245 32.592 ;
     RECT  0.192 32.592 0.245 32.616 ;
     RECT  0.156 32.616 0.245 32.928 ;
     RECT  0.192 32.928 0.245 32.952 ;
     RECT  0.156 32.952 0.245 33.312 ;
     RECT  0.192 33.312 0.245 33.336 ;
     RECT  0.156 33.336 0.245 33.648 ;
     RECT  0.192 33.648 0.245 33.672 ;
     RECT  0.156 33.672 0.245 33.984 ;
     RECT  0.192 33.984 0.245 34.008 ;
     RECT  0.156 34.008 0.245 34.32 ;
     RECT  0.192 34.32 0.245 34.344 ;
     RECT  0.156 34.344 0.245 34.656 ;
     RECT  0.192 34.656 0.245 34.68 ;
     RECT  0.156 34.68 0.245 35.04 ;
     RECT  0.192 35.04 0.245 35.064 ;
     RECT  0.156 35.064 0.245 35.376 ;
     RECT  0.192 35.376 0.245 35.4 ;
     RECT  0.156 35.4 0.245 35.712 ;
     RECT  0.192 35.712 0.245 35.736 ;
     RECT  0.156 35.736 0.245 36.048 ;
     RECT  0.192 36.048 0.245 36.072 ;
     RECT  0.156 36.072 0.245 36.384 ;
     RECT  0.192 36.384 0.245 36.408 ;
     RECT  0.156 36.408 0.245 36.768 ;
     RECT  0.192 36.768 0.245 36.792 ;
     RECT  0.156 36.792 0.245 37.104 ;
     RECT  0.192 37.104 0.245 37.128 ;
     RECT  0.156 37.128 0.245 37.44 ;
     RECT  0.192 37.44 0.245 37.464 ;
     RECT  0.156 37.464 0.245 37.776 ;
     RECT  0.192 37.776 0.245 37.8 ;
     RECT  0.156 37.8 0.245 38.16 ;
     RECT  0.192 38.16 0.245 38.184 ;
     RECT  0.156 38.184 0.245 38.496 ;
     RECT  0.192 38.496 0.245 38.52 ;
     RECT  0.156 38.52 0.245 38.832 ;
     RECT  0.192 38.832 0.245 38.856 ;
     RECT  0.156 38.856 0.245 39.168 ;
     RECT  0.192 39.168 0.245 39.192 ;
     RECT  0.156 39.192 0.245 39.504 ;
     RECT  0.192 39.504 0.245 39.528 ;
     RECT  0.156 39.528 0.245 39.888 ;
     RECT  0.192 39.888 0.245 39.912 ;
     RECT  0.156 39.912 0.245 40.224 ;
     RECT  0.192 40.224 0.245 40.248 ;
     RECT  0.156 40.248 0.245 40.56 ;
     RECT  0.192 40.56 0.245 40.584 ;
     RECT  0.156 40.584 0.245 40.896 ;
     RECT  0.192 40.896 0.245 40.92 ;
     RECT  0.156 40.92 0.245 41.28 ;
     RECT  0.192 41.28 0.245 41.304 ;
     RECT  0.156 41.304 0.245 41.616 ;
     RECT  0.192 41.616 0.245 41.64 ;
     RECT  0.156 41.64 0.245 41.952 ;
     RECT  0.192 41.952 0.245 41.976 ;
     RECT  0.156 41.976 0.245 42.288 ;
     RECT  0.192 42.288 0.245 42.312 ;
     RECT  0.156 42.312 0.245 42.624 ;
     RECT  0.192 42.624 0.245 42.648 ;
     RECT  0.156 42.648 0.245 43.008 ;
     RECT  0.192 43.008 0.245 43.032 ;
     RECT  0.156 43.032 0.245 43.344 ;
     RECT  0.192 43.344 0.245 43.368 ;
     RECT  0.156 43.368 0.245 43.68 ;
     RECT  0.192 43.68 0.245 43.704 ;
     RECT  0.156 43.704 0.245 44.016 ;
     RECT  0.192 44.016 0.245 44.04 ;
     RECT  0.156 44.04 0.245 44.4 ;
     RECT  0.192 44.4 0.245 44.424 ;
     RECT  0.156 44.424 0.245 44.736 ;
     RECT  0.192 44.736 0.245 44.76 ;
     RECT  0.156 44.76 0.245 45.072 ;
     RECT  0.192 45.072 0.245 45.096 ;
     RECT  0.156 45.096 0.245 45.408 ;
     RECT  0.192 45.408 0.245 45.432 ;
     RECT  0.156 45.432 0.245 45.744 ;
     RECT  0.192 45.744 0.245 45.768 ;
     RECT  0.156 45.768 0.245 46.128 ;
     RECT  0.192 46.128 0.245 46.152 ;
     RECT  0.156 46.152 0.245 46.464 ;
     RECT  0.192 46.464 0.245 46.488 ;
     RECT  0.156 46.488 0.245 46.8 ;
     RECT  0.192 46.8 0.245 46.824 ;
     RECT  0.156 46.824 0.245 47.136 ;
     RECT  0.192 47.136 0.245 47.16 ;
     RECT  0.156 47.16 0.245 47.472 ;
     RECT  0.192 47.472 0.245 47.496 ;
     RECT  0.156 47.496 0.245 47.856 ;
     RECT  0.192 47.856 0.245 47.88 ;
     RECT  0.156 47.88 0.245 48.192 ;
     RECT  0.192 48.192 0.245 48.216 ;
     RECT  0.156 48.216 0.245 48.528 ;
     RECT  0.192 48.528 0.245 48.552 ;
     RECT  0.156 48.552 0.245 48.864 ;
     RECT  0.192 48.864 0.245 48.888 ;
     RECT  0.156 48.888 0.245 49.248 ;
     RECT  0.192 49.248 0.245 49.272 ;
     RECT  0.156 49.272 0.245 49.584 ;
     RECT  0.192 49.584 0.245 49.608 ;
     RECT  0.156 49.608 0.245 49.92 ;
     RECT  0.192 49.92 0.245 49.944 ;
     RECT  0.156 49.944 0.245 50.256 ;
     RECT  0.192 50.256 0.245 50.28 ;
     RECT  0.156 50.28 0.245 50.592 ;
     RECT  0.192 50.592 0.245 50.616 ;
     RECT  0.156 50.616 0.245 50.976 ;
     RECT  0.192 50.976 0.245 51 ;
     RECT  0.156 51 0.245 51.312 ;
     RECT  0.192 51.312 0.245 51.336 ;
     RECT  0.156 51.336 0.245 51.648 ;
     RECT  0.192 51.648 0.245 51.672 ;
     RECT  0.245 4.512 2.408 23.592 ;
     RECT  0.245 24.624 2.408 38.856 ;
     RECT  0.245 40.224 2.408 47.88 ;
     RECT  0.245 48.864 2.408 51.672 ;
     RECT  2.408 2.148 2.512 54.012 ;
     RECT  2.512 2.418 2.704 53.742 ;
     RECT  2.704 6.624 2.765 7.416 ;
     RECT  2.704 8.88 2.765 10.2 ;
     RECT  2.704 46.512 2.765 47.832 ;
     RECT  2.704 50.496 2.765 50.616 ;
     RECT  2.704 11.904 2.945 11.976 ;
     RECT  2.704 18.432 3.251 18.456 ;
     RECT  2.704 21.12 3.251 21.144 ;
     RECT  2.704 28.08 3.251 28.488 ;
     RECT  2.704 31.392 3.251 31.416 ;
     RECT  2.704 34.08 3.251 35.352 ;
     RECT  2.704 41.136 3.251 41.16 ;
     RECT  2.704 43.824 3.251 45.144 ;
     RECT  2.765 46.512 3.251 46.536 ;
     RECT  2.704 49.2 3.251 49.224 ;
     RECT  3.251 34.752 3.269 35.352 ;
     RECT  2.704 39.888 3.269 39.912 ;
     RECT  2.704 13.056 3.277 13.08 ;
     RECT  2.704 17.088 3.277 17.112 ;
     RECT  2.704 14.304 3.292 15.432 ;
     RECT  2.704 19.728 3.292 19.752 ;
     RECT  2.704 29.952 3.292 29.976 ;
     RECT  2.704 32.688 3.292 32.712 ;
     RECT  2.704 42.384 3.292 42.408 ;
     RECT  3.251 44.304 3.292 45.144 ;
     RECT  2.765 47.808 3.292 47.832 ;
     RECT  2.765 50.496 3.292 50.52 ;
     RECT  2.765 7.392 3.299 7.416 ;
     RECT  2.765 8.88 3.299 8.904 ;
     RECT  2.765 10.176 3.299 10.2 ;
     RECT  3.292 14.688 3.299 15.432 ;
     RECT  2.704 22.512 3.299 22.536 ;
     RECT  2.704 24.048 3.299 24.072 ;
     RECT  2.704 25.44 3.299 25.464 ;
     RECT  2.704 26.736 3.299 26.76 ;
     RECT  3.299 14.688 3.313 14.712 ;
     RECT  3.269 34.752 3.521 35.304 ;
     RECT  2.945 11.904 3.805 11.928 ;
     RECT  3.292 44.304 3.809 44.472 ;
     RECT  3.805 11.808 4.597 11.928 ;
     RECT  3.809 44.448 4.597 44.472 ;
     RECT  3.251 28.08 4.769 28.104 ;
     RECT  4.705 21.744 4.777 21.768 ;
     RECT  4.777 21.36 4.789 22.2 ;
     RECT  3.521 35.28 4.789 35.304 ;
     RECT  4.796 46.896 4.813 46.92 ;
     RECT  4.789 34.32 4.837 35.304 ;
     RECT  4.597 44.448 4.844 44.712 ;
     RECT  4.769 28.08 4.957 29.064 ;
     RECT  4.805 6.24 5.108 6.264 ;
     RECT  4.796 7.632 5.108 7.656 ;
     RECT  4.837 8.928 5.108 8.952 ;
     RECT  4.837 10.56 5.108 10.584 ;
     RECT  4.597 11.808 5.108 11.976 ;
     RECT  4.813 14.784 5.108 14.808 ;
     RECT  4.805 15.984 5.108 16.008 ;
     RECT  4.849 18.768 5.108 18.792 ;
     RECT  4.844 20.256 5.108 20.28 ;
     RECT  4.789 21.36 5.108 23.16 ;
     RECT  4.789 24.48 5.108 24.504 ;
     RECT  4.769 25.68 5.108 25.704 ;
     RECT  4.957 27.888 5.108 29.064 ;
     RECT  4.789 30.336 5.108 30.36 ;
     RECT  4.789 31.632 5.108 31.656 ;
     RECT  4.789 33.024 5.108 33.048 ;
     RECT  4.837 34.32 5.108 35.88 ;
     RECT  4.837 37.008 5.108 37.032 ;
     RECT  4.805 38.208 5.108 38.232 ;
     RECT  4.837 40.176 5.108 40.2 ;
     RECT  4.796 41.472 5.108 41.496 ;
     RECT  4.805 42.768 5.108 42.792 ;
     RECT  4.844 44.448 5.108 45.576 ;
     RECT  4.813 46.752 5.108 46.92 ;
     RECT  4.796 48.432 5.108 48.456 ;
     RECT  4.805 49.584 5.108 49.608 ;
     RECT  5.108 2.148 5.212 54.012 ;
     RECT  5.212 2.418 5.404 53.742 ;
     RECT  5.404 27.36 5.645 28.488 ;
     RECT  5.404 35.28 6.373 35.304 ;
     RECT  5.404 11.952 6.38 11.976 ;
     RECT  6.373 35.04 6.38 35.304 ;
     RECT  5.404 44.688 6.38 44.712 ;
     RECT  6.38 44.496 6.421 44.712 ;
     RECT  6.38 45.744 6.421 45.768 ;
     RECT  5.404 19.344 6.437 19.368 ;
     RECT  5.645 27.36 6.437 27.384 ;
     RECT  5.404 38.784 6.437 38.808 ;
     RECT  6.373 20.688 6.46 20.712 ;
     RECT  6.373 23.424 6.46 23.448 ;
     RECT  6.373 24.672 6.46 24.696 ;
     RECT  6.373 26.112 6.46 26.136 ;
     RECT  6.373 36.384 6.46 36.408 ;
     RECT  6.373 37.584 6.46 37.608 ;
     RECT  6.38 8.256 6.467 8.28 ;
     RECT  6.38 9.504 6.467 9.528 ;
     RECT  6.38 10.992 6.467 12.264 ;
     RECT  6.38 13.68 6.467 13.704 ;
     RECT  6.38 32.016 6.467 32.04 ;
     RECT  6.38 33.264 6.467 33.288 ;
     RECT  6.38 40.32 6.467 40.344 ;
     RECT  6.38 41.76 6.467 41.784 ;
     RECT  6.38 43.008 6.467 43.032 ;
     RECT  6.421 44.496 6.467 45.768 ;
     RECT  6.38 47.184 6.467 47.208 ;
     RECT  6.38 48.816 6.467 48.84 ;
     RECT  6.38 50.064 6.467 50.088 ;
     RECT  5.404 21.744 6.469 21.96 ;
     RECT  6.397 6.816 6.481 6.84 ;
     RECT  6.397 14.832 6.481 14.856 ;
     RECT  6.397 30.72 6.481 30.744 ;
     RECT  6.397 51.312 6.481 51.336 ;
     RECT  6.38 34.704 6.505 35.304 ;
     RECT  6.469 21.36 6.545 21.96 ;
     RECT  5.645 28.464 6.716 28.488 ;
     RECT  6.545 21.36 6.803 21.768 ;
     RECT  6.716 28.368 6.803 28.488 ;
     RECT  6.505 34.368 6.805 35.304 ;
     RECT  6.805 34.368 6.833 35.736 ;
     RECT  6.803 21.36 7.58 21.72 ;
     RECT  6.467 11.76 7.621 11.976 ;
     RECT  7.621 11.76 7.808 12.36 ;
     RECT  7.58 21.12 7.808 21.72 ;
     RECT  6.803 28.464 7.808 28.488 ;
     RECT  6.833 34.752 7.808 35.736 ;
     RECT  6.467 44.688 7.808 45.192 ;
     RECT  7.808 2.148 7.912 54.012 ;
     RECT  7.912 2.418 8.104 53.742 ;
     RECT  8.104 47.664 8.129 47.88 ;
     RECT  8.104 20.88 8.237 22.344 ;
     RECT  8.104 6.096 8.243 6.12 ;
     RECT  8.104 7.2 8.243 7.224 ;
     RECT  8.104 8.448 8.243 8.472 ;
     RECT  8.104 10.08 8.243 10.104 ;
     RECT  8.104 11.136 8.243 11.16 ;
     RECT  8.104 12.768 8.243 12.792 ;
     RECT  8.104 13.872 8.243 13.896 ;
     RECT  8.104 15.456 8.243 15.48 ;
     RECT  8.104 18.192 8.243 18.216 ;
     RECT  8.104 19.584 8.243 19.608 ;
     RECT  8.237 20.88 8.243 20.904 ;
     RECT  8.237 22.32 8.243 22.344 ;
     RECT  8.104 23.568 8.243 23.592 ;
     RECT  8.104 25.008 8.243 25.032 ;
     RECT  8.104 26.592 8.243 26.616 ;
     RECT  8.104 27.888 8.243 28.488 ;
     RECT  8.104 29.616 8.243 29.64 ;
     RECT  8.104 30.96 8.243 30.984 ;
     RECT  8.104 32.592 8.243 32.616 ;
     RECT  8.104 33.84 8.243 34.824 ;
     RECT  8.104 35.856 8.243 36.552 ;
     RECT  8.104 38.16 8.243 38.184 ;
     RECT  8.104 39.216 8.243 39.24 ;
     RECT  8.104 40.848 8.243 40.872 ;
     RECT  8.104 41.952 8.243 41.976 ;
     RECT  8.104 43.536 8.243 43.56 ;
     RECT  8.104 46.224 8.243 46.248 ;
     RECT  8.129 47.664 8.243 47.688 ;
     RECT  8.104 48.96 8.243 48.984 ;
     RECT  8.104 50.352 8.243 50.376 ;
     RECT  8.104 51.648 8.243 51.672 ;
     RECT  8.243 34.8 8.245 34.824 ;
     RECT  8.243 35.856 8.281 35.88 ;
     RECT  8.104 44.544 8.281 45 ;
     RECT  8.243 28.464 10.508 28.488 ;
     RECT  10.508 2.148 10.612 54.012 ;
     RECT  10.612 2.148 10.645 53.742 ;
     RECT  10.645 1.728 10.804 53.742 ;
     RECT  10.804 1.728 10.835 1.752 ;
     RECT  10.804 28.464 13.208 28.488 ;
     RECT  13.208 2.148 13.312 54.012 ;
     RECT  13.312 2.418 13.504 53.742 ;
     RECT  13.504 18.768 14.533 18.792 ;
     RECT  15.001 22.224 15.361 22.248 ;
     RECT  15.325 37.92 15.433 37.944 ;
     RECT  15.361 22.224 15.577 22.488 ;
     RECT  15.217 14.832 15.908 14.856 ;
     RECT  15.757 15.84 15.908 15.864 ;
     RECT  14.677 17.088 15.908 17.112 ;
     RECT  14.533 18.768 15.908 18.984 ;
     RECT  15.793 20.304 15.908 20.328 ;
     RECT  15.577 21.408 15.908 22.488 ;
     RECT  13.504 28.464 15.908 28.488 ;
     RECT  15.433 37.92 15.908 38.28 ;
     RECT  15.908 2.148 16.012 54.012 ;
     RECT  16.012 2.418 16.204 53.742 ;
     RECT  16.204 43.536 16.355 43.56 ;
     RECT  16.204 10.224 16.777 10.248 ;
     RECT  16.204 15.792 16.835 20.328 ;
     RECT  16.835 15.84 17.341 20.328 ;
     RECT  16.204 21.408 17.341 22.584 ;
     RECT  16.204 37.632 17.413 38.28 ;
     RECT  16.204 39.264 17.413 39.816 ;
     RECT  16.204 24.624 17.449 24.648 ;
     RECT  17.372 26.736 17.459 26.76 ;
     RECT  17.305 48.432 17.459 48.456 ;
     RECT  17.413 37.632 17.593 39.816 ;
     RECT  16.204 30.432 17.605 36.312 ;
     RECT  17.605 30.336 17.665 36.312 ;
     RECT  16.204 28.464 17.693 28.488 ;
     RECT  17.449 24.624 17.701 25.128 ;
     RECT  16.204 41.376 17.737 41.4 ;
     RECT  16.204 23.616 17.749 23.64 ;
     RECT  17.701 24.624 17.749 25.32 ;
     RECT  17.341 15.84 17.881 22.584 ;
     RECT  17.749 23.616 17.881 25.32 ;
     RECT  17.701 10.704 17.917 10.728 ;
     RECT  17.593 37.392 18.053 39.816 ;
     RECT  17.665 29.568 18.205 36.312 ;
     RECT  18.053 37.392 18.205 39.912 ;
     RECT  17.485 26.88 18.241 26.904 ;
     RECT  17.693 27.936 18.241 28.488 ;
     RECT  17.917 10.704 18.457 11.16 ;
     RECT  18.241 26.88 18.457 28.488 ;
     RECT  18.205 29.568 18.457 39.912 ;
     RECT  17.701 6.816 18.608 6.84 ;
     RECT  17.585 9.648 18.608 9.672 ;
     RECT  18.457 10.704 18.608 11.256 ;
     RECT  17.737 14.832 18.608 14.856 ;
     RECT  17.881 15.84 18.608 25.32 ;
     RECT  18.457 26.88 18.608 39.912 ;
     RECT  17.737 41.376 18.608 41.64 ;
     RECT  18.169 43.92 18.608 43.944 ;
     RECT  18.608 2.148 18.712 54.012 ;
     RECT  18.712 2.418 18.904 53.742 ;
     RECT  18.904 9.072 19.897 11.928 ;
     RECT  18.904 13.056 19.897 13.128 ;
     RECT  18.904 6.768 19.933 7.464 ;
     RECT  19.897 8.976 19.933 13.128 ;
     RECT  18.904 14.304 19.933 14.328 ;
     RECT  18.904 15.696 19.933 25.32 ;
     RECT  18.904 26.88 19.933 41.88 ;
     RECT  18.904 43.392 19.933 45.816 ;
     RECT  18.904 47.52 19.933 47.544 ;
     RECT  18.904 48.72 19.933 50.28 ;
     RECT  19.933 26.88 20.113 51 ;
     RECT  18.904 4.512 20.437 5.4 ;
     RECT  19.933 6.576 20.437 7.464 ;
     RECT  19.933 8.976 20.437 25.512 ;
     RECT  20.113 26.496 20.437 51 ;
     RECT  20.437 4.512 20.473 25.512 ;
     RECT  20.437 26.496 20.473 51.672 ;
     RECT  20.473 4.512 21.408 4.536 ;
     RECT  20.473 4.536 21.42 4.704 ;
     RECT  20.473 4.704 21.408 4.728 ;
     RECT  20.473 4.728 21.42 4.896 ;
     RECT  20.473 4.896 21.408 4.92 ;
     RECT  20.473 4.92 21.42 5.04 ;
     RECT  20.473 5.04 21.408 5.064 ;
     RECT  20.473 5.064 21.42 5.232 ;
     RECT  20.473 5.232 21.408 5.256 ;
     RECT  20.473 5.256 21.42 5.376 ;
     RECT  20.473 5.376 21.408 5.4 ;
     RECT  20.473 5.4 21.42 5.568 ;
     RECT  20.473 5.568 21.408 5.592 ;
     RECT  20.473 5.592 21.42 5.712 ;
     RECT  20.473 5.712 21.408 5.736 ;
     RECT  20.473 5.736 21.42 5.904 ;
     RECT  20.473 5.904 21.408 5.928 ;
     RECT  20.473 5.928 21.42 6.096 ;
     RECT  20.473 6.096 21.408 6.12 ;
     RECT  20.473 6.12 21.42 6.24 ;
     RECT  20.473 6.24 21.408 6.264 ;
     RECT  20.473 6.264 21.42 6.432 ;
     RECT  20.473 6.432 21.408 6.456 ;
     RECT  20.473 6.456 21.42 6.576 ;
     RECT  20.473 6.576 21.408 6.6 ;
     RECT  20.473 6.6 21.42 6.768 ;
     RECT  20.473 6.768 21.408 6.792 ;
     RECT  20.473 6.792 21.42 6.96 ;
     RECT  20.473 6.96 21.408 6.984 ;
     RECT  20.473 6.984 21.42 7.104 ;
     RECT  20.473 7.104 21.408 7.128 ;
     RECT  20.473 7.128 21.42 7.296 ;
     RECT  20.473 7.296 21.408 7.32 ;
     RECT  20.473 7.32 21.42 7.44 ;
     RECT  20.473 7.44 21.408 7.464 ;
     RECT  20.473 7.464 21.42 7.632 ;
     RECT  20.473 7.632 21.408 7.656 ;
     RECT  20.473 7.656 21.42 7.776 ;
     RECT  20.473 7.776 21.408 7.8 ;
     RECT  20.473 7.8 21.42 7.968 ;
     RECT  20.473 7.968 21.408 7.992 ;
     RECT  20.473 7.992 21.42 8.16 ;
     RECT  20.473 8.16 21.408 8.184 ;
     RECT  20.473 8.184 21.42 8.304 ;
     RECT  20.473 8.304 21.408 8.328 ;
     RECT  20.473 8.328 21.42 8.496 ;
     RECT  20.473 8.496 21.408 8.52 ;
     RECT  20.473 8.52 21.42 8.64 ;
     RECT  20.473 8.64 21.408 8.664 ;
     RECT  20.473 8.664 21.42 8.832 ;
     RECT  20.473 8.832 21.408 8.856 ;
     RECT  20.473 8.856 21.42 8.976 ;
     RECT  20.473 8.976 21.408 9 ;
     RECT  20.473 9 21.42 9.168 ;
     RECT  20.473 9.168 21.408 9.192 ;
     RECT  20.473 9.192 21.42 9.36 ;
     RECT  20.473 9.36 21.408 9.384 ;
     RECT  20.473 9.384 21.42 9.504 ;
     RECT  20.473 9.504 21.408 9.528 ;
     RECT  20.473 9.528 21.42 9.696 ;
     RECT  20.473 9.696 21.408 9.72 ;
     RECT  20.473 9.72 21.42 9.84 ;
     RECT  20.473 9.84 21.408 9.864 ;
     RECT  20.473 9.864 21.42 10.032 ;
     RECT  20.473 10.032 21.408 10.056 ;
     RECT  20.473 10.056 21.42 10.224 ;
     RECT  20.473 10.224 21.408 10.248 ;
     RECT  20.473 10.248 21.42 10.368 ;
     RECT  20.473 10.368 21.408 10.392 ;
     RECT  20.473 10.392 21.42 10.56 ;
     RECT  20.473 10.56 21.408 10.584 ;
     RECT  20.473 10.584 21.42 10.704 ;
     RECT  20.473 10.704 21.408 10.728 ;
     RECT  20.473 10.728 21.42 10.896 ;
     RECT  20.473 10.896 21.408 10.92 ;
     RECT  20.473 10.92 21.42 11.04 ;
     RECT  20.473 11.04 21.408 11.064 ;
     RECT  20.473 11.064 21.42 11.232 ;
     RECT  20.473 11.232 21.408 11.256 ;
     RECT  20.473 11.256 21.42 11.424 ;
     RECT  20.473 11.424 21.408 11.448 ;
     RECT  20.473 11.448 21.42 11.568 ;
     RECT  20.473 11.568 21.408 11.592 ;
     RECT  20.473 11.592 21.42 11.76 ;
     RECT  20.473 11.76 21.408 11.784 ;
     RECT  20.473 11.784 21.42 11.904 ;
     RECT  20.473 11.904 21.408 11.928 ;
     RECT  20.473 11.928 21.42 12.096 ;
     RECT  20.473 12.096 21.408 12.12 ;
     RECT  20.473 12.12 21.42 12.24 ;
     RECT  20.473 12.24 21.408 12.264 ;
     RECT  20.473 12.264 21.42 12.432 ;
     RECT  20.473 12.432 21.408 12.456 ;
     RECT  20.473 12.456 21.42 12.624 ;
     RECT  20.473 12.624 21.408 12.648 ;
     RECT  20.473 12.648 21.42 12.768 ;
     RECT  20.473 12.768 21.408 12.792 ;
     RECT  20.473 12.792 21.42 12.96 ;
     RECT  20.473 12.96 21.408 12.984 ;
     RECT  20.473 12.984 21.42 13.104 ;
     RECT  20.473 13.104 21.408 13.128 ;
     RECT  20.473 13.128 21.42 13.296 ;
     RECT  20.473 13.296 21.408 13.32 ;
     RECT  20.473 13.32 21.42 13.44 ;
     RECT  20.473 13.44 21.408 13.464 ;
     RECT  20.473 13.464 21.42 13.632 ;
     RECT  20.473 13.632 21.408 13.656 ;
     RECT  20.473 13.656 21.42 13.824 ;
     RECT  20.473 13.824 21.408 13.848 ;
     RECT  20.473 13.848 21.42 13.968 ;
     RECT  20.473 13.968 21.408 13.992 ;
     RECT  20.473 13.992 21.42 14.16 ;
     RECT  20.473 14.16 21.408 14.184 ;
     RECT  20.473 14.184 21.42 14.304 ;
     RECT  20.473 14.304 21.408 14.328 ;
     RECT  20.473 14.328 21.42 14.496 ;
     RECT  20.473 14.496 21.408 14.52 ;
     RECT  20.473 14.52 21.42 14.688 ;
     RECT  20.473 14.688 21.408 14.712 ;
     RECT  20.473 14.712 21.42 14.832 ;
     RECT  20.473 14.832 21.408 14.856 ;
     RECT  20.473 14.856 21.42 15.024 ;
     RECT  20.473 15.024 21.408 15.048 ;
     RECT  20.473 15.048 21.42 15.168 ;
     RECT  20.473 15.168 21.408 15.192 ;
     RECT  20.473 15.192 21.42 15.36 ;
     RECT  20.473 15.36 21.408 15.384 ;
     RECT  20.473 15.384 21.42 15.504 ;
     RECT  20.473 15.504 21.408 15.528 ;
     RECT  20.473 15.528 21.42 15.696 ;
     RECT  20.473 15.696 21.408 15.72 ;
     RECT  20.473 15.72 21.42 15.888 ;
     RECT  20.473 15.888 21.408 15.912 ;
     RECT  20.473 15.912 21.42 16.032 ;
     RECT  20.473 16.032 21.408 16.056 ;
     RECT  20.473 16.056 21.42 16.224 ;
     RECT  20.473 16.224 21.408 16.248 ;
     RECT  20.473 16.248 21.42 16.368 ;
     RECT  20.473 16.368 21.408 16.392 ;
     RECT  20.473 16.392 21.42 16.56 ;
     RECT  20.473 16.56 21.408 16.584 ;
     RECT  20.473 16.584 21.42 16.704 ;
     RECT  20.473 16.704 21.408 16.728 ;
     RECT  20.473 16.728 21.42 16.896 ;
     RECT  20.473 16.896 21.408 16.92 ;
     RECT  20.473 16.92 21.42 17.088 ;
     RECT  20.473 17.088 21.408 17.112 ;
     RECT  20.473 17.112 21.42 17.232 ;
     RECT  20.473 17.232 21.408 17.256 ;
     RECT  20.473 17.256 21.42 17.424 ;
     RECT  20.473 17.424 21.408 17.448 ;
     RECT  20.473 17.448 21.42 17.568 ;
     RECT  20.473 17.568 21.408 17.592 ;
     RECT  20.473 17.592 21.42 17.76 ;
     RECT  20.473 17.76 21.408 17.784 ;
     RECT  20.473 17.784 21.42 17.952 ;
     RECT  20.473 17.952 21.408 17.976 ;
     RECT  20.473 17.976 21.42 18.096 ;
     RECT  20.473 18.096 21.408 18.12 ;
     RECT  20.473 18.12 21.42 18.288 ;
     RECT  20.473 18.288 21.408 18.312 ;
     RECT  20.473 18.312 21.42 18.432 ;
     RECT  20.473 18.432 21.408 18.456 ;
     RECT  20.473 18.456 21.42 18.624 ;
     RECT  20.473 18.624 21.408 18.648 ;
     RECT  20.473 18.648 21.42 18.768 ;
     RECT  20.473 18.768 21.408 18.792 ;
     RECT  20.473 18.792 21.42 18.96 ;
     RECT  20.473 18.96 21.408 18.984 ;
     RECT  20.473 18.984 21.42 19.152 ;
     RECT  20.473 19.152 21.408 19.176 ;
     RECT  20.473 19.176 21.42 19.296 ;
     RECT  20.473 19.296 21.408 19.32 ;
     RECT  20.473 19.32 21.42 19.488 ;
     RECT  20.473 19.488 21.408 19.512 ;
     RECT  20.473 19.512 21.42 19.632 ;
     RECT  20.473 19.632 21.408 19.656 ;
     RECT  20.473 19.656 21.42 19.824 ;
     RECT  20.473 19.824 21.408 19.848 ;
     RECT  20.473 19.848 21.42 19.968 ;
     RECT  20.473 19.968 21.408 19.992 ;
     RECT  20.473 19.992 21.42 20.16 ;
     RECT  20.473 20.16 21.408 20.184 ;
     RECT  20.473 20.184 21.42 20.352 ;
     RECT  20.473 20.352 21.408 20.376 ;
     RECT  20.473 20.376 21.42 20.496 ;
     RECT  20.473 20.496 21.408 20.52 ;
     RECT  20.473 20.52 21.42 20.688 ;
     RECT  20.473 20.688 21.408 20.712 ;
     RECT  20.473 20.712 21.42 20.832 ;
     RECT  20.473 20.832 21.408 20.856 ;
     RECT  20.473 20.856 21.42 21.024 ;
     RECT  20.473 21.024 21.408 21.048 ;
     RECT  20.473 21.048 21.42 21.216 ;
     RECT  20.473 21.216 21.408 21.24 ;
     RECT  20.473 21.24 21.42 21.36 ;
     RECT  20.473 21.36 21.408 21.384 ;
     RECT  20.473 21.384 21.42 21.552 ;
     RECT  20.473 21.552 21.408 21.576 ;
     RECT  20.473 21.576 21.42 21.696 ;
     RECT  20.473 21.696 21.408 21.72 ;
     RECT  20.473 21.72 21.42 21.888 ;
     RECT  20.473 21.888 21.408 21.912 ;
     RECT  20.473 21.912 21.42 22.032 ;
     RECT  20.473 22.032 21.408 22.056 ;
     RECT  20.473 22.056 21.42 22.224 ;
     RECT  20.473 22.224 21.408 22.248 ;
     RECT  20.473 22.248 21.42 22.416 ;
     RECT  20.473 22.416 21.408 22.44 ;
     RECT  20.473 22.44 21.42 22.56 ;
     RECT  20.473 22.56 21.408 22.584 ;
     RECT  20.473 22.584 21.42 22.752 ;
     RECT  20.473 22.752 21.408 22.776 ;
     RECT  20.473 22.776 21.42 22.896 ;
     RECT  20.473 22.896 21.408 22.92 ;
     RECT  20.473 22.92 21.42 23.088 ;
     RECT  20.473 23.088 21.408 23.112 ;
     RECT  20.473 23.112 21.42 23.232 ;
     RECT  20.473 23.232 21.408 23.256 ;
     RECT  20.473 23.256 21.42 23.424 ;
     RECT  20.473 23.424 21.408 23.448 ;
     RECT  20.473 23.448 21.42 23.616 ;
     RECT  20.473 23.616 21.408 23.64 ;
     RECT  20.473 23.64 21.42 23.76 ;
     RECT  20.473 23.76 21.408 23.784 ;
     RECT  20.473 23.784 21.42 23.952 ;
     RECT  20.473 23.952 21.408 23.976 ;
     RECT  20.473 23.976 21.42 24.096 ;
     RECT  20.473 24.096 21.408 24.12 ;
     RECT  20.473 24.12 21.42 24.288 ;
     RECT  20.473 24.288 21.408 24.312 ;
     RECT  20.473 24.312 21.42 24.48 ;
     RECT  20.473 24.48 21.408 24.504 ;
     RECT  20.473 24.504 21.42 24.624 ;
     RECT  20.473 24.624 21.408 24.648 ;
     RECT  20.473 24.648 21.42 24.816 ;
     RECT  20.473 24.816 21.408 24.84 ;
     RECT  20.473 24.84 21.42 24.96 ;
     RECT  20.473 24.96 21.408 24.984 ;
     RECT  20.473 24.984 21.42 25.152 ;
     RECT  20.473 25.152 21.408 25.176 ;
     RECT  20.473 25.176 21.42 25.296 ;
     RECT  20.473 25.296 21.408 25.32 ;
     RECT  20.473 25.32 21.42 25.488 ;
     RECT  20.473 25.488 21.408 25.512 ;
     RECT  20.473 25.512 21.42 25.68 ;
     RECT  20.473 25.68 21.408 25.704 ;
     RECT  20.473 25.704 21.42 25.824 ;
     RECT  20.473 25.824 21.408 25.848 ;
     RECT  20.473 25.848 21.42 26.016 ;
     RECT  20.473 26.016 21.408 26.04 ;
     RECT  20.473 26.04 21.42 26.16 ;
     RECT  20.473 26.16 21.408 26.184 ;
     RECT  20.473 26.184 21.42 26.352 ;
     RECT  20.473 26.352 21.408 26.376 ;
     RECT  20.473 26.376 21.42 26.496 ;
     RECT  20.473 26.496 21.408 26.52 ;
     RECT  20.473 26.52 21.42 26.688 ;
     RECT  20.473 26.688 21.408 26.712 ;
     RECT  20.473 26.712 21.42 26.88 ;
     RECT  20.473 26.88 21.408 26.904 ;
     RECT  20.473 26.904 21.42 27.024 ;
     RECT  20.473 27.024 21.408 27.048 ;
     RECT  20.473 27.048 21.42 27.216 ;
     RECT  20.473 27.216 21.408 27.24 ;
     RECT  20.473 27.24 21.42 27.36 ;
     RECT  20.473 27.36 21.408 27.384 ;
     RECT  20.473 27.384 21.42 27.552 ;
     RECT  20.473 27.552 21.408 27.576 ;
     RECT  20.473 27.576 21.42 27.744 ;
     RECT  20.473 27.744 21.408 27.768 ;
     RECT  20.473 27.768 21.42 27.888 ;
     RECT  20.473 27.888 21.408 27.912 ;
     RECT  20.473 27.912 21.42 28.272 ;
     RECT  20.473 28.272 21.408 28.296 ;
     RECT  20.473 28.296 21.42 28.464 ;
     RECT  20.473 28.464 21.408 28.488 ;
     RECT  20.473 28.488 21.42 28.656 ;
     RECT  20.473 28.656 21.408 28.68 ;
     RECT  20.473 28.68 21.42 28.8 ;
     RECT  20.473 28.8 21.408 28.824 ;
     RECT  20.473 28.824 21.42 28.992 ;
     RECT  20.473 28.992 21.408 29.016 ;
     RECT  20.473 29.016 21.42 29.136 ;
     RECT  20.473 29.136 21.408 29.16 ;
     RECT  20.473 29.16 21.42 29.328 ;
     RECT  20.473 29.328 21.408 29.352 ;
     RECT  20.473 29.352 21.42 29.472 ;
     RECT  20.473 29.472 21.408 29.496 ;
     RECT  20.473 29.496 21.42 29.664 ;
     RECT  20.473 29.664 21.408 29.688 ;
     RECT  20.473 29.688 21.42 29.856 ;
     RECT  20.473 29.856 21.408 29.88 ;
     RECT  20.473 29.88 21.42 30 ;
     RECT  20.473 30 21.408 30.024 ;
     RECT  20.473 30.024 21.42 30.192 ;
     RECT  20.473 30.192 21.408 30.216 ;
     RECT  20.473 30.216 21.42 30.336 ;
     RECT  20.473 30.336 21.408 30.36 ;
     RECT  20.473 30.36 21.42 30.528 ;
     RECT  20.473 30.528 21.408 30.552 ;
     RECT  20.473 30.552 21.42 30.72 ;
     RECT  20.473 30.72 21.408 30.744 ;
     RECT  20.473 30.744 21.42 30.864 ;
     RECT  20.473 30.864 21.408 30.888 ;
     RECT  20.473 30.888 21.42 31.056 ;
     RECT  20.473 31.056 21.408 31.08 ;
     RECT  20.473 31.08 21.42 31.2 ;
     RECT  20.473 31.2 21.408 31.224 ;
     RECT  20.473 31.224 21.42 31.392 ;
     RECT  20.473 31.392 21.408 31.416 ;
     RECT  20.473 31.416 21.42 31.536 ;
     RECT  20.473 31.536 21.408 31.56 ;
     RECT  20.473 31.56 21.42 31.728 ;
     RECT  20.473 31.728 21.408 31.752 ;
     RECT  20.473 31.752 21.42 31.92 ;
     RECT  20.473 31.92 21.408 31.944 ;
     RECT  20.473 31.944 21.42 32.064 ;
     RECT  20.473 32.064 21.408 32.088 ;
     RECT  20.473 32.088 21.42 32.256 ;
     RECT  20.473 32.256 21.408 32.28 ;
     RECT  20.473 32.28 21.42 32.4 ;
     RECT  20.473 32.4 21.408 32.424 ;
     RECT  20.473 32.424 21.42 32.592 ;
     RECT  20.473 32.592 21.408 32.616 ;
     RECT  20.473 32.616 21.42 32.736 ;
     RECT  20.473 32.736 21.408 32.76 ;
     RECT  20.473 32.76 21.42 32.928 ;
     RECT  20.473 32.928 21.408 32.952 ;
     RECT  20.473 32.952 21.42 33.12 ;
     RECT  20.473 33.12 21.408 33.144 ;
     RECT  20.473 33.144 21.42 33.264 ;
     RECT  20.473 33.264 21.408 33.288 ;
     RECT  20.473 33.288 21.42 33.456 ;
     RECT  20.473 33.456 21.408 33.48 ;
     RECT  20.473 33.48 21.42 33.6 ;
     RECT  20.473 33.6 21.408 33.624 ;
     RECT  20.473 33.624 21.42 33.792 ;
     RECT  20.473 33.792 21.408 33.816 ;
     RECT  20.473 33.816 21.42 33.984 ;
     RECT  20.473 33.984 21.408 34.008 ;
     RECT  20.473 34.008 21.42 34.128 ;
     RECT  20.473 34.128 21.408 34.152 ;
     RECT  20.473 34.152 21.42 34.32 ;
     RECT  20.473 34.32 21.408 34.344 ;
     RECT  20.473 34.344 21.42 34.464 ;
     RECT  20.473 34.464 21.408 34.488 ;
     RECT  20.473 34.488 21.42 34.656 ;
     RECT  20.473 34.656 21.408 34.68 ;
     RECT  20.473 34.68 21.42 34.8 ;
     RECT  20.473 34.8 21.408 34.824 ;
     RECT  20.473 34.824 21.42 34.992 ;
     RECT  20.473 34.992 21.408 35.016 ;
     RECT  20.473 35.016 21.42 35.184 ;
     RECT  20.473 35.184 21.408 35.208 ;
     RECT  20.473 35.208 21.42 35.328 ;
     RECT  20.473 35.328 21.408 35.352 ;
     RECT  20.473 35.352 21.42 35.52 ;
     RECT  20.473 35.52 21.408 35.544 ;
     RECT  20.473 35.544 21.42 35.664 ;
     RECT  20.473 35.664 21.408 35.688 ;
     RECT  20.473 35.688 21.42 35.856 ;
     RECT  20.473 35.856 21.408 35.88 ;
     RECT  20.473 35.88 21.42 36 ;
     RECT  20.473 36 21.408 36.024 ;
     RECT  20.473 36.024 21.42 36.192 ;
     RECT  20.473 36.192 21.408 36.216 ;
     RECT  20.473 36.216 21.42 36.384 ;
     RECT  20.473 36.384 21.408 36.408 ;
     RECT  20.473 36.408 21.42 36.528 ;
     RECT  20.473 36.528 21.408 36.552 ;
     RECT  20.473 36.552 21.42 36.72 ;
     RECT  20.473 36.72 21.408 36.744 ;
     RECT  20.473 36.744 21.42 36.864 ;
     RECT  20.473 36.864 21.408 36.888 ;
     RECT  20.473 36.888 21.42 37.056 ;
     RECT  20.473 37.056 21.408 37.08 ;
     RECT  20.473 37.08 21.42 37.2 ;
     RECT  20.473 37.2 21.408 37.224 ;
     RECT  20.473 37.224 21.42 37.392 ;
     RECT  20.473 37.392 21.408 37.416 ;
     RECT  20.473 37.416 21.42 37.584 ;
     RECT  20.473 37.584 21.408 37.608 ;
     RECT  20.473 37.608 21.42 37.728 ;
     RECT  20.473 37.728 21.408 37.752 ;
     RECT  20.473 37.752 21.42 37.92 ;
     RECT  20.473 37.92 21.408 37.944 ;
     RECT  20.473 37.944 21.42 38.064 ;
     RECT  20.473 38.064 21.408 38.088 ;
     RECT  20.473 38.088 21.42 38.256 ;
     RECT  20.473 38.256 21.408 38.28 ;
     RECT  20.473 38.28 21.42 38.448 ;
     RECT  20.473 38.448 21.408 38.472 ;
     RECT  20.473 38.472 21.42 38.592 ;
     RECT  20.473 38.592 21.408 38.616 ;
     RECT  20.473 38.616 21.42 38.784 ;
     RECT  20.473 38.784 21.408 38.808 ;
     RECT  20.473 38.808 21.42 38.928 ;
     RECT  20.473 38.928 21.408 38.952 ;
     RECT  20.473 38.952 21.42 39.12 ;
     RECT  20.473 39.12 21.408 39.144 ;
     RECT  20.473 39.144 21.42 39.264 ;
     RECT  20.473 39.264 21.408 39.288 ;
     RECT  20.473 39.288 21.42 39.456 ;
     RECT  20.473 39.456 21.408 39.48 ;
     RECT  20.473 39.48 21.42 39.648 ;
     RECT  20.473 39.648 21.408 39.672 ;
     RECT  20.473 39.672 21.42 39.792 ;
     RECT  20.473 39.792 21.408 39.816 ;
     RECT  20.473 39.816 21.42 39.984 ;
     RECT  20.473 39.984 21.408 40.008 ;
     RECT  20.473 40.008 21.42 40.128 ;
     RECT  20.473 40.128 21.408 40.152 ;
     RECT  20.473 40.152 21.42 40.32 ;
     RECT  20.473 40.32 21.408 40.344 ;
     RECT  20.473 40.344 21.42 40.464 ;
     RECT  20.473 40.464 21.408 40.488 ;
     RECT  20.473 40.488 21.42 40.656 ;
     RECT  20.473 40.656 21.408 40.68 ;
     RECT  20.473 40.68 21.42 40.848 ;
     RECT  20.473 40.848 21.408 40.872 ;
     RECT  20.473 40.872 21.42 40.992 ;
     RECT  20.473 40.992 21.408 41.016 ;
     RECT  20.473 41.016 21.42 41.184 ;
     RECT  20.473 41.184 21.408 41.208 ;
     RECT  20.473 41.208 21.42 41.328 ;
     RECT  20.473 41.328 21.408 41.352 ;
     RECT  20.473 41.352 21.42 41.52 ;
     RECT  20.473 41.52 21.408 41.544 ;
     RECT  20.473 41.544 21.42 41.712 ;
     RECT  20.473 41.712 21.408 41.736 ;
     RECT  20.473 41.736 21.42 41.856 ;
     RECT  20.473 41.856 21.408 41.88 ;
     RECT  20.473 41.88 21.42 42.048 ;
     RECT  20.473 42.048 21.408 42.072 ;
     RECT  20.473 42.072 21.42 42.192 ;
     RECT  20.473 42.192 21.408 42.216 ;
     RECT  20.473 42.216 21.42 42.384 ;
     RECT  20.473 42.384 21.408 42.408 ;
     RECT  20.473 42.408 21.42 42.528 ;
     RECT  20.473 42.528 21.408 42.552 ;
     RECT  20.473 42.552 21.42 42.72 ;
     RECT  20.473 42.72 21.408 42.744 ;
     RECT  20.473 42.744 21.42 42.912 ;
     RECT  20.473 42.912 21.408 42.936 ;
     RECT  20.473 42.936 21.42 43.056 ;
     RECT  20.473 43.056 21.408 43.08 ;
     RECT  20.473 43.08 21.42 43.248 ;
     RECT  20.473 43.248 21.408 43.272 ;
     RECT  20.473 43.272 21.42 43.392 ;
     RECT  20.473 43.392 21.408 43.416 ;
     RECT  20.473 43.416 21.42 43.584 ;
     RECT  20.473 43.584 21.408 43.608 ;
     RECT  20.473 43.608 21.42 43.728 ;
     RECT  20.473 43.728 21.408 43.752 ;
     RECT  20.473 43.752 21.42 43.92 ;
     RECT  20.473 43.92 21.408 43.944 ;
     RECT  20.473 43.944 21.42 44.112 ;
     RECT  20.473 44.112 21.408 44.136 ;
     RECT  20.473 44.136 21.42 44.256 ;
     RECT  20.473 44.256 21.408 44.28 ;
     RECT  20.473 44.28 21.42 44.448 ;
     RECT  20.473 44.448 21.408 44.472 ;
     RECT  20.473 44.472 21.42 44.592 ;
     RECT  20.473 44.592 21.408 44.616 ;
     RECT  20.473 44.616 21.42 44.784 ;
     RECT  20.473 44.784 21.408 44.808 ;
     RECT  20.473 44.808 21.42 44.976 ;
     RECT  20.473 44.976 21.408 45 ;
     RECT  20.473 45 21.42 45.12 ;
     RECT  20.473 45.12 21.408 45.144 ;
     RECT  20.473 45.144 21.42 45.312 ;
     RECT  20.473 45.312 21.408 45.336 ;
     RECT  20.473 45.336 21.42 45.456 ;
     RECT  20.473 45.456 21.408 45.48 ;
     RECT  20.473 45.48 21.42 45.648 ;
     RECT  20.473 45.648 21.408 45.672 ;
     RECT  20.473 45.672 21.42 45.792 ;
     RECT  20.473 45.792 21.408 45.816 ;
     RECT  20.473 45.816 21.42 45.984 ;
     RECT  20.473 45.984 21.408 46.008 ;
     RECT  20.473 46.008 21.42 46.176 ;
     RECT  20.473 46.176 21.408 46.2 ;
     RECT  20.473 46.2 21.42 46.32 ;
     RECT  20.473 46.32 21.408 46.344 ;
     RECT  20.473 46.344 21.42 46.512 ;
     RECT  20.473 46.512 21.408 46.536 ;
     RECT  20.473 46.536 21.42 46.656 ;
     RECT  20.473 46.656 21.408 46.68 ;
     RECT  20.473 46.68 21.42 46.848 ;
     RECT  20.473 46.848 21.408 46.872 ;
     RECT  20.473 46.872 21.42 46.992 ;
     RECT  20.473 46.992 21.408 47.016 ;
     RECT  20.473 47.016 21.42 47.184 ;
     RECT  20.473 47.184 21.408 47.208 ;
     RECT  20.473 47.208 21.42 47.376 ;
     RECT  20.473 47.376 21.408 47.4 ;
     RECT  20.473 47.4 21.42 47.52 ;
     RECT  20.473 47.52 21.408 47.544 ;
     RECT  20.473 47.544 21.42 47.712 ;
     RECT  20.473 47.712 21.408 47.736 ;
     RECT  20.473 47.736 21.42 47.856 ;
     RECT  20.473 47.856 21.408 47.88 ;
     RECT  20.473 47.88 21.42 48.048 ;
     RECT  20.473 48.048 21.408 48.072 ;
     RECT  20.473 48.072 21.42 48.24 ;
     RECT  20.473 48.24 21.408 48.264 ;
     RECT  20.473 48.264 21.42 48.384 ;
     RECT  20.473 48.384 21.408 48.408 ;
     RECT  20.473 48.408 21.42 48.576 ;
     RECT  20.473 48.576 21.408 48.6 ;
     RECT  20.473 48.6 21.42 48.72 ;
     RECT  20.473 48.72 21.408 48.744 ;
     RECT  20.473 48.744 21.42 48.912 ;
     RECT  20.473 48.912 21.408 48.936 ;
     RECT  20.473 48.936 21.42 49.056 ;
     RECT  20.473 49.056 21.408 49.08 ;
     RECT  20.473 49.08 21.42 49.248 ;
     RECT  20.473 49.248 21.408 49.272 ;
     RECT  20.473 49.272 21.42 49.44 ;
     RECT  20.473 49.44 21.408 49.464 ;
     RECT  20.473 49.464 21.42 49.584 ;
     RECT  20.473 49.584 21.408 49.608 ;
     RECT  20.473 49.608 21.42 49.776 ;
     RECT  20.473 49.776 21.408 49.8 ;
     RECT  20.473 49.8 21.42 49.92 ;
     RECT  20.473 49.92 21.408 49.944 ;
     RECT  20.473 49.944 21.42 50.112 ;
     RECT  20.473 50.112 21.408 50.136 ;
     RECT  20.473 50.136 21.42 50.256 ;
     RECT  20.473 50.256 21.408 50.28 ;
     RECT  20.473 50.28 21.42 50.448 ;
     RECT  20.473 50.448 21.408 50.472 ;
     RECT  20.473 50.472 21.42 50.64 ;
     RECT  20.473 50.64 21.408 50.664 ;
     RECT  20.473 50.664 21.42 50.784 ;
     RECT  20.473 50.784 21.408 50.808 ;
     RECT  20.473 50.808 21.42 50.976 ;
     RECT  20.473 50.976 21.408 51 ;
     RECT  20.473 51 21.42 51.12 ;
     RECT  20.473 51.12 21.408 51.144 ;
     RECT  20.473 51.144 21.42 51.312 ;
     RECT  20.473 51.312 21.408 51.336 ;
     RECT  20.473 51.336 21.42 51.504 ;
     RECT  20.473 51.504 21.408 51.528 ;
     RECT  20.473 51.528 21.42 51.648 ;
     RECT  20.473 51.648 21.408 51.672 ;
     RECT  21.42 31.632 21.449 31.656 ;
     RECT  21.42 40.56 21.449 40.584 ;
     RECT  21.42 20.016 21.485 20.16 ;
     RECT  21.42 20.184 21.485 20.352 ;
     RECT  21.42 20.376 21.485 20.496 ;
     RECT  21.42 20.52 21.485 20.688 ;
     RECT  21.42 20.712 21.485 20.832 ;
     RECT  21.42 20.856 21.485 21 ;
     RECT  21.42 22.464 21.485 22.488 ;
     RECT  21.42 23.808 21.485 23.832 ;
     RECT  21.42 32.88 21.485 32.928 ;
     RECT  21.42 32.952 21.485 33.12 ;
     RECT  21.42 33.144 21.485 33.264 ;
     RECT  21.42 33.288 21.485 33.456 ;
     RECT  21.42 33.48 21.485 33.6 ;
     RECT  21.42 33.624 21.485 33.792 ;
     RECT  21.42 33.816 21.485 33.96 ;
    LAYER M5 ;
     RECT  10.8 1.763 10.812 2.137 ;
     RECT  2.4 2.137 2.52 2.151 ;
     RECT  5.1 2.137 5.22 2.151 ;
     RECT  7.8 2.137 7.92 2.151 ;
     RECT  13.2 2.137 13.32 2.151 ;
     RECT  15.9 2.137 16.02 2.151 ;
     RECT  18.6 2.137 18.72 2.151 ;
     RECT  7.8 2.151 8.112 6.085 ;
     RECT  5.1 2.151 5.412 6.229 ;
     RECT  18.6 2.151 18.912 6.805 ;
     RECT  2.4 2.151 2.712 7.381 ;
     RECT  17.712 6.805 18.912 9.061 ;
     RECT  17.712 9.061 19.656 9.637 ;
     RECT  15.9 2.151 16.212 10.213 ;
     RECT  17.616 9.637 20.232 10.213 ;
     RECT  4.848 6.229 5.412 10.595 ;
     RECT  15.9 10.213 20.232 11.125 ;
     RECT  7.8 6.085 8.232 11.171 ;
     RECT  2.4 7.381 3.288 11.939 ;
     RECT  7.8 11.171 8.112 11.941 ;
     RECT  7.632 11.941 8.112 12.757 ;
     RECT  2.4 11.939 2.712 13.045 ;
     RECT  15.9 11.125 20.28 13.045 ;
     RECT  2.4 13.045 3.24 14.677 ;
     RECT  5.1 10.595 5.412 14.773 ;
     RECT  6.432 6.805 6.456 14.867 ;
     RECT  2.4 14.677 3.288 15.443 ;
     RECT  7.632 12.757 8.232 15.491 ;
     RECT  4.848 14.773 5.412 16.019 ;
     RECT  15.9 13.045 20.328 17.029 ;
     RECT  2.4 15.443 2.712 17.077 ;
     RECT  0.24 17.605 0.264 17.701 ;
     RECT  0.192 17.701 0.264 18.083 ;
     RECT  7.632 15.491 8.112 18.181 ;
     RECT  5.1 16.019 5.412 18.757 ;
     RECT  0.192 18.083 0.216 18.851 ;
     RECT  7.632 18.181 8.232 20.915 ;
     RECT  0.288 19.093 0.312 21.155 ;
     RECT  2.4 17.077 3.24 21.155 ;
     RECT  7.632 20.915 8.112 21.155 ;
     RECT  0.192 21.493 0.216 21.731 ;
     RECT  6.384 19.333 6.408 21.733 ;
     RECT  6.384 21.733 6.792 21.971 ;
     RECT  7.8 21.155 8.112 22.309 ;
     RECT  2.4 21.155 2.712 22.501 ;
     RECT  4.896 18.757 5.412 23.125 ;
     RECT  6.768 21.971 6.792 23.413 ;
     RECT  4.8 23.125 5.412 25.715 ;
     RECT  2.4 22.501 3.288 26.771 ;
     RECT  6.384 23.413 6.792 27.395 ;
     RECT  0.192 24.277 0.216 27.397 ;
     RECT  0.192 27.397 0.264 27.635 ;
     RECT  7.8 22.309 8.232 27.923 ;
     RECT  0.24 27.635 0.264 27.971 ;
     RECT  2.4 26.771 2.712 28.453 ;
     RECT  5.1 25.715 5.412 29.029 ;
     RECT  7.8 27.923 8.112 29.605 ;
     RECT  6.768 27.395 6.792 30.709 ;
     RECT  0.192 32.245 0.216 32.771 ;
     RECT  15.9 17.029 20.424 33.827 ;
     RECT  4.8 29.029 5.412 34.355 ;
     RECT  6.432 30.709 6.792 34.741 ;
     RECT  7.8 29.605 8.232 34.741 ;
     RECT  6.432 34.741 8.232 34.835 ;
     RECT  15.9 33.827 20.376 34.931 ;
     RECT  6.432 34.835 8.112 35.029 ;
     RECT  2.4 28.453 3.24 35.363 ;
     RECT  0.288 34.645 0.312 35.459 ;
     RECT  5.1 34.355 5.412 35.845 ;
     RECT  6.384 35.029 8.112 35.845 ;
     RECT  4.848 35.845 5.412 38.243 ;
     RECT  6.384 35.845 8.232 38.819 ;
     RECT  0.192 36.373 0.216 39.203 ;
     RECT  6.816 38.819 8.232 39.251 ;
     RECT  15.9 34.931 16.392 39.395 ;
     RECT  2.4 35.363 2.712 39.877 ;
     RECT  5.1 38.243 5.412 40.165 ;
     RECT  6.816 39.251 8.112 40.309 ;
     RECT  6.432 40.309 8.112 40.837 ;
     RECT  17.424 34.931 20.376 41.075 ;
     RECT  20.352 41.075 20.376 41.411 ;
     RECT  4.848 40.165 5.412 42.803 ;
     RECT  15.9 39.395 16.344 43.571 ;
     RECT  17.424 41.075 18.912 43.955 ;
     RECT  6.432 40.837 8.232 45.107 ;
     RECT  5.1 42.803 5.412 45.541 ;
     RECT  4.896 45.541 5.412 46.885 ;
     RECT  17.424 43.955 17.448 48.467 ;
     RECT  4.848 46.885 5.412 49.619 ;
     RECT  2.4 39.877 3.24 50.531 ;
     RECT  6.432 45.107 6.456 51.347 ;
     RECT  7.8 45.107 8.232 51.683 ;
     RECT  2.4 50.531 2.712 54.009 ;
     RECT  5.1 49.619 5.412 54.009 ;
     RECT  7.8 51.683 8.112 54.009 ;
     RECT  10.5 2.137 10.812 54.009 ;
     RECT  13.2 2.151 13.512 54.009 ;
     RECT  15.9 43.571 16.212 54.009 ;
     RECT  18.6 43.955 18.912 54.009 ;
     RECT  2.4 54.009 2.52 54.023 ;
     RECT  5.1 54.009 5.22 54.023 ;
     RECT  7.8 54.009 7.92 54.023 ;
     RECT  10.5 54.009 10.62 54.023 ;
     RECT  13.2 54.009 13.32 54.023 ;
     RECT  15.9 54.009 16.02 54.023 ;
     RECT  18.6 54.009 18.72 54.023 ;
     RECT  5.412 6.805 6.432 14.867 ;
     RECT  6.456 6.805 7.8 11.941 ;
     RECT  16.212 6.805 17.712 9.637 ;
     RECT  16.212 9.637 17.616 10.213 ;
     RECT  2.712 11.939 3.24 13.045 ;
     RECT  6.456 11.941 7.632 14.867 ;
     RECT  5.412 19.333 6.384 21.971 ;
     RECT  6.408 19.333 7.632 21.155 ;
     RECT  8.112 20.915 8.232 22.309 ;
     RECT  2.712 21.155 3.24 22.501 ;
     RECT  6.408 21.155 7.8 21.733 ;
     RECT  6.792 21.733 7.8 34.741 ;
     RECT  5.412 21.971 6.768 23.413 ;
     RECT  3.288 23.125 4.8 25.715 ;
     RECT  5.412 23.413 6.384 27.395 ;
     RECT  5.412 27.395 6.768 30.709 ;
     RECT  5.412 30.709 6.432 35.029 ;
     RECT  4.848 34.355 5.1 35.845 ;
     RECT  8.112 34.835 8.232 35.845 ;
     RECT  16.392 34.931 17.424 39.395 ;
     RECT  5.412 35.029 6.384 38.819 ;
     RECT  5.412 38.819 6.816 40.309 ;
     RECT  16.344 39.395 17.424 43.571 ;
     RECT  5.412 40.309 6.432 51.347 ;
     RECT  18.912 41.075 20.352 41.411 ;
     RECT  16.212 43.571 17.424 48.467 ;
     RECT  17.448 43.955 18.6 48.467 ;
     RECT  6.456 45.107 7.8 51.347 ;
  END
END hbfd_rly_136_WE_fc_f2
END LIBRARY
